VERSION 5.8 ;
BUSBITCHARS "[]" ;
DIVIDERCHAR "/" ;
UNITS
    DATABASE MICRONS 1000 ;
END UNITS

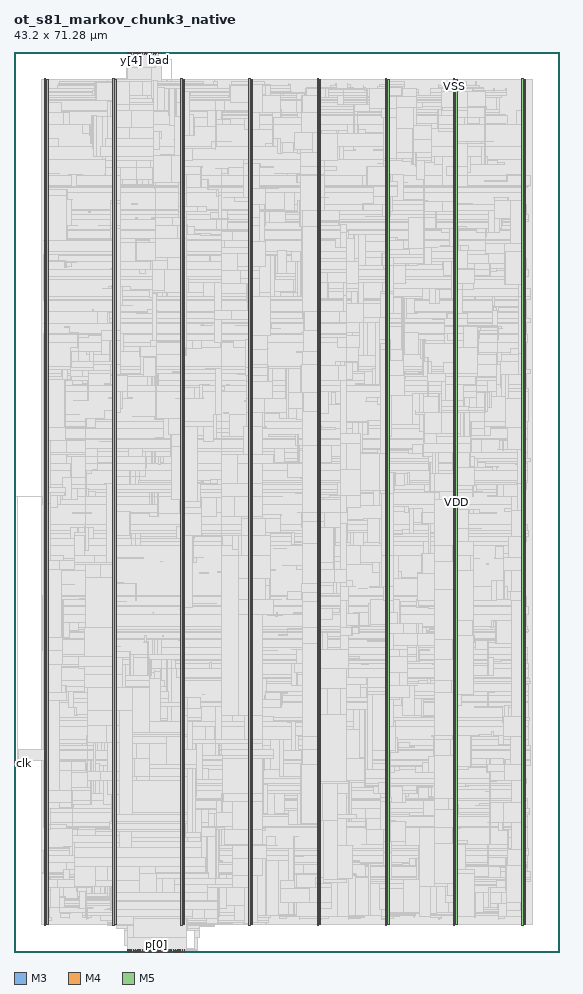
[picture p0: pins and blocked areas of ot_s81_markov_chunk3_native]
MACRO ot_s81_markov_chunk3_native
  FOREIGN ot_s81_markov_chunk3_native 0 0 ;
  CLASS BLOCK ;
  SIZE 43.2 BY 71.28 ;
  PIN bad
    DIRECTION OUTPUT ;
    USE SIGNAL ;
    PORT
      LAYER M3 ;
        RECT  11.448 71.136 11.466 71.28 ;
    END
  END bad
  PIN clk
    DIRECTION INPUT ;
    USE SIGNAL ;
    PORT
      LAYER M4 ;
        RECT  0 14.88 0.192 14.904 ;
    END
  END clk
  PIN p[0]
    DIRECTION INPUT ;
    USE SIGNAL ;
    PORT
      LAYER M3 ;
        RECT  11.304 0 11.322 0.144 ;
    END
  END p[0]
  PIN p[10]
    DIRECTION INPUT ;
    USE SIGNAL ;
    PORT
      LAYER M3 ;
        RECT  12.024 0 12.042 0.144 ;
    END
  END p[10]
  PIN p[11]
    DIRECTION INPUT ;
    USE SIGNAL ;
    PORT
      LAYER M5 ;
        RECT  12.048 0 12.072 0.192 ;
    END
  END p[11]
  PIN p[12]
    DIRECTION INPUT ;
    USE SIGNAL ;
    PORT
      LAYER M3 ;
        RECT  12.168 0 12.186 0.144 ;
    END
  END p[12]
  PIN p[13]
    DIRECTION INPUT ;
    USE SIGNAL ;
    PORT
      LAYER M5 ;
        RECT  12.192 0 12.216 0.192 ;
    END
  END p[13]
  PIN p[14]
    DIRECTION INPUT ;
    USE SIGNAL ;
    PORT
      LAYER M3 ;
        RECT  12.312 0 12.33 0.144 ;
    END
  END p[14]
  PIN p[15]
    DIRECTION INPUT ;
    USE SIGNAL ;
    PORT
      LAYER M5 ;
        RECT  12.336 0 12.36 0.192 ;
    END
  END p[15]
  PIN p[16]
    DIRECTION INPUT ;
    USE SIGNAL ;
    PORT
      LAYER M3 ;
        RECT  12.456 0 12.474 0.144 ;
    END
  END p[16]
  PIN p[17]
    DIRECTION INPUT ;
    USE SIGNAL ;
    PORT
      LAYER M5 ;
        RECT  12.48 0 12.504 0.192 ;
    END
  END p[17]
  PIN p[18]
    DIRECTION INPUT ;
    USE SIGNAL ;
    PORT
      LAYER M3 ;
        RECT  12.6 0 12.618 0.144 ;
    END
  END p[18]
  PIN p[19]
    DIRECTION INPUT ;
    USE SIGNAL ;
    PORT
      LAYER M5 ;
        RECT  12.624 0 12.648 0.192 ;
    END
  END p[19]
  PIN p[1]
    DIRECTION INPUT ;
    USE SIGNAL ;
    PORT
      LAYER M5 ;
        RECT  11.328 0 11.352 0.192 ;
    END
  END p[1]
  PIN p[20]
    DIRECTION INPUT ;
    USE SIGNAL ;
    PORT
      LAYER M3 ;
        RECT  12.744 0 12.762 0.144 ;
    END
  END p[20]
  PIN p[21]
    DIRECTION INPUT ;
    USE SIGNAL ;
    PORT
      LAYER M5 ;
        RECT  12.768 0 12.792 0.192 ;
    END
  END p[21]
  PIN p[22]
    DIRECTION INPUT ;
    USE SIGNAL ;
    PORT
      LAYER M3 ;
        RECT  12.888 0 12.906 0.144 ;
    END
  END p[22]
  PIN p[23]
    DIRECTION INPUT ;
    USE SIGNAL ;
    PORT
      LAYER M5 ;
        RECT  12.912 0 12.936 0.192 ;
    END
  END p[23]
  PIN p[24]
    DIRECTION INPUT ;
    USE SIGNAL ;
    PORT
      LAYER M3 ;
        RECT  13.032 0 13.05 0.144 ;
    END
  END p[24]
  PIN p[25]
    DIRECTION INPUT ;
    USE SIGNAL ;
    PORT
      LAYER M5 ;
        RECT  13.056 0 13.08 0.192 ;
    END
  END p[25]
  PIN p[26]
    DIRECTION INPUT ;
    USE SIGNAL ;
    PORT
      LAYER M3 ;
        RECT  13.176 0 13.194 0.144 ;
    END
  END p[26]
  PIN p[27]
    DIRECTION INPUT ;
    USE SIGNAL ;
    PORT
      LAYER M5 ;
        RECT  13.2 0 13.224 0.192 ;
    END
  END p[27]
  PIN p[28]
    DIRECTION INPUT ;
    USE SIGNAL ;
    PORT
      LAYER M3 ;
        RECT  13.32 0 13.338 0.144 ;
    END
  END p[28]
  PIN p[29]
    DIRECTION INPUT ;
    USE SIGNAL ;
    PORT
      LAYER M5 ;
        RECT  13.344 0 13.368 0.192 ;
    END
  END p[29]
  PIN p[2]
    DIRECTION INPUT ;
    USE SIGNAL ;
    PORT
      LAYER M3 ;
        RECT  11.448 0 11.466 0.144 ;
    END
  END p[2]
  PIN p[30]
    DIRECTION INPUT ;
    USE SIGNAL ;
    PORT
      LAYER M3 ;
        RECT  13.464 0 13.482 0.144 ;
    END
  END p[30]
  PIN p[31]
    DIRECTION INPUT ;
    USE SIGNAL ;
    PORT
      LAYER M5 ;
        RECT  13.488 0 13.512 0.192 ;
    END
  END p[31]
  PIN p[3]
    DIRECTION INPUT ;
    USE SIGNAL ;
    PORT
      LAYER M5 ;
        RECT  11.472 0 11.496 0.192 ;
    END
  END p[3]
  PIN p[4]
    DIRECTION INPUT ;
    USE SIGNAL ;
    PORT
      LAYER M3 ;
        RECT  11.592 0 11.61 0.144 ;
    END
  END p[4]
  PIN p[5]
    DIRECTION INPUT ;
    USE SIGNAL ;
    PORT
      LAYER M5 ;
        RECT  11.616 0 11.64 0.192 ;
    END
  END p[5]
  PIN p[6]
    DIRECTION INPUT ;
    USE SIGNAL ;
    PORT
      LAYER M3 ;
        RECT  11.736 0 11.754 0.144 ;
    END
  END p[6]
  PIN p[7]
    DIRECTION INPUT ;
    USE SIGNAL ;
    PORT
      LAYER M5 ;
        RECT  11.76 0 11.784 0.192 ;
    END
  END p[7]
  PIN p[8]
    DIRECTION INPUT ;
    USE SIGNAL ;
    PORT
      LAYER M3 ;
        RECT  11.88 0 11.898 0.144 ;
    END
  END p[8]
  PIN p[9]
    DIRECTION INPUT ;
    USE SIGNAL ;
    PORT
      LAYER M5 ;
        RECT  11.904 0 11.928 0.192 ;
    END
  END p[9]
  PIN rst_n
    DIRECTION INPUT ;
    USE SIGNAL ;
    PORT
      LAYER M4 ;
        RECT  0 15.024 0.192 15.048 ;
    END
  END rst_n
  PIN sum[0]
    DIRECTION INPUT ;
    USE SIGNAL ;
    PORT
      LAYER M3 ;
        RECT  9 0 9.018 0.144 ;
    END
  END sum[0]
  PIN sum[10]
    DIRECTION INPUT ;
    USE SIGNAL ;
    PORT
      LAYER M3 ;
        RECT  9.72 0 9.738 0.144 ;
    END
  END sum[10]
  PIN sum[11]
    DIRECTION INPUT ;
    USE SIGNAL ;
    PORT
      LAYER M5 ;
        RECT  9.744 0 9.768 0.192 ;
    END
  END sum[11]
  PIN sum[12]
    DIRECTION INPUT ;
    USE SIGNAL ;
    PORT
      LAYER M3 ;
        RECT  9.864 0 9.882 0.144 ;
    END
  END sum[12]
  PIN sum[13]
    DIRECTION INPUT ;
    USE SIGNAL ;
    PORT
      LAYER M5 ;
        RECT  9.888 0 9.912 0.192 ;
    END
  END sum[13]
  PIN sum[14]
    DIRECTION INPUT ;
    USE SIGNAL ;
    PORT
      LAYER M3 ;
        RECT  10.008 0 10.026 0.144 ;
    END
  END sum[14]
  PIN sum[15]
    DIRECTION INPUT ;
    USE SIGNAL ;
    PORT
      LAYER M5 ;
        RECT  10.032 0 10.056 0.192 ;
    END
  END sum[15]
  PIN sum[16]
    DIRECTION INPUT ;
    USE SIGNAL ;
    PORT
      LAYER M3 ;
        RECT  10.152 0 10.17 0.144 ;
    END
  END sum[16]
  PIN sum[17]
    DIRECTION INPUT ;
    USE SIGNAL ;
    PORT
      LAYER M5 ;
        RECT  10.176 0 10.2 0.192 ;
    END
  END sum[17]
  PIN sum[18]
    DIRECTION INPUT ;
    USE SIGNAL ;
    PORT
      LAYER M3 ;
        RECT  10.296 0 10.314 0.144 ;
    END
  END sum[18]
  PIN sum[19]
    DIRECTION INPUT ;
    USE SIGNAL ;
    PORT
      LAYER M5 ;
        RECT  10.32 0 10.344 0.192 ;
    END
  END sum[19]
  PIN sum[1]
    DIRECTION INPUT ;
    USE SIGNAL ;
    PORT
      LAYER M5 ;
        RECT  9.024 0 9.048 0.192 ;
    END
  END sum[1]
  PIN sum[20]
    DIRECTION INPUT ;
    USE SIGNAL ;
    PORT
      LAYER M3 ;
        RECT  10.44 0 10.458 0.144 ;
    END
  END sum[20]
  PIN sum[21]
    DIRECTION INPUT ;
    USE SIGNAL ;
    PORT
      LAYER M5 ;
        RECT  10.464 0 10.488 0.192 ;
    END
  END sum[21]
  PIN sum[22]
    DIRECTION INPUT ;
    USE SIGNAL ;
    PORT
      LAYER M3 ;
        RECT  10.584 0 10.602 0.144 ;
    END
  END sum[22]
  PIN sum[23]
    DIRECTION INPUT ;
    USE SIGNAL ;
    PORT
      LAYER M5 ;
        RECT  10.608 0 10.632 0.192 ;
    END
  END sum[23]
  PIN sum[24]
    DIRECTION INPUT ;
    USE SIGNAL ;
    PORT
      LAYER M3 ;
        RECT  10.728 0 10.746 0.144 ;
    END
  END sum[24]
  PIN sum[25]
    DIRECTION INPUT ;
    USE SIGNAL ;
    PORT
      LAYER M5 ;
        RECT  10.752 0 10.776 0.192 ;
    END
  END sum[25]
  PIN sum[26]
    DIRECTION INPUT ;
    USE SIGNAL ;
    PORT
      LAYER M3 ;
        RECT  10.872 0 10.89 0.144 ;
    END
  END sum[26]
  PIN sum[27]
    DIRECTION INPUT ;
    USE SIGNAL ;
    PORT
      LAYER M5 ;
        RECT  10.896 0 10.92 0.192 ;
    END
  END sum[27]
  PIN sum[28]
    DIRECTION INPUT ;
    USE SIGNAL ;
    PORT
      LAYER M3 ;
        RECT  11.016 0 11.034 0.144 ;
    END
  END sum[28]
  PIN sum[29]
    DIRECTION INPUT ;
    USE SIGNAL ;
    PORT
      LAYER M5 ;
        RECT  11.04 0 11.064 0.192 ;
    END
  END sum[29]
  PIN sum[2]
    DIRECTION INPUT ;
    USE SIGNAL ;
    PORT
      LAYER M3 ;
        RECT  9.144 0 9.162 0.144 ;
    END
  END sum[2]
  PIN sum[30]
    DIRECTION INPUT ;
    USE SIGNAL ;
    PORT
      LAYER M3 ;
        RECT  11.16 0 11.178 0.144 ;
    END
  END sum[30]
  PIN sum[31]
    DIRECTION INPUT ;
    USE SIGNAL ;
    PORT
      LAYER M5 ;
        RECT  11.184 0 11.208 0.192 ;
    END
  END sum[31]
  PIN sum[3]
    DIRECTION INPUT ;
    USE SIGNAL ;
    PORT
      LAYER M5 ;
        RECT  9.168 0 9.192 0.192 ;
    END
  END sum[3]
  PIN sum[4]
    DIRECTION INPUT ;
    USE SIGNAL ;
    PORT
      LAYER M3 ;
        RECT  9.288 0 9.306 0.144 ;
    END
  END sum[4]
  PIN sum[5]
    DIRECTION INPUT ;
    USE SIGNAL ;
    PORT
      LAYER M5 ;
        RECT  9.312 0 9.336 0.192 ;
    END
  END sum[5]
  PIN sum[6]
    DIRECTION INPUT ;
    USE SIGNAL ;
    PORT
      LAYER M3 ;
        RECT  9.432 0 9.45 0.144 ;
    END
  END sum[6]
  PIN sum[7]
    DIRECTION INPUT ;
    USE SIGNAL ;
    PORT
      LAYER M5 ;
        RECT  9.456 0 9.48 0.192 ;
    END
  END sum[7]
  PIN sum[8]
    DIRECTION INPUT ;
    USE SIGNAL ;
    PORT
      LAYER M3 ;
        RECT  9.576 0 9.594 0.144 ;
    END
  END sum[8]
  PIN sum[9]
    DIRECTION INPUT ;
    USE SIGNAL ;
    PORT
      LAYER M5 ;
        RECT  9.6 0 9.624 0.192 ;
    END
  END sum[9]
  PIN vin
    DIRECTION INPUT ;
    USE SIGNAL ;
    PORT
      LAYER M4 ;
        RECT  0 15.168 0.192 15.192 ;
    END
  END vin
  PIN vout
    DIRECTION OUTPUT ;
    USE SIGNAL ;
    PORT
      LAYER M3 ;
        RECT  11.304 71.136 11.322 71.28 ;
    END
  END vout
  PIN y[0]
    DIRECTION OUTPUT ;
    USE SIGNAL ;
    PORT
      LAYER M3 ;
        RECT  9 71.136 9.018 71.28 ;
    END
  END y[0]
  PIN y[10]
    DIRECTION OUTPUT ;
    USE SIGNAL ;
    PORT
      LAYER M3 ;
        RECT  9.72 71.136 9.738 71.28 ;
    END
  END y[10]
  PIN y[11]
    DIRECTION OUTPUT ;
    USE SIGNAL ;
    PORT
      LAYER M5 ;
        RECT  9.744 71.088 9.768 71.28 ;
    END
  END y[11]
  PIN y[12]
    DIRECTION OUTPUT ;
    USE SIGNAL ;
    PORT
      LAYER M3 ;
        RECT  9.864 71.136 9.882 71.28 ;
    END
  END y[12]
  PIN y[13]
    DIRECTION OUTPUT ;
    USE SIGNAL ;
    PORT
      LAYER M5 ;
        RECT  9.888 71.088 9.912 71.28 ;
    END
  END y[13]
  PIN y[14]
    DIRECTION OUTPUT ;
    USE SIGNAL ;
    PORT
      LAYER M3 ;
        RECT  10.008 71.136 10.026 71.28 ;
    END
  END y[14]
  PIN y[15]
    DIRECTION OUTPUT ;
    USE SIGNAL ;
    PORT
      LAYER M5 ;
        RECT  10.032 71.088 10.056 71.28 ;
    END
  END y[15]
  PIN y[16]
    DIRECTION OUTPUT ;
    USE SIGNAL ;
    PORT
      LAYER M3 ;
        RECT  10.152 71.136 10.17 71.28 ;
    END
  END y[16]
  PIN y[17]
    DIRECTION OUTPUT ;
    USE SIGNAL ;
    PORT
      LAYER M5 ;
        RECT  10.176 71.088 10.2 71.28 ;
    END
  END y[17]
  PIN y[18]
    DIRECTION OUTPUT ;
    USE SIGNAL ;
    PORT
      LAYER M3 ;
        RECT  10.296 71.136 10.314 71.28 ;
    END
  END y[18]
  PIN y[19]
    DIRECTION OUTPUT ;
    USE SIGNAL ;
    PORT
      LAYER M5 ;
        RECT  10.32 71.088 10.344 71.28 ;
    END
  END y[19]
  PIN y[1]
    DIRECTION OUTPUT ;
    USE SIGNAL ;
    PORT
      LAYER M5 ;
        RECT  9.024 71.088 9.048 71.28 ;
    END
  END y[1]
  PIN y[20]
    DIRECTION OUTPUT ;
    USE SIGNAL ;
    PORT
      LAYER M3 ;
        RECT  10.44 71.136 10.458 71.28 ;
    END
  END y[20]
  PIN y[21]
    DIRECTION OUTPUT ;
    USE SIGNAL ;
    PORT
      LAYER M5 ;
        RECT  10.464 71.088 10.488 71.28 ;
    END
  END y[21]
  PIN y[22]
    DIRECTION OUTPUT ;
    USE SIGNAL ;
    PORT
      LAYER M3 ;
        RECT  10.584 71.136 10.602 71.28 ;
    END
  END y[22]
  PIN y[23]
    DIRECTION OUTPUT ;
    USE SIGNAL ;
    PORT
      LAYER M5 ;
        RECT  10.608 71.088 10.632 71.28 ;
    END
  END y[23]
  PIN y[24]
    DIRECTION OUTPUT ;
    USE SIGNAL ;
    PORT
      LAYER M3 ;
        RECT  10.728 71.136 10.746 71.28 ;
    END
  END y[24]
  PIN y[25]
    DIRECTION OUTPUT ;
    USE SIGNAL ;
    PORT
      LAYER M5 ;
        RECT  10.752 71.088 10.776 71.28 ;
    END
  END y[25]
  PIN y[26]
    DIRECTION OUTPUT ;
    USE SIGNAL ;
    PORT
      LAYER M3 ;
        RECT  10.872 71.136 10.89 71.28 ;
    END
  END y[26]
  PIN y[27]
    DIRECTION OUTPUT ;
    USE SIGNAL ;
    PORT
      LAYER M5 ;
        RECT  10.896 71.088 10.92 71.28 ;
    END
  END y[27]
  PIN y[28]
    DIRECTION OUTPUT ;
    USE SIGNAL ;
    PORT
      LAYER M3 ;
        RECT  11.016 71.136 11.034 71.28 ;
    END
  END y[28]
  PIN y[29]
    DIRECTION OUTPUT ;
    USE SIGNAL ;
    PORT
      LAYER M5 ;
        RECT  11.04 71.088 11.064 71.28 ;
    END
  END y[29]
  PIN y[2]
    DIRECTION OUTPUT ;
    USE SIGNAL ;
    PORT
      LAYER M3 ;
        RECT  9.144 71.136 9.162 71.28 ;
    END
  END y[2]
  PIN y[30]
    DIRECTION OUTPUT ;
    USE SIGNAL ;
    PORT
      LAYER M3 ;
        RECT  11.16 71.136 11.178 71.28 ;
    END
  END y[30]
  PIN y[31]
    DIRECTION OUTPUT ;
    USE SIGNAL ;
    PORT
      LAYER M5 ;
        RECT  11.184 71.088 11.208 71.28 ;
    END
  END y[31]
  PIN y[3]
    DIRECTION OUTPUT ;
    USE SIGNAL ;
    PORT
      LAYER M5 ;
        RECT  9.168 71.088 9.192 71.28 ;
    END
  END y[3]
  PIN y[4]
    DIRECTION OUTPUT ;
    USE SIGNAL ;
    PORT
      LAYER M3 ;
        RECT  9.288 71.136 9.306 71.28 ;
    END
  END y[4]
  PIN y[5]
    DIRECTION OUTPUT ;
    USE SIGNAL ;
    PORT
      LAYER M5 ;
        RECT  9.312 71.088 9.336 71.28 ;
    END
  END y[5]
  PIN y[6]
    DIRECTION OUTPUT ;
    USE SIGNAL ;
    PORT
      LAYER M3 ;
        RECT  9.432 71.136 9.45 71.28 ;
    END
  END y[6]
  PIN y[7]
    DIRECTION OUTPUT ;
    USE SIGNAL ;
    PORT
      LAYER M5 ;
        RECT  9.456 71.088 9.48 71.28 ;
    END
  END y[7]
  PIN y[8]
    DIRECTION OUTPUT ;
    USE SIGNAL ;
    PORT
      LAYER M3 ;
        RECT  9.576 71.136 9.594 71.28 ;
    END
  END y[8]
  PIN y[9]
    DIRECTION OUTPUT ;
    USE SIGNAL ;
    PORT
      LAYER M5 ;
        RECT  9.6 71.088 9.624 71.28 ;
    END
  END y[9]
  PIN VDD
    DIRECTION INOUT ;
    USE POWER ;
    PORT
      LAYER M5 ;
        RECT  40.392 2.151 40.512 69.129 ;
        RECT  34.992 2.151 35.112 69.129 ;
        RECT  29.592 2.151 29.712 69.129 ;
        RECT  24.192 2.151 24.312 69.129 ;
        RECT  18.792 2.151 18.912 69.129 ;
        RECT  13.392 2.151 13.512 69.129 ;
        RECT  7.992 2.151 8.112 69.129 ;
        RECT  2.592 2.151 2.712 69.129 ;
    END
  END VDD
  PIN VSS
    DIRECTION INOUT ;
    USE GROUND ;
    PORT
      LAYER M5 ;
        RECT  40.2 2.137 40.32 69.143 ;
        RECT  34.8 2.137 34.92 69.143 ;
        RECT  29.4 2.137 29.52 69.143 ;
        RECT  24 2.137 24.12 69.143 ;
        RECT  18.6 2.137 18.72 69.143 ;
        RECT  13.2 2.137 13.32 69.143 ;
        RECT  7.8 2.137 7.92 69.143 ;
        RECT  2.4 2.137 2.52 69.143 ;
    END
  END VSS
  # OT_OBS_CLOSED layer=M5 d_um=1.536 added=289
  OBS
    LAYER RVTN ;
     RECT  2.16 2.16 41.04 2.295 ;
     RECT  2.16 2.565 41.04 2.835 ;
     RECT  2.16 3.105 41.04 3.375 ;
     RECT  2.16 3.645 41.04 3.915 ;
     RECT  2.16 4.185 41.04 4.455 ;
     RECT  2.16 4.725 41.04 4.995 ;
     RECT  2.16 5.265 41.04 5.535 ;
     RECT  2.16 5.805 41.04 6.075 ;
     RECT  2.16 6.345 41.04 6.615 ;
     RECT  2.16 6.885 41.04 7.155 ;
     RECT  2.16 7.425 41.04 7.695 ;
     RECT  2.16 7.965 41.04 8.235 ;
     RECT  2.16 8.505 41.04 8.775 ;
     RECT  2.16 9.045 41.04 9.315 ;
     RECT  2.16 9.585 41.04 9.855 ;
     RECT  2.16 10.125 41.04 10.395 ;
     RECT  2.16 10.665 41.04 10.935 ;
     RECT  2.16 11.205 41.04 11.475 ;
     RECT  2.16 11.745 41.04 12.015 ;
     RECT  2.16 12.285 41.04 12.555 ;
     RECT  2.16 12.825 41.04 13.095 ;
     RECT  2.16 13.365 41.04 13.635 ;
     RECT  2.16 13.905 41.04 14.175 ;
     RECT  2.16 14.445 41.04 14.715 ;
     RECT  2.16 14.985 41.04 15.255 ;
     RECT  2.16 15.525 41.04 15.795 ;
     RECT  2.16 16.065 41.04 16.335 ;
     RECT  2.16 16.605 41.04 16.875 ;
     RECT  2.16 17.145 41.04 17.415 ;
     RECT  2.16 17.685 41.04 17.955 ;
     RECT  2.16 18.225 41.04 18.495 ;
     RECT  2.16 18.765 41.04 19.035 ;
     RECT  2.16 19.305 41.04 19.575 ;
     RECT  2.16 19.845 41.04 20.115 ;
     RECT  2.16 20.385 41.04 20.655 ;
     RECT  2.16 20.925 41.04 21.195 ;
     RECT  2.16 21.465 41.04 21.735 ;
     RECT  2.16 22.005 41.04 22.275 ;
     RECT  2.16 22.545 41.04 22.815 ;
     RECT  2.16 23.085 41.04 23.355 ;
     RECT  2.16 23.625 41.04 23.895 ;
     RECT  2.16 24.165 41.04 24.435 ;
     RECT  2.16 24.705 41.04 24.975 ;
     RECT  2.16 25.245 41.04 25.515 ;
     RECT  2.16 25.785 41.04 26.055 ;
     RECT  2.16 26.325 41.04 26.595 ;
     RECT  2.16 26.865 41.04 27.135 ;
     RECT  2.16 27.405 41.04 27.675 ;
     RECT  2.16 27.945 41.04 28.215 ;
     RECT  2.16 28.485 41.04 28.755 ;
     RECT  2.16 29.025 41.04 29.295 ;
     RECT  2.16 29.565 41.04 29.835 ;
     RECT  2.16 30.105 41.04 30.375 ;
     RECT  2.16 30.645 41.04 30.915 ;
     RECT  2.16 31.185 41.04 31.455 ;
     RECT  2.16 31.725 41.04 31.995 ;
     RECT  2.16 32.265 41.04 32.535 ;
     RECT  2.16 32.805 41.04 33.075 ;
     RECT  2.16 33.345 41.04 33.615 ;
     RECT  2.16 33.885 41.04 34.155 ;
     RECT  2.16 34.425 41.04 34.695 ;
     RECT  2.16 34.965 41.04 35.235 ;
     RECT  2.16 35.505 41.04 35.775 ;
     RECT  2.16 36.045 41.04 36.315 ;
     RECT  2.16 36.585 41.04 36.855 ;
     RECT  2.16 37.125 41.04 37.395 ;
     RECT  2.16 37.665 41.04 37.935 ;
     RECT  2.16 38.205 41.04 38.475 ;
     RECT  2.16 38.745 41.04 39.015 ;
     RECT  2.16 39.285 41.04 39.555 ;
     RECT  2.16 39.825 41.04 40.095 ;
     RECT  2.16 40.365 41.04 40.635 ;
     RECT  2.16 40.905 41.04 41.175 ;
     RECT  2.16 41.445 41.04 41.715 ;
     RECT  2.16 41.985 41.04 42.255 ;
     RECT  2.16 42.525 41.04 42.795 ;
     RECT  2.16 43.065 41.04 43.335 ;
     RECT  2.16 43.605 41.04 43.875 ;
     RECT  2.16 44.145 41.04 44.415 ;
     RECT  2.16 44.685 41.04 44.955 ;
     RECT  2.16 45.225 41.04 45.495 ;
     RECT  2.16 45.765 41.04 46.035 ;
     RECT  2.16 46.305 41.04 46.575 ;
     RECT  2.16 46.845 41.04 47.115 ;
     RECT  2.16 47.385 41.04 47.655 ;
     RECT  2.16 47.925 41.04 48.195 ;
     RECT  2.16 48.465 41.04 48.735 ;
     RECT  2.16 49.005 41.04 49.275 ;
     RECT  2.16 49.545 41.04 49.815 ;
     RECT  2.16 50.085 41.04 50.355 ;
     RECT  2.16 50.625 41.04 50.895 ;
     RECT  2.16 51.165 41.04 51.435 ;
     RECT  2.16 51.705 41.04 51.975 ;
     RECT  2.16 52.245 41.04 52.515 ;
     RECT  2.16 52.785 41.04 53.055 ;
     RECT  2.16 53.325 41.04 53.595 ;
     RECT  2.16 53.865 41.04 54.135 ;
     RECT  2.16 54.405 41.04 54.675 ;
     RECT  2.16 54.945 41.04 55.215 ;
     RECT  2.16 55.485 41.04 55.755 ;
     RECT  2.16 56.025 41.04 56.295 ;
     RECT  2.16 56.565 41.04 56.835 ;
     RECT  2.16 57.105 41.04 57.375 ;
     RECT  2.16 57.645 41.04 57.915 ;
     RECT  2.16 58.185 41.04 58.455 ;
     RECT  2.16 58.725 41.04 58.995 ;
     RECT  2.16 59.265 41.04 59.535 ;
     RECT  2.16 59.805 41.04 60.075 ;
     RECT  2.16 60.345 41.04 60.615 ;
     RECT  2.16 60.885 41.04 61.155 ;
     RECT  2.16 61.425 41.04 61.695 ;
     RECT  2.16 61.965 41.04 62.235 ;
     RECT  2.16 62.505 41.04 62.775 ;
     RECT  2.16 63.045 41.04 63.315 ;
     RECT  2.16 63.585 41.04 63.855 ;
     RECT  2.16 64.125 41.04 64.395 ;
     RECT  2.16 64.665 41.04 64.935 ;
     RECT  2.16 65.205 41.04 65.475 ;
     RECT  2.16 65.745 41.04 66.015 ;
     RECT  2.16 66.285 41.04 66.555 ;
     RECT  2.16 66.825 41.04 67.095 ;
     RECT  2.16 67.365 41.04 67.635 ;
     RECT  2.16 67.905 41.04 68.175 ;
     RECT  2.16 68.445 41.04 68.715 ;
     RECT  2.16 68.985 41.04 69.12 ;
    LAYER RVTP ;
     RECT  2.16 2.295 41.04 2.565 ;
     RECT  2.16 2.835 41.04 3.105 ;
     RECT  2.16 3.375 41.04 3.645 ;
     RECT  2.16 3.915 41.04 4.185 ;
     RECT  2.16 4.455 41.04 4.725 ;
     RECT  2.16 4.995 41.04 5.265 ;
     RECT  2.16 5.535 41.04 5.805 ;
     RECT  2.16 6.075 41.04 6.345 ;
     RECT  2.16 6.615 41.04 6.885 ;
     RECT  2.16 7.155 41.04 7.425 ;
     RECT  2.16 7.695 41.04 7.965 ;
     RECT  2.16 8.235 41.04 8.505 ;
     RECT  2.16 8.775 41.04 9.045 ;
     RECT  2.16 9.315 41.04 9.585 ;
     RECT  2.16 9.855 41.04 10.125 ;
     RECT  2.16 10.395 41.04 10.665 ;
     RECT  2.16 10.935 41.04 11.205 ;
     RECT  2.16 11.475 41.04 11.745 ;
     RECT  2.16 12.015 41.04 12.285 ;
     RECT  2.16 12.555 41.04 12.825 ;
     RECT  2.16 13.095 41.04 13.365 ;
     RECT  2.16 13.635 41.04 13.905 ;
     RECT  2.16 14.175 41.04 14.445 ;
     RECT  2.16 14.715 41.04 14.985 ;
     RECT  2.16 15.255 41.04 15.525 ;
     RECT  2.16 15.795 41.04 16.065 ;
     RECT  2.16 16.335 41.04 16.605 ;
     RECT  2.16 16.875 41.04 17.145 ;
     RECT  2.16 17.415 41.04 17.685 ;
     RECT  2.16 17.955 41.04 18.225 ;
     RECT  2.16 18.495 41.04 18.765 ;
     RECT  2.16 19.035 41.04 19.305 ;
     RECT  2.16 19.575 41.04 19.845 ;
     RECT  2.16 20.115 41.04 20.385 ;
     RECT  2.16 20.655 41.04 20.925 ;
     RECT  2.16 21.195 41.04 21.465 ;
     RECT  2.16 21.735 41.04 22.005 ;
     RECT  2.16 22.275 41.04 22.545 ;
     RECT  2.16 22.815 41.04 23.085 ;
     RECT  2.16 23.355 41.04 23.625 ;
     RECT  2.16 23.895 41.04 24.165 ;
     RECT  2.16 24.435 41.04 24.705 ;
     RECT  2.16 24.975 41.04 25.245 ;
     RECT  2.16 25.515 41.04 25.785 ;
     RECT  2.16 26.055 41.04 26.325 ;
     RECT  2.16 26.595 41.04 26.865 ;
     RECT  2.16 27.135 41.04 27.405 ;
     RECT  2.16 27.675 41.04 27.945 ;
     RECT  2.16 28.215 41.04 28.485 ;
     RECT  2.16 28.755 41.04 29.025 ;
     RECT  2.16 29.295 41.04 29.565 ;
     RECT  2.16 29.835 41.04 30.105 ;
     RECT  2.16 30.375 41.04 30.645 ;
     RECT  2.16 30.915 41.04 31.185 ;
     RECT  2.16 31.455 41.04 31.725 ;
     RECT  2.16 31.995 41.04 32.265 ;
     RECT  2.16 32.535 41.04 32.805 ;
     RECT  2.16 33.075 41.04 33.345 ;
     RECT  2.16 33.615 41.04 33.885 ;
     RECT  2.16 34.155 41.04 34.425 ;
     RECT  2.16 34.695 41.04 34.965 ;
     RECT  2.16 35.235 41.04 35.505 ;
     RECT  2.16 35.775 41.04 36.045 ;
     RECT  2.16 36.315 41.04 36.585 ;
     RECT  2.16 36.855 41.04 37.125 ;
     RECT  2.16 37.395 41.04 37.665 ;
     RECT  2.16 37.935 41.04 38.205 ;
     RECT  2.16 38.475 41.04 38.745 ;
     RECT  2.16 39.015 41.04 39.285 ;
     RECT  2.16 39.555 41.04 39.825 ;
     RECT  2.16 40.095 41.04 40.365 ;
     RECT  2.16 40.635 41.04 40.905 ;
     RECT  2.16 41.175 41.04 41.445 ;
     RECT  2.16 41.715 41.04 41.985 ;
     RECT  2.16 42.255 41.04 42.525 ;
     RECT  2.16 42.795 41.04 43.065 ;
     RECT  2.16 43.335 41.04 43.605 ;
     RECT  2.16 43.875 41.04 44.145 ;
     RECT  2.16 44.415 41.04 44.685 ;
     RECT  2.16 44.955 41.04 45.225 ;
     RECT  2.16 45.495 41.04 45.765 ;
     RECT  2.16 46.035 41.04 46.305 ;
     RECT  2.16 46.575 41.04 46.845 ;
     RECT  2.16 47.115 41.04 47.385 ;
     RECT  2.16 47.655 41.04 47.925 ;
     RECT  2.16 48.195 41.04 48.465 ;
     RECT  2.16 48.735 41.04 49.005 ;
     RECT  2.16 49.275 41.04 49.545 ;
     RECT  2.16 49.815 41.04 50.085 ;
     RECT  2.16 50.355 41.04 50.625 ;
     RECT  2.16 50.895 41.04 51.165 ;
     RECT  2.16 51.435 41.04 51.705 ;
     RECT  2.16 51.975 41.04 52.245 ;
     RECT  2.16 52.515 41.04 52.785 ;
     RECT  2.16 53.055 41.04 53.325 ;
     RECT  2.16 53.595 41.04 53.865 ;
     RECT  2.16 54.135 41.04 54.405 ;
     RECT  2.16 54.675 41.04 54.945 ;
     RECT  2.16 55.215 41.04 55.485 ;
     RECT  2.16 55.755 41.04 56.025 ;
     RECT  2.16 56.295 41.04 56.565 ;
     RECT  2.16 56.835 41.04 57.105 ;
     RECT  2.16 57.375 41.04 57.645 ;
     RECT  2.16 57.915 41.04 58.185 ;
     RECT  2.16 58.455 41.04 58.725 ;
     RECT  2.16 58.995 41.04 59.265 ;
     RECT  2.16 59.535 41.04 59.805 ;
     RECT  2.16 60.075 41.04 60.345 ;
     RECT  2.16 60.615 41.04 60.885 ;
     RECT  2.16 61.155 41.04 61.425 ;
     RECT  2.16 61.695 41.04 61.965 ;
     RECT  2.16 62.235 41.04 62.505 ;
     RECT  2.16 62.775 41.04 63.045 ;
     RECT  2.16 63.315 41.04 63.585 ;
     RECT  2.16 63.855 41.04 64.125 ;
     RECT  2.16 64.395 41.04 64.665 ;
     RECT  2.16 64.935 41.04 65.205 ;
     RECT  2.16 65.475 41.04 65.745 ;
     RECT  2.16 66.015 41.04 66.285 ;
     RECT  2.16 66.555 41.04 66.825 ;
     RECT  2.16 67.095 41.04 67.365 ;
     RECT  2.16 67.635 41.04 67.905 ;
     RECT  2.16 68.175 41.04 68.445 ;
     RECT  2.16 68.715 41.04 68.985 ;
    LAYER M1 ;
     RECT  2.16 2.151 41.04 69.129 ;
    LAYER M2 ;
     RECT  2.16 2.151 7.411 69.129 ;
     RECT  7.411 2.106 8.095 69.129 ;
     RECT  8.923 70.65 9.023 70.668 ;
     RECT  9.139 0.144 9.175 0.162 ;
     RECT  8.095 1.881 9.211 69.129 ;
     RECT  9.211 1.728 9.599 69.129 ;
     RECT  9.175 0.144 10.031 0.234 ;
     RECT  9.715 70.614 10.255 70.632 ;
     RECT  9.599 2.034 10.363 69.129 ;
     RECT  10.255 70.461 10.579 70.632 ;
     RECT  10.031 0.216 10.607 0.234 ;
     RECT  10.579 70.461 10.607 70.668 ;
     RECT  10.607 70.578 10.679 70.668 ;
     RECT  10.363 1.728 10.867 69.129 ;
     RECT  10.867 1.728 11.003 69.174 ;
     RECT  11.003 1.728 11.111 69.129 ;
     RECT  10.679 70.65 11.155 70.668 ;
     RECT  11.111 2.034 11.327 69.129 ;
     RECT  11.227 0.144 11.587 0.162 ;
     RECT  11.155 70.65 11.615 70.749 ;
     RECT  11.615 70.65 11.687 70.704 ;
     RECT  11.587 0.144 12.047 0.324 ;
     RECT  11.327 2.151 12.055 69.129 ;
     RECT  12.055 2.106 12.163 69.129 ;
     RECT  12.163 1.728 12.443 69.129 ;
     RECT  11.687 70.686 12.479 70.704 ;
     RECT  12.047 0.144 12.515 0.198 ;
     RECT  12.443 2.034 13.315 69.129 ;
     RECT  13.315 1.728 13.451 69.129 ;
     RECT  12.515 0.144 14.531 0.162 ;
     RECT  14.287 1.152 14.675 1.17 ;
     RECT  13.451 2.034 15.863 69.129 ;
     RECT  15.863 2.151 41.04 69.129 ;
    LAYER M3 ;
     RECT  9 0.108 13.482 0.167 ;
     RECT  14.508 0.139 14.526 0.235 ;
     RECT  9 0.167 13.338 0.523 ;
     RECT  14.292 0.235 14.526 1.147 ;
     RECT  8.748 0.523 13.338 1.723 ;
     RECT  14.292 1.147 14.67 1.723 ;
     RECT  8.748 1.723 14.67 1.876 ;
     RECT  8.1 1.876 14.67 2.101 ;
     RECT  15.84 2.029 15.858 2.101 ;
     RECT  7.416 2.101 15.858 2.191 ;
     RECT  18.615 2.143 18.705 2.191 ;
     RECT  7.416 2.191 16.326 2.227 ;
     RECT  18.252 2.191 18.705 2.299 ;
     RECT  19.944 2.263 19.962 2.299 ;
     RECT  18.072 2.299 19.962 2.335 ;
     RECT  7.416 2.227 17.334 2.371 ;
     RECT  18.072 2.335 20.142 2.371 ;
     RECT  2.415 2.143 2.505 2.413 ;
     RECT  24.015 2.143 24.105 2.413 ;
     RECT  29.415 2.143 29.505 2.413 ;
     RECT  34.815 2.143 34.905 2.413 ;
     RECT  40.215 2.143 40.305 2.413 ;
     RECT  7.416 2.371 20.142 2.525 ;
     RECT  2.415 2.413 2.697 2.533 ;
     RECT  7.416 2.525 17.442 2.533 ;
     RECT  24.015 2.413 24.297 2.605 ;
     RECT  29.415 2.413 29.697 2.605 ;
     RECT  5.76 2.605 5.778 2.641 ;
     RECT  22.608 2.605 22.626 2.641 ;
     RECT  24.015 2.605 24.39 2.641 ;
     RECT  26.496 2.605 26.514 2.641 ;
     RECT  29.088 2.605 29.697 2.641 ;
     RECT  33.66 2.605 33.678 2.641 ;
     RECT  38.376 2.605 38.394 2.641 ;
     RECT  4.392 2.641 4.41 2.731 ;
     RECT  5.76 2.641 5.886 2.731 ;
     RECT  18.216 2.525 20.142 2.731 ;
     RECT  2.415 2.533 2.97 2.759 ;
     RECT  18.216 2.731 20.322 2.759 ;
     RECT  26.496 2.641 27.45 2.767 ;
     RECT  33.66 2.641 33.822 2.767 ;
     RECT  34.815 2.413 35.097 2.767 ;
     RECT  26.496 2.767 27.774 2.803 ;
     RECT  29.088 2.641 30.042 2.803 ;
     RECT  22.608 2.641 24.93 2.827 ;
     RECT  21.06 2.641 21.618 2.839 ;
     RECT  22.608 2.827 25.11 2.839 ;
     RECT  26.28 2.803 27.774 2.839 ;
     RECT  31.716 2.767 31.734 2.839 ;
     RECT  34.776 2.767 35.097 2.839 ;
     RECT  38.376 2.641 38.862 2.86 ;
     RECT  18.288 2.759 20.322 2.869 ;
     RECT  21.06 2.839 25.146 2.869 ;
     RECT  29.088 2.803 30.546 2.875 ;
     RECT  31.608 2.839 31.734 2.875 ;
     RECT  32.976 2.767 33.822 2.875 ;
     RECT  34.776 2.839 35.154 2.875 ;
     RECT  5.436 2.731 6.138 2.911 ;
     RECT  6.876 2.533 17.442 2.911 ;
     RECT  18.288 2.869 25.146 2.911 ;
     RECT  26.1 2.839 27.774 2.911 ;
     RECT  28.512 2.875 31.77 2.911 ;
     RECT  36.504 2.731 36.522 2.911 ;
     RECT  38.34 2.86 38.862 2.911 ;
     RECT  18.288 2.911 25.218 3.001 ;
     RECT  26.028 2.911 31.77 3.001 ;
     RECT  32.976 2.875 35.154 3.001 ;
     RECT  18.288 3.001 31.77 3.019 ;
     RECT  36.36 2.911 39.006 3.019 ;
     RECT  40.215 2.413 40.497 3.019 ;
     RECT  3.708 2.731 4.41 3.073 ;
     RECT  3.708 3.073 4.482 3.109 ;
     RECT  18.288 3.019 32.022 3.115 ;
     RECT  32.976 3.001 35.622 3.115 ;
     RECT  3.708 3.109 4.59 3.145 ;
     RECT  5.436 2.911 17.442 3.145 ;
     RECT  18.288 3.115 35.622 3.145 ;
     RECT  36.36 3.019 40.497 3.145 ;
     RECT  18.288 3.145 40.497 3.181 ;
     RECT  18.288 3.181 40.518 3.341 ;
     RECT  3.6 3.145 17.442 3.691 ;
     RECT  18.288 3.341 40.497 3.691 ;
     RECT  2.415 2.759 2.79 3.721 ;
     RECT  3.6 3.691 40.497 3.721 ;
     RECT  2.415 3.721 40.497 3.839 ;
     RECT  2.415 3.839 22.014 3.875 ;
     RECT  22.752 3.839 40.497 3.875 ;
     RECT  22.752 3.875 37.674 3.911 ;
     RECT  22.752 3.911 35.73 3.947 ;
     RECT  2.415 3.875 21.726 4.109 ;
     RECT  22.788 3.947 35.73 4.109 ;
     RECT  2.415 4.109 21.582 4.145 ;
     RECT  2.415 4.145 21.51 4.253 ;
     RECT  5.04 4.253 21.51 4.289 ;
     RECT  2.415 4.253 4.086 4.379 ;
     RECT  5.04 4.289 21.294 4.415 ;
     RECT  22.86 4.109 35.73 4.415 ;
     RECT  36.504 3.911 37.674 4.679 ;
     RECT  28.872 4.415 35.73 4.693 ;
     RECT  36.504 4.679 37.71 4.693 ;
     RECT  38.628 3.875 40.497 4.693 ;
     RECT  22.104 5.029 22.122 5.071 ;
     RECT  22.86 4.415 27.846 5.071 ;
     RECT  2.415 4.379 3.906 5.269 ;
     RECT  22.104 5.071 27.846 5.305 ;
     RECT  28.872 4.693 40.497 5.305 ;
     RECT  2.415 5.269 4.014 5.323 ;
     RECT  17.244 4.415 21.294 5.323 ;
     RECT  22.104 5.305 40.497 5.323 ;
     RECT  5.04 4.415 16.47 5.341 ;
     RECT  17.244 5.323 40.497 5.341 ;
     RECT  5.04 5.341 40.497 5.611 ;
     RECT  2.415 5.323 4.086 5.701 ;
     RECT  2.376 5.701 4.086 5.707 ;
     RECT  5.004 5.611 40.914 5.707 ;
     RECT  2.376 5.707 40.914 5.873 ;
     RECT  2.376 5.873 37.602 5.999 ;
     RECT  2.376 5.999 27.09 6.143 ;
     RECT  2.376 6.143 27.018 6.179 ;
     RECT  2.376 6.179 22.158 6.269 ;
     RECT  2.415 6.269 22.158 6.305 ;
     RECT  38.556 5.873 40.914 6.341 ;
     RECT  38.556 6.341 40.698 6.655 ;
     RECT  27.828 5.999 37.602 6.781 ;
     RECT  38.484 6.655 40.698 6.781 ;
     RECT  27.828 6.781 40.698 6.889 ;
     RECT  4.932 6.305 22.158 6.925 ;
     RECT  22.896 6.179 26.802 6.925 ;
     RECT  27.792 6.889 40.698 6.925 ;
     RECT  2.415 6.305 4.122 7.051 ;
     RECT  4.932 6.925 40.698 7.051 ;
     RECT  2.415 7.051 40.698 7.627 ;
     RECT  2.415 7.627 40.734 8.011 ;
     RECT  2.376 8.011 40.734 8.159 ;
     RECT  2.415 8.159 40.698 9.859 ;
     RECT  2.304 9.859 40.698 9.965 ;
     RECT  2.304 9.965 15.426 10.253 ;
     RECT  16.236 9.965 40.698 10.705 ;
     RECT  16.164 10.705 40.698 10.867 ;
     RECT  2.304 10.253 15.39 11.011 ;
     RECT  16.164 10.867 40.842 11.011 ;
     RECT  2.304 11.011 40.842 11.399 ;
     RECT  2.304 11.399 40.698 11.981 ;
     RECT  2.304 11.981 33.246 12.011 ;
     RECT  9.144 12.011 33.246 12.047 ;
     RECT  9.18 12.047 33.246 12.119 ;
     RECT  34.236 11.981 40.698 12.119 ;
     RECT  32.796 12.119 33.246 12.245 ;
     RECT  32.796 12.245 33.174 12.281 ;
     RECT  2.304 12.011 8.406 12.829 ;
     RECT  9.18 12.119 32.058 12.829 ;
     RECT  34.236 12.119 40.497 12.901 ;
     RECT  32.796 12.281 33.066 13.051 ;
     RECT  2.304 12.829 32.058 13.171 ;
     RECT  32.796 13.051 33.138 13.171 ;
     RECT  33.912 12.901 40.497 13.171 ;
     RECT  2.304 13.171 40.497 13.333 ;
     RECT  2.304 13.333 40.554 13.739 ;
     RECT  2.304 13.739 40.497 14.791 ;
     RECT  2.304 14.791 40.878 15.163 ;
     RECT  2.268 15.163 40.878 15.215 ;
     RECT  2.304 15.215 40.878 15.979 ;
     RECT  2.268 15.979 40.878 16.025 ;
     RECT  2.304 16.025 40.878 16.331 ;
     RECT  2.304 16.331 40.77 16.799 ;
     RECT  2.304 16.799 15.174 16.835 ;
     RECT  2.304 16.835 15.138 17.851 ;
     RECT  15.984 16.799 40.77 17.851 ;
     RECT  2.304 17.851 40.77 18.301 ;
     RECT  2.304 18.301 40.806 18.563 ;
     RECT  2.304 18.563 40.77 19.769 ;
     RECT  13.215 19.769 40.77 19.805 ;
     RECT  2.304 19.769 12.258 20.075 ;
     RECT  19.872 19.805 40.77 20.345 ;
     RECT  2.34 20.075 12.258 20.615 ;
     RECT  19.908 20.345 40.77 20.615 ;
     RECT  2.34 20.615 12.078 20.993 ;
     RECT  19.98 20.615 40.77 21.271 ;
     RECT  19.98 21.271 40.914 21.389 ;
     RECT  2.34 20.993 11.934 21.533 ;
     RECT  13.215 19.805 19.134 21.541 ;
     RECT  19.98 21.389 40.842 21.659 ;
     RECT  13.215 21.541 19.17 21.667 ;
     RECT  19.98 21.659 40.77 21.667 ;
     RECT  13.215 21.667 40.77 21.739 ;
     RECT  12.852 21.739 40.77 22.477 ;
     RECT  12.816 22.477 40.77 22.811 ;
     RECT  12.816 22.811 40.662 23.089 ;
     RECT  2.34 21.533 11.718 23.161 ;
     RECT  12.708 23.089 40.662 23.161 ;
     RECT  2.34 23.161 40.662 23.549 ;
     RECT  11.7 23.549 40.662 24.089 ;
     RECT  2.34 23.549 10.962 24.745 ;
     RECT  11.7 24.089 40.497 24.745 ;
     RECT  2.34 24.745 40.497 24.781 ;
     RECT  2.304 24.781 40.497 24.811 ;
     RECT  2.268 24.811 40.497 25.321 ;
     RECT  2.268 25.321 40.662 25.411 ;
     RECT  2.268 25.411 40.77 25.511 ;
     RECT  2.268 25.511 40.662 25.781 ;
     RECT  2.268 25.781 40.554 26.761 ;
     RECT  2.268 26.761 40.77 27.329 ;
     RECT  2.268 27.329 40.662 27.365 ;
     RECT  2.268 27.365 40.59 27.473 ;
     RECT  2.268 27.473 40.554 28.175 ;
     RECT  2.268 28.175 40.497 28.205 ;
     RECT  2.304 28.205 40.497 32.189 ;
     RECT  10.044 32.189 40.497 32.539 ;
     RECT  10.044 32.539 40.554 32.881 ;
     RECT  2.304 32.189 9.27 33.151 ;
     RECT  10.044 32.881 40.734 33.151 ;
     RECT  2.304 33.151 40.734 33.413 ;
     RECT  2.304 33.413 40.698 33.845 ;
     RECT  2.304 33.845 40.497 35.465 ;
     RECT  2.304 35.465 10.71 36.355 ;
     RECT  11.448 35.465 40.497 36.355 ;
     RECT  2.304 36.355 40.497 36.625 ;
     RECT  2.304 36.625 40.554 37.049 ;
     RECT  9.864 37.049 40.554 37.165 ;
     RECT  9.864 37.165 40.698 37.355 ;
     RECT  2.304 37.049 9.126 38.137 ;
     RECT  9.9 37.355 40.698 38.137 ;
     RECT  2.304 38.137 40.698 38.669 ;
     RECT  11.232 38.669 40.698 38.705 ;
     RECT  21.384 38.705 40.698 38.821 ;
     RECT  21.384 38.821 40.914 39.083 ;
     RECT  21.384 39.083 40.698 39.551 ;
     RECT  2.304 38.669 10.422 39.631 ;
     RECT  11.232 38.705 20.61 39.631 ;
     RECT  2.304 39.631 20.61 39.865 ;
     RECT  2.304 39.865 20.646 39.901 ;
     RECT  21.384 39.551 36.27 39.901 ;
     RECT  2.304 39.901 36.27 40.567 ;
     RECT  37.008 39.551 40.698 40.567 ;
     RECT  2.304 40.567 40.698 40.703 ;
     RECT  2.304 40.703 35.19 41.485 ;
     RECT  35.964 40.703 40.698 41.485 ;
     RECT  2.304 41.485 40.698 42.025 ;
     RECT  2.304 42.025 40.734 44.429 ;
     RECT  38.304 44.429 40.734 44.609 ;
     RECT  2.304 44.429 37.494 44.879 ;
     RECT  11.448 44.879 37.494 45.229 ;
     RECT  38.304 44.609 40.626 45.229 ;
     RECT  2.304 44.879 10.566 45.841 ;
     RECT  11.448 45.229 40.626 45.841 ;
     RECT  2.304 45.841 40.914 46.103 ;
     RECT  2.304 46.103 40.626 46.373 ;
     RECT  2.34 46.373 40.626 48.271 ;
     RECT  2.34 48.271 40.662 48.929 ;
     RECT  2.34 48.929 40.626 48.965 ;
     RECT  2.376 48.965 40.626 49.739 ;
     RECT  2.376 49.739 6.858 49.775 ;
     RECT  7.596 49.739 40.626 49.891 ;
     RECT  7.596 49.891 40.914 50.153 ;
     RECT  7.596 50.153 40.626 50.665 ;
     RECT  2.376 49.775 6.642 50.693 ;
     RECT  2.415 50.693 6.642 50.701 ;
     RECT  7.416 50.665 40.626 50.701 ;
     RECT  2.415 50.701 40.626 51.601 ;
     RECT  2.34 51.601 40.626 51.709 ;
     RECT  2.34 51.709 40.914 51.917 ;
     RECT  23.004 51.917 40.914 52.511 ;
     RECT  2.34 51.917 22.158 53.227 ;
     RECT  23.004 52.511 40.497 53.227 ;
     RECT  2.34 53.227 40.497 53.491 ;
     RECT  2.34 53.491 40.734 54.059 ;
     RECT  2.34 54.059 40.59 54.701 ;
     RECT  22.68 54.701 40.59 54.941 ;
     RECT  2.34 54.701 21.942 55.175 ;
     RECT  2.376 55.175 21.942 55.277 ;
     RECT  2.415 55.277 21.942 55.489 ;
     RECT  22.68 54.941 40.497 55.489 ;
     RECT  2.415 55.489 40.497 56.347 ;
     RECT  2.376 56.347 40.497 56.399 ;
     RECT  2.415 56.399 40.497 57.181 ;
     RECT  2.376 57.181 40.497 57.209 ;
     RECT  16.884 57.209 40.497 57.811 ;
     RECT  16.884 57.811 40.518 57.847 ;
     RECT  2.376 57.209 16.002 57.991 ;
     RECT  16.884 57.847 40.77 57.991 ;
     RECT  2.376 57.991 40.77 58.379 ;
     RECT  2.376 58.379 40.662 58.415 ;
     RECT  2.376 58.415 40.554 58.721 ;
     RECT  2.376 58.721 21.402 58.829 ;
     RECT  22.176 58.721 40.554 59.189 ;
     RECT  2.415 58.829 21.402 60.151 ;
     RECT  22.176 59.189 40.497 60.151 ;
     RECT  2.376 60.151 40.497 60.539 ;
     RECT  2.415 60.539 40.497 60.547 ;
     RECT  2.415 60.547 40.662 60.655 ;
     RECT  2.415 60.655 40.77 60.691 ;
     RECT  2.415 60.691 40.914 61.493 ;
     RECT  2.415 61.493 40.497 62.743 ;
     RECT  2.376 62.743 40.497 63.815 ;
     RECT  2.415 63.815 40.497 65.507 ;
     RECT  2.415 65.507 39.078 65.549 ;
     RECT  16.524 65.549 39.078 66.245 ;
     RECT  16.524 66.245 38.898 66.317 ;
     RECT  16.524 66.317 38.466 66.479 ;
     RECT  20.448 66.479 22.518 66.515 ;
     RECT  2.415 65.549 15.714 66.595 ;
     RECT  16.524 66.479 19.674 66.595 ;
     RECT  2.415 66.595 19.674 66.653 ;
     RECT  39.816 65.507 40.497 66.659 ;
     RECT  23.292 66.479 38.466 66.749 ;
     RECT  23.292 66.749 37.386 66.989 ;
     RECT  23.292 66.989 37.35 67.261 ;
     RECT  2.415 66.653 15.966 67.441 ;
     RECT  16.704 66.653 19.674 67.441 ;
     RECT  20.448 66.515 22.41 67.441 ;
     RECT  23.22 67.261 37.35 67.441 ;
     RECT  2.415 67.441 19.674 67.531 ;
     RECT  20.448 67.441 37.35 67.531 ;
     RECT  38.196 66.749 38.466 67.639 ;
     RECT  2.415 67.531 37.35 67.711 ;
     RECT  38.196 67.639 38.574 67.711 ;
     RECT  2.415 67.711 38.574 67.801 ;
     RECT  2.415 67.801 39.042 67.829 ;
     RECT  2.415 67.829 32.058 68.099 ;
     RECT  32.976 67.829 39.042 68.099 ;
     RECT  2.415 68.099 22.014 68.135 ;
     RECT  37.944 68.099 39.042 68.243 ;
     RECT  23.076 68.099 32.058 68.279 ;
     RECT  23.076 68.279 31.914 68.369 ;
     RECT  37.944 68.243 38.07 68.369 ;
     RECT  38.916 68.243 39.042 68.369 ;
     RECT  23.184 68.369 31.806 68.381 ;
     RECT  2.415 68.135 21.906 68.405 ;
     RECT  26.424 68.381 27.954 68.405 ;
     RECT  28.764 68.381 31.806 68.405 ;
     RECT  32.976 68.099 37.206 68.405 ;
     RECT  37.944 68.369 37.962 68.405 ;
     RECT  38.916 68.369 38.934 68.405 ;
     RECT  23.184 68.381 25.506 68.429 ;
     RECT  33.624 68.405 37.206 68.429 ;
     RECT  26.424 68.405 26.874 68.441 ;
     RECT  23.508 68.429 24.297 68.477 ;
     RECT  27.684 68.405 27.846 68.477 ;
     RECT  28.764 68.405 30.906 68.549 ;
     RECT  3.456 68.405 16.146 68.639 ;
     RECT  17.208 68.405 21.906 68.639 ;
     RECT  25.092 68.429 25.506 68.639 ;
     RECT  27.684 68.477 27.702 68.639 ;
     RECT  33.624 68.429 36.882 68.639 ;
     RECT  3.528 68.639 16.146 68.675 ;
     RECT  17.208 68.639 20.286 68.675 ;
     RECT  21.708 68.639 21.906 68.675 ;
     RECT  26.424 68.441 26.658 68.675 ;
     RECT  33.624 68.639 33.642 68.675 ;
     RECT  28.908 68.549 30.906 68.711 ;
     RECT  21.708 68.675 21.726 68.747 ;
     RECT  26.424 68.675 26.442 68.747 ;
     RECT  3.528 68.675 14.994 68.783 ;
     RECT  25.488 68.639 25.506 68.783 ;
     RECT  2.415 68.405 2.697 68.867 ;
     RECT  24.015 68.477 24.297 68.867 ;
     RECT  40.215 66.659 40.497 68.867 ;
     RECT  3.6 68.783 14.994 68.909 ;
     RECT  15.804 68.675 16.146 68.909 ;
     RECT  17.208 68.675 19.818 68.909 ;
     RECT  29.415 68.711 30.906 68.909 ;
     RECT  34.632 68.639 35.802 68.909 ;
     RECT  36.576 68.639 36.594 68.909 ;
     RECT  3.6 68.909 3.618 68.945 ;
     RECT  4.896 68.909 4.914 68.945 ;
     RECT  5.904 68.909 7.905 68.945 ;
     RECT  15.948 68.909 15.966 68.945 ;
     RECT  17.208 68.909 17.226 68.945 ;
     RECT  17.964 68.909 18.705 68.945 ;
     RECT  19.692 68.909 19.71 68.945 ;
     RECT  29.415 68.909 30.762 68.945 ;
     RECT  34.815 68.909 34.974 68.945 ;
     RECT  6.192 68.945 6.21 68.981 ;
     RECT  12.456 68.909 13.662 68.981 ;
     RECT  29.415 68.945 30.114 68.981 ;
     RECT  2.415 68.867 2.505 69.137 ;
     RECT  7.815 68.945 7.905 69.137 ;
     RECT  13.215 68.981 13.305 69.137 ;
     RECT  18.615 68.945 18.705 69.137 ;
     RECT  24.015 68.867 24.105 69.137 ;
     RECT  29.415 68.981 29.505 69.137 ;
     RECT  34.815 68.945 34.905 69.137 ;
     RECT  40.215 68.867 40.305 69.137 ;
     RECT  8.928 68.909 11.718 70.673 ;
     RECT  12.456 68.981 12.474 70.709 ;
     RECT  9 70.673 11.718 70.733 ;
     RECT  9 70.733 11.61 70.754 ;
     RECT  9 70.754 11.502 70.781 ;
     RECT  9 70.781 11.466 71.148 ;
    LAYER M4 ;
     RECT  0.156 14.88 0.275 15.192 ;
     RECT  0.275 15.024 0.325 15.192 ;
     RECT  0.325 15.024 0.371 16.008 ;
     RECT  2.257 24.816 2.293 24.84 ;
     RECT  0.229 36.048 2.293 36.072 ;
     RECT  2.329 17.472 2.365 17.496 ;
     RECT  2.293 23.856 2.365 24.936 ;
     RECT  2.257 28.176 2.365 28.2 ;
     RECT  2.293 35.472 2.365 36.072 ;
     RECT  2.293 6.24 2.408 6.264 ;
     RECT  2.293 8.016 2.408 8.04 ;
     RECT  2.365 12.864 2.408 12.888 ;
     RECT  0.371 15.168 2.408 16.008 ;
     RECT  2.365 17.472 2.408 17.688 ;
     RECT  2.365 21.696 2.408 21.72 ;
     RECT  2.365 23.856 2.408 25.56 ;
     RECT  2.365 27.648 2.408 28.2 ;
     RECT  2.365 32.208 2.408 32.232 ;
     RECT  2.365 35.184 2.408 36.072 ;
     RECT  2.365 38.736 2.408 38.76 ;
     RECT  2.365 44.448 2.408 44.472 ;
     RECT  2.365 49.776 2.408 49.8 ;
     RECT  2.365 55.248 2.408 55.272 ;
     RECT  2.365 56.352 2.408 56.376 ;
     RECT  2.408 2.148 2.512 69.132 ;
     RECT  2.512 2.418 2.704 68.862 ;
     RECT  2.704 11.376 2.819 12.888 ;
     RECT  2.704 14.304 2.819 17.688 ;
     RECT  2.704 3.504 2.867 5.784 ;
     RECT  2.819 16.512 2.905 17.688 ;
     RECT  2.704 20.208 2.905 29.112 ;
     RECT  2.905 17.664 3.017 17.688 ;
     RECT  2.704 38.688 3.053 38.76 ;
     RECT  2.704 19.104 3.107 19.128 ;
     RECT  2.905 28.944 3.341 29.112 ;
     RECT  2.819 12.864 3.377 12.888 ;
     RECT  2.704 43.92 3.377 44.472 ;
     RECT  2.905 20.208 3.443 27.912 ;
     RECT  3.443 22.56 3.449 27.912 ;
     RECT  2.704 35.184 3.449 36.744 ;
     RECT  2.704 56.352 3.449 56.424 ;
     RECT  3.449 22.56 3.521 23.544 ;
     RECT  2.704 54.768 3.557 55.272 ;
     RECT  2.704 63.792 3.557 64.44 ;
     RECT  2.819 11.376 3.587 11.4 ;
     RECT  2.867 3.504 3.593 5.736 ;
     RECT  2.704 61.632 3.593 61.656 ;
     RECT  3.377 44.448 3.629 44.472 ;
     RECT  2.704 49.776 3.629 49.8 ;
     RECT  3.557 63.792 3.665 63.816 ;
     RECT  3.521 22.56 3.683 23.304 ;
     RECT  3.449 35.424 3.701 36.744 ;
     RECT  3.683 22.56 3.734 22.824 ;
     RECT  2.704 66.48 3.737 67.272 ;
     RECT  2.704 45.552 3.769 45.576 ;
     RECT  3.769 45.552 3.805 46.152 ;
     RECT  3.449 24.864 3.827 27.912 ;
     RECT  3.701 35.808 3.841 36.744 ;
     RECT  3.827 24.912 3.917 27.912 ;
     RECT  2.704 30.24 3.917 31.368 ;
     RECT  3.593 5.328 3.949 5.736 ;
     RECT  2.704 8.256 3.949 8.28 ;
     RECT  3.737 66.48 3.949 66.504 ;
     RECT  2.704 42.576 3.98 42.6 ;
     RECT  3.557 54.768 3.985 54.792 ;
     RECT  3.734 22.56 3.989 22.776 ;
     RECT  3.98 41.808 4.021 42.6 ;
     RECT  3.593 3.504 4.025 4.296 ;
     RECT  4.021 41.568 4.067 42.6 ;
     RECT  3.985 54.192 4.097 54.792 ;
     RECT  3.443 20.208 4.117 21.096 ;
     RECT  3.053 38.736 4.117 38.76 ;
     RECT  2.704 40.464 4.117 40.488 ;
     RECT  3.805 12.72 4.129 12.744 ;
     RECT  2.704 59.712 4.129 60.408 ;
     RECT  4.117 19.92 4.133 21.096 ;
     RECT  4.117 38.736 4.163 40.488 ;
     RECT  3.449 56.4 4.165 56.424 ;
     RECT  2.704 9.744 4.169 10.104 ;
     RECT  4.097 54.192 4.169 54.6 ;
     RECT  4.163 38.736 4.204 39.624 ;
     RECT  3.805 45.312 4.205 46.152 ;
     RECT  4.165 56.4 4.211 56.52 ;
     RECT  4.204 38.736 4.213 39.384 ;
     RECT  4.129 59.568 4.249 60.408 ;
     RECT  4.133 19.92 4.309 20.616 ;
     RECT  3.985 49.488 4.381 49.512 ;
     RECT  3.949 5.328 4.385 6.552 ;
     RECT  3.917 24.912 4.385 26.136 ;
     RECT  3.949 8.256 4.417 8.328 ;
     RECT  4.213 38.736 4.421 39.24 ;
     RECT  4.381 49.008 4.421 49.512 ;
     RECT  3.949 65.52 4.421 66.504 ;
     RECT  2.704 32.736 4.489 32.76 ;
     RECT  4.169 54.288 4.529 54.6 ;
     RECT  3.841 35.808 4.547 37.608 ;
     RECT  2.819 14.304 4.549 15.096 ;
     RECT  4.309 61.584 4.561 61.608 ;
     RECT  4.249 59.568 4.595 59.592 ;
     RECT  4.417 7.68 4.597 8.328 ;
     RECT  4.129 11.856 4.597 12.744 ;
     RECT  4.597 11.424 4.601 12.744 ;
     RECT  4.601 11.424 4.637 11.976 ;
     RECT  4.169 9.744 4.669 9.768 ;
     RECT  4.205 45.312 4.669 45.624 ;
     RECT  4.637 11.424 4.681 11.688 ;
     RECT  4.309 19.344 4.709 20.616 ;
     RECT  3.341 29.088 4.781 29.112 ;
     RECT  4.709 19.344 4.813 19.368 ;
     RECT  4.385 6.144 4.835 6.552 ;
     RECT  3.917 30.24 4.835 31.128 ;
     RECT  4.813 18.768 4.925 19.368 ;
     RECT  4.529 54.576 4.961 54.6 ;
     RECT  4.561 60.624 4.961 61.608 ;
     RECT  4.789 5.088 4.988 5.112 ;
     RECT  4.925 18.768 4.997 18.84 ;
     RECT  4.549 57.552 4.997 57.576 ;
     RECT  4.501 47.856 5.029 47.88 ;
     RECT  4.421 49.008 5.029 49.032 ;
     RECT  4.547 35.808 5.033 36.744 ;
     RECT  3.989 22.56 5.057 22.632 ;
     RECT  4.835 30.816 5.065 31.128 ;
     RECT  4.489 32.736 5.065 33.624 ;
     RECT  4.669 9.696 5.069 9.768 ;
     RECT  5.029 47.856 5.069 49.032 ;
     RECT  5.069 9.696 5.075 9.72 ;
     RECT  5.069 47.856 5.077 48.936 ;
     RECT  4.025 3.504 5.101 3.576 ;
     RECT  4.597 7.68 5.101 8.712 ;
     RECT  4.385 25.44 5.105 26.136 ;
     RECT  5.065 30.816 5.105 33.624 ;
     RECT  4.835 6.144 5.123 6.168 ;
     RECT  5.077 47.568 5.133 48.936 ;
     RECT  5.057 22.56 5.137 23.4 ;
     RECT  5.137 22.464 5.141 23.4 ;
     RECT  4.067 42.576 5.177 42.6 ;
     RECT  4.921 58.752 5.177 58.776 ;
     RECT  5.101 3.408 5.209 3.576 ;
     RECT  4.988 4.8 5.209 5.112 ;
     RECT  3.917 27.888 5.209 27.912 ;
     RECT  4.421 65.52 5.389 65.544 ;
     RECT  4.669 44.976 5.413 45.624 ;
     RECT  4.961 61.584 5.429 61.608 ;
     RECT  5.413 44.976 5.459 46.248 ;
     RECT  2.905 16.512 5.461 16.536 ;
     RECT  5.101 7.296 5.533 8.712 ;
     RECT  5.105 31.824 5.557 33.624 ;
     RECT  4.709 20.592 5.605 20.616 ;
     RECT  5.141 22.464 5.605 22.824 ;
     RECT  4.421 39.216 5.605 39.24 ;
     RECT  4.549 14.208 5.641 15.096 ;
     RECT  5.033 36.048 5.641 36.744 ;
     RECT  4.777 37.872 5.641 37.896 ;
     RECT  4.067 41.568 5.641 41.592 ;
     RECT  5.605 22.224 5.645 22.824 ;
     RECT  4.813 13.104 5.677 13.128 ;
     RECT  5.641 14.208 5.677 15.192 ;
     RECT  5.557 31.824 5.699 33.72 ;
     RECT  5.209 3.408 5.701 5.112 ;
     RECT  5.641 36.048 5.701 37.896 ;
     RECT  5.461 16.32 5.713 16.536 ;
     RECT  5.209 27.888 5.713 28.008 ;
     RECT  5.641 41.568 5.725 42.264 ;
     RECT  5.701 2.832 5.747 5.112 ;
     RECT  5.533 7.296 5.747 9.24 ;
     RECT  5.701 36.048 5.747 38.136 ;
     RECT  5.133 47.568 5.749 47.592 ;
     RECT  5.677 13.104 5.797 15.192 ;
     RECT  5.713 27.888 5.813 28.344 ;
     RECT  5.747 2.832 5.825 3.528 ;
     RECT  5.747 7.632 5.825 9.24 ;
     RECT  5.605 20.592 5.845 21 ;
     RECT  4.741 43.68 5.845 43.704 ;
     RECT  5.845 20.112 5.857 21 ;
     RECT  5.699 31.824 5.861 33.624 ;
     RECT  5.459 44.976 5.861 45.048 ;
     RECT  5.861 45.024 5.891 45.048 ;
     RECT  5.845 43.68 5.897 43.944 ;
     RECT  5.133 48.672 5.897 48.936 ;
     RECT  5.897 43.92 5.932 43.944 ;
     RECT  5.653 23.904 5.933 23.928 ;
     RECT  5.747 36.048 5.933 36.744 ;
     RECT  5.897 48.672 5.933 48.84 ;
     RECT  5.813 27.888 5.939 28.536 ;
     RECT  5.939 27.888 5.965 28.008 ;
     RECT  4.211 56.496 5.965 56.52 ;
     RECT  5.389 64.848 5.965 65.544 ;
     RECT  5.825 8.208 5.969 9.24 ;
     RECT  5.105 25.68 6.001 26.136 ;
     RECT  5.965 27.408 6.001 28.008 ;
     RECT  5.459 46.08 6.001 46.248 ;
     RECT  5.749 47.328 6.001 47.592 ;
     RECT  5.857 20.112 6.037 21.192 ;
     RECT  5.645 22.224 6.037 22.488 ;
     RECT  5.965 64.704 6.037 65.544 ;
     RECT  5.929 58.608 6.041 58.632 ;
     RECT  4.681 11.664 6.073 11.688 ;
     RECT  5.797 13.056 6.073 15.192 ;
     RECT  5.747 4.656 6.109 5.112 ;
     RECT  6.037 64.032 6.109 65.544 ;
     RECT  6.073 11.664 6.113 15.192 ;
     RECT  6.001 25.68 6.113 28.008 ;
     RECT  4.633 34.752 6.113 34.776 ;
     RECT  6.001 29.232 6.149 29.688 ;
     RECT  5.747 37.872 6.149 38.136 ;
     RECT  6.109 4.656 6.181 5.304 ;
     RECT  6.149 38.112 6.181 38.136 ;
     RECT  6.109 64.032 6.217 66.216 ;
     RECT  5.245 67.824 6.217 67.848 ;
     RECT  5.825 3.408 6.221 3.528 ;
     RECT  6.181 38.112 6.221 38.232 ;
     RECT  6.221 3.504 6.257 3.528 ;
     RECT  5.105 30.816 6.284 30.84 ;
     RECT  5.861 32.736 6.293 33.624 ;
     RECT  6.001 46.08 6.323 47.592 ;
     RECT  6.113 12.528 6.325 15.192 ;
     RECT  5.713 16.32 6.325 17.16 ;
     RECT  4.997 18.816 6.325 18.84 ;
     RECT  6.284 30.72 6.325 30.84 ;
     RECT  6.217 63.6 6.325 66.216 ;
     RECT  6.181 50.832 6.329 50.856 ;
     RECT  6.181 4.656 6.361 6.264 ;
     RECT  6.217 67.824 6.361 68.232 ;
     RECT  6.113 25.68 6.373 27.432 ;
     RECT  6.361 67.824 6.428 68.856 ;
     RECT  6.325 12.528 6.437 18.84 ;
     RECT  5.933 36.048 6.437 36.456 ;
     RECT  6.323 46.08 6.437 46.104 ;
     RECT  5.725 41.568 6.473 42.216 ;
     RECT  6.325 63.024 6.509 66.216 ;
     RECT  6.428 67.488 6.515 68.856 ;
     RECT  6.325 30.72 6.545 31.368 ;
     RECT  6.221 38.208 6.577 38.232 ;
     RECT  5.605 39.216 6.577 39.912 ;
     RECT  6.577 38.208 6.581 39.912 ;
     RECT  6.437 15.984 6.613 18.84 ;
     RECT  6.037 20.112 6.613 22.488 ;
     RECT  6.581 38.784 6.617 39.912 ;
     RECT  6.373 26.112 6.689 27.432 ;
     RECT  6.437 12.528 6.761 14.904 ;
     RECT  5.969 8.208 6.793 8.712 ;
     RECT  6.361 4.656 6.829 6.456 ;
     RECT  6.793 8.016 6.829 8.712 ;
     RECT  6.545 30.72 6.829 31.224 ;
     RECT  5.965 56.448 6.833 56.52 ;
     RECT  6.793 24.192 6.865 24.216 ;
     RECT  5.933 48.816 6.908 48.84 ;
     RECT  6.323 47.328 6.949 47.592 ;
     RECT  6.908 48.816 6.949 49.224 ;
     RECT  6.613 15.984 6.956 22.488 ;
     RECT  6.509 63.024 6.973 66.168 ;
     RECT  6.761 12.528 7.117 14.76 ;
     RECT  6.829 4.656 7.141 8.712 ;
     RECT  6.421 9.744 7.141 9.768 ;
     RECT  6.956 15.984 7.153 22.632 ;
     RECT  6.473 42.192 7.153 42.216 ;
     RECT  7.141 4.656 7.264 9.768 ;
     RECT  6.865 24.192 7.285 25.128 ;
     RECT  7.196 61.536 7.369 61.56 ;
     RECT  6.973 62.736 7.369 66.168 ;
     RECT  7.189 3.36 7.405 3.384 ;
     RECT  7.264 4.656 7.441 9.816 ;
     RECT  7.153 15.984 7.477 22.776 ;
     RECT  7.045 52.56 7.477 52.584 ;
     RECT  6.293 32.736 7.513 32.76 ;
     RECT  7.369 33.744 7.513 33.768 ;
     RECT  7.369 61.536 7.513 66.168 ;
     RECT  6.515 67.824 7.513 68.856 ;
     RECT  7.285 24.048 7.525 25.128 ;
     RECT  7.513 32.736 7.549 33.768 ;
     RECT  7.441 4.416 7.573 9.816 ;
     RECT  6.949 47.328 7.58 49.224 ;
     RECT  7.405 3.36 7.621 3.432 ;
     RECT  7.573 4.416 7.621 10.296 ;
     RECT  7.189 44.976 7.621 45 ;
     RECT  7.58 46.464 7.621 49.224 ;
     RECT  6.833 56.496 7.669 56.52 ;
     RECT  6.721 57.552 7.669 57.576 ;
     RECT  7.621 59.28 7.669 59.304 ;
     RECT  7.477 52.56 7.693 52.728 ;
     RECT  7.621 3.312 7.729 10.296 ;
     RECT  7.117 11.664 7.729 14.76 ;
     RECT  7.189 37.056 7.765 37.08 ;
     RECT  7.729 3.312 7.808 14.76 ;
     RECT  7.477 15.984 7.808 22.824 ;
     RECT  7.525 24 7.808 25.128 ;
     RECT  6.689 26.112 7.808 26.808 ;
     RECT  6.149 29.232 7.808 29.256 ;
     RECT  6.829 30.24 7.808 31.224 ;
     RECT  7.549 32.736 7.808 33.912 ;
     RECT  6.437 36.048 7.808 36.072 ;
     RECT  7.765 37.056 7.808 37.656 ;
     RECT  6.617 38.784 7.808 39.24 ;
     RECT  6.757 40.416 7.808 40.44 ;
     RECT  7.153 42.192 7.808 42.888 ;
     RECT  7.513 43.872 7.808 43.896 ;
     RECT  7.621 44.976 7.808 49.224 ;
     RECT  7.693 52.56 7.808 52.776 ;
     RECT  7.657 54.096 7.808 54.12 ;
     RECT  7.669 56.496 7.808 57.72 ;
     RECT  7.669 59.28 7.808 59.496 ;
     RECT  7.513 61.536 7.808 68.856 ;
     RECT  7.808 2.148 7.912 69.132 ;
     RECT  7.912 2.208 8.104 68.862 ;
     RECT  8.104 13.008 8.165 22.776 ;
     RECT  8.104 60.768 8.243 65.544 ;
     RECT  8.104 2.208 8.435 11.976 ;
     RECT  8.104 42.768 8.435 45.72 ;
     RECT  8.104 24.192 8.453 24.216 ;
     RECT  8.435 43.008 8.561 45.72 ;
     RECT  8.243 60.768 8.561 63.144 ;
     RECT  8.104 51.216 8.597 52.728 ;
     RECT  8.435 4.656 8.633 11.976 ;
     RECT  8.104 29.184 8.705 29.256 ;
     RECT  8.104 47.568 8.705 48.984 ;
     RECT  8.705 48.96 8.741 48.984 ;
     RECT  8.165 17.952 8.849 22.776 ;
     RECT  8.104 27.744 8.921 27.768 ;
     RECT  8.737 0.528 8.953 0.552 ;
     RECT  8.561 43.872 8.963 45.72 ;
     RECT  8.104 66.624 9.013 68.862 ;
     RECT  8.953 0.528 9.059 1.176 ;
     RECT  8.104 39.216 9.097 39.24 ;
     RECT  8.849 21.936 9.157 22.776 ;
     RECT  9.125 23.76 9.157 23.784 ;
     RECT  9.125 34.848 9.157 34.872 ;
     RECT  8.633 4.8 9.169 11.976 ;
     RECT  8.165 13.008 9.169 16.68 ;
     RECT  8.104 32.736 9.203 33.048 ;
     RECT  9.157 21.936 9.209 23.784 ;
     RECT  9.157 34.752 9.209 34.872 ;
     RECT  8.597 52.368 9.209 52.728 ;
     RECT  8.243 64.32 9.209 65.544 ;
     RECT  9.209 64.32 9.251 64.344 ;
     RECT  8.849 17.952 9.308 20.904 ;
     RECT  9.059 0.528 9.347 0.648 ;
     RECT  8.963 43.872 9.353 43.896 ;
     RECT  8.597 51.216 9.353 51.24 ;
     RECT  9.308 17.856 9.395 20.904 ;
     RECT  9.395 17.856 9.461 20.616 ;
     RECT  8.104 55.008 9.493 55.032 ;
     RECT  9.209 21.936 9.497 23.592 ;
     RECT  9.347 0.528 9.589 0.552 ;
     RECT  9.209 65.376 9.589 65.544 ;
     RECT  9.013 66.624 9.589 69 ;
     RECT  8.561 61.92 9.601 63.144 ;
     RECT  8.435 2.208 9.637 3.672 ;
     RECT  9.493 54.672 9.637 55.032 ;
     RECT  8.104 56.064 9.637 56.52 ;
     RECT  9.601 61.776 9.637 63.144 ;
     RECT  9.589 65.376 9.637 69 ;
     RECT  9.169 4.8 9.673 16.68 ;
     RECT  9.673 4.8 9.683 17.4 ;
     RECT  9.637 54.672 9.683 56.52 ;
     RECT  9.601 27.888 9.685 27.912 ;
     RECT  8.561 60.768 9.685 60.792 ;
     RECT  9.637 61.776 9.685 63.912 ;
     RECT  8.705 29.184 9.724 29.208 ;
     RECT  9.637 2.208 9.733 3.72 ;
     RECT  9.683 4.8 9.733 15.528 ;
     RECT  9.589 0.192 9.779 0.552 ;
     RECT  9.637 65.376 9.779 69.576 ;
     RECT  9.733 2.208 9.781 15.528 ;
     RECT  9.683 55.392 9.785 55.416 ;
     RECT  9.637 58.128 9.785 58.152 ;
     RECT  9.313 59.232 9.785 59.256 ;
     RECT  9.685 60.768 9.785 63.912 ;
     RECT  9.089 70.704 9.817 70.728 ;
     RECT  9.817 70.08 9.889 70.728 ;
     RECT  8.705 47.568 9.912 47.928 ;
     RECT  9.889 70.08 9.923 70.776 ;
     RECT  9.781 1.728 9.971 15.528 ;
     RECT  9.683 16.512 9.971 17.4 ;
     RECT  9.971 16.56 10.037 17.4 ;
     RECT  10.037 16.56 10.109 17.064 ;
     RECT  8.963 45.696 10.172 45.72 ;
     RECT  9.097 39.216 10.181 39.912 ;
     RECT  9.785 60.816 10.213 63.912 ;
     RECT  10.172 45.552 10.259 45.72 ;
     RECT  8.104 31.2 10.289 31.224 ;
     RECT  9.779 0.192 10.355 0.216 ;
     RECT  10.249 24.528 10.357 24.552 ;
     RECT  10.259 45.696 10.361 45.72 ;
     RECT  9.961 53.712 10.397 54.072 ;
     RECT  8.104 37.632 10.405 37.656 ;
     RECT  10.181 39.216 10.405 39.24 ;
     RECT  10.397 54 10.433 54.072 ;
     RECT  10.405 37.632 10.451 39.24 ;
     RECT  10.357 24.528 10.469 25.032 ;
     RECT  10.451 38.4 10.492 39.24 ;
     RECT  9.673 50.592 10.573 50.616 ;
     RECT  9.497 21.936 10.597 23.304 ;
     RECT  10.469 24.528 10.597 24.552 ;
     RECT  10.213 60.816 10.613 64.392 ;
     RECT  10.597 21.936 10.643 24.552 ;
     RECT  9.971 2.832 10.649 15.528 ;
     RECT  10.643 21.936 10.685 23.928 ;
     RECT  10.685 21.936 10.709 23.304 ;
     RECT  9.209 34.752 10.717 34.776 ;
     RECT  9.683 56.496 10.717 56.52 ;
     RECT  9.209 52.368 10.753 52.44 ;
     RECT  10.709 21.648 10.757 23.304 ;
     RECT  9.779 65.376 10.757 68.952 ;
     RECT  10.613 63.552 10.789 64.392 ;
     RECT  10.757 65.376 10.789 65.544 ;
     RECT  9.461 18.48 10.793 20.616 ;
     RECT  10.757 21.648 10.793 23.112 ;
     RECT  10.433 54.048 10.825 54.072 ;
     RECT  9.912 47.184 10.837 47.928 ;
     RECT  10.793 21.936 10.865 23.112 ;
     RECT  10.681 58.704 10.865 58.728 ;
     RECT  10.837 47.184 10.883 48.408 ;
     RECT  10.757 66.528 10.885 68.952 ;
     RECT  10.883 47.184 10.94 47.352 ;
     RECT  10.613 60.816 10.94 62.184 ;
     RECT  9.971 1.728 10.969 1.752 ;
     RECT  10.649 2.832 10.969 11.352 ;
     RECT  10.825 54.048 10.97 54.792 ;
     RECT  10.94 60.72 10.973 62.184 ;
     RECT  10.789 63.552 10.973 65.544 ;
     RECT  10.573 50.592 11.005 50.856 ;
     RECT  10.753 51.84 11.005 52.44 ;
     RECT  10.885 66.528 11.017 69 ;
     RECT  10.94 47.088 11.027 47.352 ;
     RECT  10.973 60.72 11.027 60.744 ;
     RECT  10.933 26.88 11.041 26.904 ;
     RECT  11.041 26.736 11.081 26.904 ;
     RECT  11.005 50.592 11.123 52.44 ;
     RECT  9.923 70.704 11.141 70.776 ;
     RECT  10.109 16.56 11.149 16.68 ;
     RECT  9.421 42.384 11.149 42.408 ;
     RECT  11.081 26.736 11.153 26.76 ;
     RECT  10.793 20.592 11.171 20.616 ;
     RECT  11.149 42.192 11.18 42.408 ;
     RECT  11.123 51.84 11.219 52.44 ;
     RECT  11.219 51.888 11.221 52.44 ;
     RECT  11.141 60.432 11.225 60.456 ;
     RECT  11.141 70.08 11.225 70.776 ;
     RECT  11.123 50.592 11.261 50.808 ;
     RECT  11.18 42.192 11.267 42.648 ;
     RECT  11.221 51.888 11.324 52.488 ;
     RECT  10.649 12.528 11.329 15.528 ;
     RECT  11.149 16.512 11.329 16.68 ;
     RECT  10.717 34.464 11.329 34.776 ;
     RECT  8.104 36.048 11.329 36.072 ;
     RECT  11.261 50.784 11.333 50.808 ;
     RECT  11.324 51.888 11.365 52.68 ;
     RECT  11.017 66.624 11.369 69 ;
     RECT  10.969 1.728 11.411 11.352 ;
     RECT  11.329 34.464 11.441 36.072 ;
     RECT  10.492 39.216 11.473 39.24 ;
     RECT  11.225 70.704 11.513 70.776 ;
     RECT  10.973 63.552 11.549 64.968 ;
     RECT  10.973 61.728 11.581 62.184 ;
     RECT  11.473 38.64 11.585 39.24 ;
     RECT  10.865 22.176 11.603 22.488 ;
     RECT  11.411 3.936 11.621 11.352 ;
     RECT  11.549 64.416 11.693 64.968 ;
     RECT  11.617 30.912 11.729 30.936 ;
     RECT  11.513 70.704 11.729 70.728 ;
     RECT  11.621 4.128 11.797 11.352 ;
     RECT  11.329 12.528 11.797 16.68 ;
     RECT  11.365 51.888 11.797 52.968 ;
     RECT  10.97 54.048 11.797 54.744 ;
     RECT  11.585 38.736 11.801 39.24 ;
     RECT  11.221 40.704 11.869 40.728 ;
     RECT  11.267 42.192 11.869 42.216 ;
     RECT  11.761 25.008 11.873 25.032 ;
     RECT  11.797 4.128 11.891 16.68 ;
     RECT  11.411 1.728 11.939 2.904 ;
     RECT  11.369 66.624 11.945 68.472 ;
     RECT  11.891 12.528 11.989 16.68 ;
     RECT  11.401 0.576 12.037 0.6 ;
     RECT  11.797 51.888 12.049 54.744 ;
     RECT  10.717 56.208 12.049 56.52 ;
     RECT  12.037 0.192 12.121 0.6 ;
     RECT  11.939 1.728 12.121 1.752 ;
     RECT  10.793 18.48 12.121 19.416 ;
     RECT  12.049 51.888 12.169 56.52 ;
     RECT  12.121 0.192 12.227 1.752 ;
     RECT  11.945 66.624 12.229 68.376 ;
     RECT  11.989 12.528 12.236 16.776 ;
     RECT  12.169 54.384 12.265 56.52 ;
     RECT  12.229 66.288 12.301 68.376 ;
     RECT  11.801 39.216 12.428 39.24 ;
     RECT  11.869 40.704 12.428 42.216 ;
     RECT  12.121 18.24 12.445 19.416 ;
     RECT  11.581 61.728 12.445 63.144 ;
     RECT  10.897 58.128 12.517 58.152 ;
     RECT  10.883 48.384 12.661 48.408 ;
     RECT  12.625 64.32 12.697 64.344 ;
     RECT  12.301 65.424 12.697 68.376 ;
     RECT  11.891 4.128 12.725 11.448 ;
     RECT  12.697 64.32 12.805 68.376 ;
     RECT  9.203 32.736 12.841 32.76 ;
     RECT  11.939 2.832 12.901 2.904 ;
     RECT  12.725 3.984 12.901 11.448 ;
     RECT  12.445 60.96 12.901 63.144 ;
     RECT  12.805 64.128 12.901 68.376 ;
     RECT  12.265 54.384 12.913 56.568 ;
     RECT  12.517 57.552 12.913 58.152 ;
     RECT  12.227 0.192 12.917 0.552 ;
     RECT  12.227 1.728 12.985 1.752 ;
     RECT  12.901 2.832 12.985 11.448 ;
     RECT  12.985 1.728 13.057 11.448 ;
     RECT  12.236 12.528 13.057 17.112 ;
     RECT  11.441 34.752 13.093 36.072 ;
     RECT  13.021 37.056 13.093 37.08 ;
     RECT  11.027 47.328 13.165 47.352 ;
     RECT  12.661 48.384 13.165 48.456 ;
     RECT  13.057 1.728 13.208 17.112 ;
     RECT  12.445 18.144 13.208 19.416 ;
     RECT  11.603 22.464 13.208 22.488 ;
     RECT  13.057 24.672 13.208 24.696 ;
     RECT  13.129 27.12 13.208 27.144 ;
     RECT  12.841 32.736 13.208 33.672 ;
     RECT  13.093 34.752 13.208 37.176 ;
     RECT  12.428 39.216 13.208 42.216 ;
     RECT  12.805 43.824 13.208 43.848 ;
     RECT  12.517 45.936 13.208 45.96 ;
     RECT  13.165 47.328 13.208 48.456 ;
     RECT  12.169 51.888 13.208 53.352 ;
     RECT  12.913 54.384 13.208 58.152 ;
     RECT  13.021 59.808 13.208 59.832 ;
     RECT  12.901 60.96 13.208 68.376 ;
     RECT  13.208 1.728 13.312 69.132 ;
     RECT  13.312 1.728 13.504 68.862 ;
     RECT  13.504 30.816 13.565 36.072 ;
     RECT  13.504 47.28 13.645 48.456 ;
     RECT  12.917 0.192 13.667 0.264 ;
     RECT  13.504 59.04 13.667 61.608 ;
     RECT  13.565 34.32 13.673 36.072 ;
     RECT  13.504 1.728 13.709 20.184 ;
     RECT  13.709 2.16 13.745 20.184 ;
     RECT  13.504 56.832 13.745 57.624 ;
     RECT  13.745 2.688 13.753 20.184 ;
     RECT  13.504 52.272 13.781 53.352 ;
     RECT  13.504 64.656 13.889 68.136 ;
     RECT  13.889 67.824 13.997 68.136 ;
     RECT  13.997 67.824 14.033 67.848 ;
     RECT  13.504 62.688 14.105 63.624 ;
     RECT  13.753 2.688 14.141 18.264 ;
     RECT  13.645 47.76 14.141 48.456 ;
     RECT  13.504 27.312 14.149 27.624 ;
     RECT  13.889 64.656 14.177 66.312 ;
     RECT  13.565 30.816 14.213 33.048 ;
     RECT  13.504 43.824 14.285 44.712 ;
     RECT  13.745 56.832 14.285 57.432 ;
     RECT  13.667 0.24 14.321 0.264 ;
     RECT  14.213 32.736 14.321 33.048 ;
     RECT  14.177 64.656 14.321 66.12 ;
     RECT  14.141 2.688 14.393 16.536 ;
     RECT  14.393 12.336 14.429 16.536 ;
     RECT  14.429 12.336 14.465 12.36 ;
     RECT  14.213 30.816 14.465 31.272 ;
     RECT  13.667 59.04 14.485 59.064 ;
     RECT  13.504 39.216 14.531 39.24 ;
     RECT  13.504 40.944 14.537 41.64 ;
     RECT  14.285 43.872 14.713 44.712 ;
     RECT  13.753 19.248 14.753 20.184 ;
     RECT  13.667 60.528 14.773 61.608 ;
     RECT  14.285 56.832 14.785 56.904 ;
     RECT  14.393 2.688 14.819 11.304 ;
     RECT  14.773 60.528 14.819 62.184 ;
     RECT  13.504 37.056 14.821 37.08 ;
     RECT  14.785 49.584 14.821 49.608 ;
     RECT  14.141 47.76 14.825 48.408 ;
     RECT  14.141 18.24 14.857 18.264 ;
     RECT  14.753 19.248 14.857 19.416 ;
     RECT  13.673 34.32 14.867 35.976 ;
     RECT  14.821 37.056 14.893 37.32 ;
     RECT  14.819 62.16 14.897 62.184 ;
     RECT  14.321 32.976 14.908 33.048 ;
     RECT  14.429 13.632 14.933 16.536 ;
     RECT  14.713 43.872 14.933 44.952 ;
     RECT  14.465 31.248 14.969 31.272 ;
     RECT  13.781 52.272 15.001 53.016 ;
     RECT  14.893 37.056 15.005 37.368 ;
     RECT  14.933 43.872 15.005 43.896 ;
     RECT  14.821 49.584 15.005 49.704 ;
     RECT  14.537 40.944 15.037 41.592 ;
     RECT  14.893 20.4 15.077 20.424 ;
     RECT  14.485 58.656 15.221 59.064 ;
     RECT  14.819 2.688 15.253 9.144 ;
     RECT  14.321 65.376 15.325 66.12 ;
     RECT  15.253 2.256 15.349 9.144 ;
     RECT  14.819 60.528 15.361 61.176 ;
     RECT  15.361 60.384 15.401 61.176 ;
     RECT  14.819 10.224 15.437 11.304 ;
     RECT  14.933 13.632 15.437 14.52 ;
     RECT  14.713 30 15.437 30.024 ;
     RECT  13.504 22.464 15.469 22.488 ;
     RECT  15.217 55.248 15.505 55.272 ;
     RECT  14.933 44.928 15.509 44.952 ;
     RECT  15.005 37.104 15.541 37.368 ;
     RECT  15.505 54.672 15.545 55.272 ;
     RECT  14.785 56.736 15.545 56.904 ;
     RECT  14.105 63.6 15.649 63.624 ;
     RECT  15.469 22.464 15.653 22.92 ;
     RECT  15.005 49.584 15.689 49.608 ;
     RECT  15.037 40.464 15.829 41.592 ;
     RECT  15.829 40.464 15.833 42.6 ;
     RECT  15.545 54.672 15.869 54.696 ;
     RECT  15.001 51.936 15.901 53.016 ;
     RECT  14.933 15.6 15.925 16.536 ;
     RECT  14.857 18.24 15.925 19.416 ;
     RECT  15.649 63.6 15.925 64.2 ;
     RECT  15.325 65.376 15.925 66.648 ;
     RECT  15.925 63.6 15.971 66.648 ;
     RECT  15.349 2.208 15.98 9.144 ;
     RECT  15.437 10.992 16.009 11.304 ;
     RECT  15.401 60.384 16.009 60.408 ;
     RECT  15.971 63.84 16.012 66.648 ;
     RECT  14.149 27.6 16.013 27.624 ;
     RECT  15.833 40.704 16.013 42.6 ;
     RECT  16.012 63.84 16.013 64.2 ;
     RECT  16.012 65.52 16.013 66.648 ;
     RECT  16.013 42.576 16.019 42.6 ;
     RECT  15.145 46.176 16.019 46.2 ;
     RECT  15.98 2.208 16.049 9.96 ;
     RECT  14.867 34.464 16.049 35.976 ;
     RECT  16.049 2.256 16.067 9.96 ;
     RECT  15.541 37.104 16.117 37.416 ;
     RECT  16.067 2.256 16.157 9.72 ;
     RECT  15.925 15.6 16.157 19.416 ;
     RECT  16.009 59.856 16.157 60.408 ;
     RECT  16.157 2.256 16.163 6.12 ;
     RECT  15.901 51.648 16.193 53.016 ;
     RECT  16.157 59.856 16.259 59.88 ;
     RECT  16.163 2.784 16.301 6.12 ;
     RECT  16.157 7.2 16.301 9.72 ;
     RECT  16.157 15.6 16.301 16.536 ;
     RECT  15.577 58.128 16.333 58.584 ;
     RECT  14.825 47.856 16.337 48.408 ;
     RECT  15.932 44.784 16.357 44.808 ;
     RECT  16.316 45.936 16.403 45.96 ;
     RECT  15.973 62.064 16.405 62.088 ;
     RECT  16.013 65.952 16.409 66.648 ;
     RECT  16.301 8.448 16.445 9.72 ;
     RECT  16.013 40.704 16.445 41.112 ;
     RECT  16.301 15.6 16.451 15.624 ;
     RECT  16.009 10.992 16.46 11.976 ;
     RECT  16.081 30.096 16.481 30.12 ;
     RECT  15.437 13.632 16.501 14.472 ;
     RECT  16.46 10.992 16.508 12.552 ;
     RECT  16.501 13.632 16.508 15.048 ;
     RECT  16.301 7.2 16.517 7.224 ;
     RECT  16.508 10.992 16.547 15.048 ;
     RECT  14.908 32.976 16.549 33 ;
     RECT  16.547 13.056 16.595 15.048 ;
     RECT  15.545 56.736 16.604 56.808 ;
     RECT  16.604 55.824 16.645 56.808 ;
     RECT  16.645 55.824 16.691 56.856 ;
     RECT  16.357 44.448 16.697 44.808 ;
     RECT  16.621 42.672 16.729 42.696 ;
     RECT  16.445 8.448 16.732 8.472 ;
     RECT  16.301 3.408 16.841 6.12 ;
     RECT  16.729 42.672 16.877 42.744 ;
     RECT  16.691 56.352 16.909 56.856 ;
     RECT  16.333 58.128 16.913 58.728 ;
     RECT  16.405 61.584 16.945 62.088 ;
     RECT  16.877 42.672 16.949 42.696 ;
     RECT  16.913 58.128 16.949 58.152 ;
     RECT  16.049 34.8 16.981 35.976 ;
     RECT  16.117 37.056 16.981 37.416 ;
     RECT  16.945 61.536 17.029 62.088 ;
     RECT  17.009 67.728 17.029 67.752 ;
     RECT  16.445 40.8 17.053 41.112 ;
     RECT  16.801 44.928 17.057 44.952 ;
     RECT  16.445 9.696 17.093 9.72 ;
     RECT  16.409 65.952 17.161 65.976 ;
     RECT  17.029 67.728 17.161 68.664 ;
     RECT  17.197 50.736 17.221 50.76 ;
     RECT  16.013 64.176 17.237 64.2 ;
     RECT  17.221 50.112 17.281 50.76 ;
     RECT  16.157 18.24 17.305 19.416 ;
     RECT  16.549 32.208 17.305 33 ;
     RECT  17.281 50.112 17.309 50.136 ;
     RECT  16.909 56.352 17.356 57.048 ;
     RECT  16.981 34.8 17.372 37.416 ;
     RECT  16.337 48.384 17.413 48.408 ;
     RECT  17.029 62.064 17.453 62.088 ;
     RECT  16.621 59.76 17.485 59.784 ;
     RECT  16.547 10.992 17.489 11.976 ;
     RECT  17.269 16.8 17.629 16.824 ;
     RECT  15.653 22.464 17.629 22.488 ;
     RECT  17.269 39.168 17.66 39.192 ;
     RECT  17.372 34.512 17.701 37.416 ;
     RECT  17.66 38.544 17.701 39.192 ;
     RECT  17.305 31.872 17.773 33 ;
     RECT  17.485 24.96 17.989 24.984 ;
     RECT  17.881 26.832 18.053 26.856 ;
     RECT  17.989 24.48 18.092 24.984 ;
     RECT  18.053 26.736 18.092 26.856 ;
     RECT  16.595 13.632 18.169 15.048 ;
     RECT  17.305 2.304 18.197 2.328 ;
     RECT  17.917 8.496 18.205 8.52 ;
     RECT  17.305 18.24 18.229 19.56 ;
     RECT  17.489 10.992 18.236 11.304 ;
     RECT  17.161 65.568 18.241 65.976 ;
     RECT  17.629 22.464 18.277 22.824 ;
     RECT  18.092 24.48 18.277 26.856 ;
     RECT  16.841 3.648 18.325 6.12 ;
     RECT  17.701 34.464 18.325 39.384 ;
     RECT  17.701 45.744 18.325 45.768 ;
     RECT  17.413 47.856 18.325 48.408 ;
     RECT  18.277 22.464 18.341 26.856 ;
     RECT  17.737 27.888 18.341 27.912 ;
     RECT  18.277 7.2 18.385 7.224 ;
     RECT  16.193 52.176 18.428 53.016 ;
     RECT  18.169 13.632 18.469 15.48 ;
     RECT  17.629 16.512 18.469 16.824 ;
     RECT  18.325 45.648 18.469 45.768 ;
     RECT  18.413 46.752 18.469 46.776 ;
     RECT  18.14 61.2 18.493 61.224 ;
     RECT  18.325 3.504 18.565 6.12 ;
     RECT  18.385 7.2 18.565 7.368 ;
     RECT  18.469 13.632 18.565 16.824 ;
     RECT  17.269 55.296 18.565 55.32 ;
     RECT  18.241 43.632 18.601 43.656 ;
     RECT  18.197 2.256 18.608 2.328 ;
     RECT  18.565 3.504 18.608 7.368 ;
     RECT  18.205 8.448 18.608 8.52 ;
     RECT  18.236 10.32 18.608 11.304 ;
     RECT  18.565 12.864 18.608 16.824 ;
     RECT  18.229 18.24 18.608 20.376 ;
     RECT  18.341 22.464 18.608 27.912 ;
     RECT  17.773 30.816 18.608 33 ;
     RECT  18.325 34.128 18.608 39.384 ;
     RECT  17.053 40.8 18.608 42.6 ;
     RECT  18.601 43.632 18.608 44.376 ;
     RECT  18.469 45.648 18.608 46.776 ;
     RECT  18.325 47.856 18.608 48.504 ;
     RECT  17.521 49.584 18.608 49.608 ;
     RECT  18.428 51.552 18.608 53.016 ;
     RECT  17.653 54 18.608 54.024 ;
     RECT  18.565 55.152 18.608 55.32 ;
     RECT  17.356 56.832 18.608 57.048 ;
     RECT  18.565 58.128 18.608 58.152 ;
     RECT  17.485 59.472 18.608 59.784 ;
     RECT  18.493 61.2 18.608 61.416 ;
     RECT  18.181 62.736 18.608 62.76 ;
     RECT  18.241 65.136 18.608 65.976 ;
     RECT  17.161 67.296 18.608 68.664 ;
     RECT  18.608 2.148 18.712 69.132 ;
     RECT  18.712 2.304 18.904 68.862 ;
     RECT  18.904 24.96 18.929 26.184 ;
     RECT  18.904 47.616 18.929 50.136 ;
     RECT  18.904 36.048 18.965 37.176 ;
     RECT  18.965 36.048 19.001 36.264 ;
     RECT  18.904 18.24 19.037 19.656 ;
     RECT  18.904 21.024 19.043 23.88 ;
     RECT  18.904 30.24 19.073 33.24 ;
     RECT  18.904 61.392 19.109 62.424 ;
     RECT  18.929 48.816 19.181 50.136 ;
     RECT  18.904 52.176 19.181 55.176 ;
     RECT  18.904 34.32 19.217 34.488 ;
     RECT  18.904 2.304 19.289 7.368 ;
     RECT  18.904 10.944 19.289 16.824 ;
     RECT  18.929 25.632 19.372 26.184 ;
     RECT  18.929 47.616 19.433 47.64 ;
     RECT  18.904 65.136 19.433 66.744 ;
     RECT  19.109 61.536 19.475 62.424 ;
     RECT  19.475 62.16 19.516 62.424 ;
     RECT  19.372 25.632 19.541 25.656 ;
     RECT  19.043 21.984 19.613 23.88 ;
     RECT  19.073 30.24 19.613 31.368 ;
     RECT  19.433 66.528 19.715 66.744 ;
     RECT  19.289 10.944 19.757 15.384 ;
     RECT  19.757 14.4 19.829 15.384 ;
     RECT  18.904 56.208 19.829 58.68 ;
     RECT  18.904 43.824 19.859 44.376 ;
     RECT  18.904 41.568 19.865 42.744 ;
     RECT  19.829 57.552 19.868 58.68 ;
     RECT  18.904 59.76 19.868 59.784 ;
     RECT  19.037 19.632 19.897 19.656 ;
     RECT  18.904 63.792 19.897 63.816 ;
     RECT  18.904 67.92 19.897 68.664 ;
     RECT  18.904 9.6 19.901 9.816 ;
     RECT  19.868 57.552 19.901 59.784 ;
     RECT  18.904 27.888 19.909 27.912 ;
     RECT  18.904 29.04 19.909 29.064 ;
     RECT  19.073 32.448 19.909 33.24 ;
     RECT  19.217 34.32 19.909 34.344 ;
     RECT  19.901 57.792 19.909 59.784 ;
     RECT  19.289 2.88 19.916 7.368 ;
     RECT  18.904 45.6 19.933 46.248 ;
     RECT  19.909 32.448 19.955 34.344 ;
     RECT  19.829 56.208 19.955 56.232 ;
     RECT  19.909 57.792 19.955 60.456 ;
     RECT  19.865 41.568 19.973 41.592 ;
     RECT  19.916 2.88 20.003 7.416 ;
     RECT  18.904 8.448 20.005 8.52 ;
     RECT  19.955 32.976 20.045 34.344 ;
     RECT  19.933 45.12 20.053 46.248 ;
     RECT  19.757 10.944 20.077 13.272 ;
     RECT  20.077 10.896 20.081 13.272 ;
     RECT  20.053 45.12 20.14 46.488 ;
     RECT  20.053 47.76 20.14 47.784 ;
     RECT  20.113 26.688 20.185 26.712 ;
     RECT  19.909 27.888 20.252 29.064 ;
     RECT  19.613 30.24 20.252 30.264 ;
     RECT  19.181 48.816 20.252 49.848 ;
     RECT  19.613 31.344 20.261 31.368 ;
     RECT  19.955 57.792 20.261 58.68 ;
     RECT  20.252 51.264 20.293 51.288 ;
     RECT  19.181 52.272 20.293 55.176 ;
     RECT  20.252 27.888 20.297 30.264 ;
     RECT  19.897 67.776 20.297 68.664 ;
     RECT  19.829 14.448 20.329 15.384 ;
     RECT  19.289 16.8 20.329 16.824 ;
     RECT  18.904 38.736 20.329 38.76 ;
     RECT  20.297 29.616 20.339 30.264 ;
     RECT  20.045 32.976 20.339 33.24 ;
     RECT  20.252 48.816 20.339 50.136 ;
     RECT  20.293 51.264 20.339 55.176 ;
     RECT  20.339 49.344 20.369 49.848 ;
     RECT  20.14 45.12 20.483 46.248 ;
     RECT  19.897 63.792 20.485 64.056 ;
     RECT  19.433 65.136 20.485 65.544 ;
     RECT  20.329 38.736 20.531 39.384 ;
     RECT  20.485 63.792 20.531 65.544 ;
     RECT  19.037 18.24 20.549 18.648 ;
     RECT  19.516 62.16 20.585 62.184 ;
     RECT  20.081 10.896 20.621 12.552 ;
     RECT  20.339 51.888 20.621 55.176 ;
     RECT  20.185 26.688 20.689 26.76 ;
     RECT  20.339 30.24 20.693 30.264 ;
     RECT  20.621 53.376 20.693 55.176 ;
     RECT  20.005 8.448 20.729 9.144 ;
     RECT  20.689 26.592 20.761 26.76 ;
     RECT  20.531 63.792 20.833 64.392 ;
     RECT  19.613 23.856 20.837 23.88 ;
     RECT  20.729 8.448 20.873 8.472 ;
     RECT  20.761 26.592 20.873 26.856 ;
     RECT  20.693 53.76 20.905 55.176 ;
     RECT  20.003 2.88 20.909 7.272 ;
     RECT  20.873 26.688 20.909 26.76 ;
     RECT  20.045 34.32 20.909 34.344 ;
     RECT  19.955 60.432 20.945 60.456 ;
     RECT  19.865 42.672 21.013 42.696 ;
     RECT  20.329 14.448 21.049 16.824 ;
     RECT  19.715 66.72 21.085 66.744 ;
     RECT  19.897 19.632 21.109 20.568 ;
     RECT  20.369 49.344 21.125 49.368 ;
     RECT  20.621 51.888 21.125 52.296 ;
     RECT  20.833 63.216 21.125 64.392 ;
     RECT  20.297 67.776 21.125 67.992 ;
     RECT  21.068 34.608 21.155 34.632 ;
     RECT  21.085 66.096 21.155 66.744 ;
     RECT  20.297 27.888 21.161 27.912 ;
     RECT  21.109 19.344 21.196 20.568 ;
     RECT  19.001 36.048 21.233 36.072 ;
     RECT  21.196 19.632 21.269 20.568 ;
     RECT  20.909 26.688 21.269 26.712 ;
     RECT  21.125 63.216 21.269 64.152 ;
     RECT  21.049 13.92 21.377 16.824 ;
     RECT  21.125 67.824 21.377 67.992 ;
     RECT  20.621 10.944 21.413 12.552 ;
     RECT  21.413 12.24 21.449 12.552 ;
     RECT  19.859 43.824 21.481 43.848 ;
     RECT  20.483 45.264 21.481 46.248 ;
     RECT  20.261 57.792 21.521 58.632 ;
     RECT  20.545 31.92 21.557 31.944 ;
     RECT  21.013 42.24 21.589 42.696 ;
     RECT  21.481 43.824 21.589 46.248 ;
     RECT  20.905 53.76 21.593 55.56 ;
     RECT  20.941 25.104 21.625 25.128 ;
     RECT  21.589 27.936 21.625 27.96 ;
     RECT  20.617 61.632 21.625 61.656 ;
     RECT  21.269 20.448 21.629 20.568 ;
     RECT  21.625 25.104 21.665 25.656 ;
     RECT  20.549 18.24 21.697 18.264 ;
     RECT  20.909 2.976 21.733 7.272 ;
     RECT  21.413 10.944 21.733 11.208 ;
     RECT  21.589 42.24 21.773 46.248 ;
     RECT  21.637 37.584 21.809 37.608 ;
     RECT  19.613 21.984 21.949 22.824 ;
     RECT  21.377 15.936 21.985 16.824 ;
     RECT  21.697 18.144 21.985 18.264 ;
     RECT  20.339 33.216 21.985 33.24 ;
     RECT  21.521 58.608 22.057 58.632 ;
     RECT  21.269 63.36 22.133 64.152 ;
     RECT  21.733 2.976 22.165 8.184 ;
     RECT  21.985 32.304 22.205 33.24 ;
     RECT  22.165 2.976 22.211 9.144 ;
     RECT  20.185 40.848 22.309 41.016 ;
     RECT  21.125 52.272 22.309 52.296 ;
     RECT  21.593 53.76 22.309 54.696 ;
     RECT  21.985 15.936 22.313 18.264 ;
     RECT  21.265 30.576 22.345 30.6 ;
     RECT  21.377 67.968 22.345 67.992 ;
     RECT  22.211 2.976 22.357 6.12 ;
     RECT  21.949 21.12 22.357 22.824 ;
     RECT  21.949 23.952 22.357 23.976 ;
     RECT  21.773 42.24 22.381 43.032 ;
     RECT  21.625 61.536 22.412 61.656 ;
     RECT  22.057 58.608 22.417 58.68 ;
     RECT  22.133 63.36 22.417 63.816 ;
     RECT  22.357 21.12 22.421 23.976 ;
     RECT  22.421 23.328 22.444 23.976 ;
     RECT  20.531 38.736 22.453 38.76 ;
     RECT  22.309 40.128 22.453 41.016 ;
     RECT  22.309 52.272 22.453 54.696 ;
     RECT  21.733 10.128 22.489 11.208 ;
     RECT  21.449 12.384 22.489 12.552 ;
     RECT  21.155 66.096 22.489 66.12 ;
     RECT  22.211 9.12 22.493 9.144 ;
     RECT  22.453 38.736 22.493 41.016 ;
     RECT  22.412 60.96 22.499 61.656 ;
     RECT  22.313 15.936 22.565 17.112 ;
     RECT  22.417 58.608 22.604 59.496 ;
     RECT  22.165 26.832 22.633 26.856 ;
     RECT  22.493 38.736 22.643 40.152 ;
     RECT  22.604 57.984 22.645 59.496 ;
     RECT  21.773 44.304 22.669 46.248 ;
     RECT  22.453 51.888 22.669 54.696 ;
     RECT  22.489 10.128 22.693 12.552 ;
     RECT  22.489 34.8 22.777 34.824 ;
     RECT  22.705 48.912 22.777 48.936 ;
     RECT  22.693 10.128 22.781 12.936 ;
     RECT  22.645 57.456 22.781 59.496 ;
     RECT  21.377 13.92 22.789 14.904 ;
     RECT  22.565 15.936 22.789 16.008 ;
     RECT  21.625 27.936 22.789 28.536 ;
     RECT  22.669 51.888 22.789 55.368 ;
     RECT  22.213 64.896 22.789 64.92 ;
     RECT  22.489 66.096 22.789 66.504 ;
     RECT  22.789 13.92 22.813 16.008 ;
     RECT  22.789 51.888 22.813 56.232 ;
     RECT  22.499 61.536 22.817 61.656 ;
     RECT  21.805 50.16 22.837 50.184 ;
     RECT  22.781 10.128 22.845 12.552 ;
     RECT  22.345 30.288 22.849 30.6 ;
     RECT  22.669 44.304 22.861 46.488 ;
     RECT  22.813 51.744 22.861 56.232 ;
     RECT  22.789 64.896 22.876 66.504 ;
     RECT  22.565 17.088 22.889 17.112 ;
     RECT  22.421 21.12 22.925 22.008 ;
     RECT  22.789 27.936 22.925 29.208 ;
     RECT  22.381 42.144 22.933 43.032 ;
     RECT  22.933 41.664 22.957 43.032 ;
     RECT  22.861 44.304 22.957 46.248 ;
     RECT  22.211 7.584 22.961 7.608 ;
     RECT  22.957 41.664 22.979 46.248 ;
     RECT  22.837 50.16 22.979 50.712 ;
     RECT  22.205 32.304 22.993 32.472 ;
     RECT  22.925 29.184 23.029 29.208 ;
     RECT  22.849 30.288 23.029 30.84 ;
     RECT  22.345 67.536 23.029 67.992 ;
     RECT  22.781 57.456 23.033 57.576 ;
     RECT  23.029 67.536 23.101 68.088 ;
     RECT  23.101 67.536 23.173 68.328 ;
     RECT  22.633 26.784 23.209 26.856 ;
     RECT  22.417 63.264 23.245 63.816 ;
     RECT  22.876 64.896 23.245 65.352 ;
     RECT  22.309 36.288 23.281 36.312 ;
     RECT  22.705 37.536 23.281 37.56 ;
     RECT  22.345 47.52 23.324 47.544 ;
     RECT  22.777 48.912 23.324 49.032 ;
     RECT  23.209 26.64 23.353 26.856 ;
     RECT  22.925 27.936 23.353 28.2 ;
     RECT  22.861 51.744 23.353 54.696 ;
     RECT  22.444 23.376 23.42 23.976 ;
     RECT  23.245 63.264 23.423 65.352 ;
     RECT  23.42 23.376 23.425 24.504 ;
     RECT  22.781 58.608 23.425 59.496 ;
     RECT  23.425 22.512 23.461 24.504 ;
     RECT  23.324 47.52 23.533 49.032 ;
     RECT  22.979 50.16 23.533 50.184 ;
     RECT  23.281 36.288 23.569 37.56 ;
     RECT  22.817 61.536 23.641 61.56 ;
     RECT  22.861 56.064 23.677 56.232 ;
     RECT  23.033 57.456 23.677 57.48 ;
     RECT  22.813 13.824 23.749 16.008 ;
     RECT  22.643 40.128 23.749 40.152 ;
     RECT  22.979 41.664 23.749 41.688 ;
     RECT  23.423 62.832 23.857 65.352 ;
     RECT  22.876 66.48 23.857 66.504 ;
     RECT  23.461 22.512 23.965 24.648 ;
     RECT  21.665 25.632 23.965 25.656 ;
     RECT  22.357 2.832 24.008 6.12 ;
     RECT  22.845 10.128 24.008 12.504 ;
     RECT  23.749 13.824 24.008 16.44 ;
     RECT  22.313 18.144 24.008 18.264 ;
     RECT  22.921 19.536 24.008 19.56 ;
     RECT  22.925 21.12 24.008 21.144 ;
     RECT  23.965 22.512 24.008 25.656 ;
     RECT  23.353 26.64 24.008 28.2 ;
     RECT  23.029 29.184 24.008 30.84 ;
     RECT  22.993 31.92 24.008 32.472 ;
     RECT  22.777 33.6 24.008 34.824 ;
     RECT  23.569 36 24.008 37.56 ;
     RECT  22.643 38.736 24.008 38.808 ;
     RECT  23.749 40.128 24.008 41.688 ;
     RECT  22.979 43.392 24.008 46.248 ;
     RECT  23.533 47.52 24.008 50.184 ;
     RECT  23.353 51.648 24.008 54.696 ;
     RECT  23.677 56.064 24.008 57.48 ;
     RECT  23.425 58.608 24.008 59.784 ;
     RECT  23.641 61.392 24.008 61.56 ;
     RECT  23.857 62.832 24.008 66.504 ;
     RECT  23.173 67.536 24.008 68.424 ;
     RECT  24.008 2.148 24.112 69.132 ;
     RECT  24.112 2.418 24.304 68.862 ;
     RECT  24.304 63.504 24.329 65.064 ;
     RECT  24.304 41.376 24.365 41.688 ;
     RECT  24.304 18.144 24.401 25.272 ;
     RECT  24.304 9.024 24.419 17.112 ;
     RECT  24.401 18.144 24.46 22.296 ;
     RECT  24.304 60.96 24.611 62.184 ;
     RECT  24.329 63.504 24.617 63.864 ;
     RECT  24.304 67.68 24.653 68.424 ;
     RECT  24.401 23.376 24.797 25.272 ;
     RECT  24.304 51.744 24.803 53.784 ;
     RECT  24.419 9.504 24.905 17.112 ;
     RECT  24.803 51.744 24.905 53.064 ;
     RECT  24.304 59.76 24.905 59.784 ;
     RECT  24.304 42.672 24.941 44.376 ;
     RECT  24.653 67.68 24.941 68.376 ;
     RECT  24.304 35.856 25.013 36.216 ;
     RECT  24.905 9.504 25.049 14.952 ;
     RECT  24.304 38.784 25.121 40.152 ;
     RECT  24.797 23.376 25.157 23.928 ;
     RECT  24.941 43.392 25.157 44.376 ;
     RECT  24.304 26.352 25.193 27.192 ;
     RECT  25.049 9.504 25.229 12.264 ;
     RECT  25.049 13.392 25.235 14.952 ;
     RECT  24.304 30.816 25.292 34.776 ;
     RECT  24.304 28.416 25.333 29.064 ;
     RECT  25.292 30.288 25.379 34.776 ;
     RECT  24.304 56.496 25.405 56.52 ;
     RECT  25.379 30.96 25.409 34.776 ;
     RECT  24.46 18.144 25.441 22.248 ;
     RECT  25.157 23.376 25.441 23.4 ;
     RECT  24.304 46.416 25.441 46.44 ;
     RECT  25.409 32.304 25.445 34.776 ;
     RECT  24.365 41.376 25.445 41.544 ;
     RECT  25.157 43.392 25.445 44.28 ;
     RECT  25.405 56.352 25.477 56.52 ;
     RECT  25.441 18.144 25.481 23.4 ;
     RECT  25.333 28.416 25.513 29.304 ;
     RECT  25.481 18.144 25.517 21.432 ;
     RECT  24.611 61.92 25.517 62.184 ;
     RECT  24.329 64.848 25.58 65.064 ;
     RECT  24.304 48.672 25.585 48.696 ;
     RECT  24.304 2.832 25.619 6.12 ;
     RECT  25.013 36.192 25.621 36.216 ;
     RECT  24.617 63.504 25.621 63.816 ;
     RECT  24.941 67.68 25.657 67.848 ;
     RECT  25.58 64.8 25.667 65.064 ;
     RECT  24.304 45.36 25.717 45.384 ;
     RECT  24.304 57.552 25.724 57.576 ;
     RECT  24.304 49.872 25.765 50.712 ;
     RECT  25.724 57.552 25.765 58.008 ;
     RECT  25.517 18.24 25.769 21.432 ;
     RECT  25.193 26.88 25.769 27.192 ;
     RECT  25.717 45.312 25.804 45.384 ;
     RECT  25.769 27.168 25.805 27.192 ;
     RECT  25.621 62.736 25.805 63.816 ;
     RECT  25.765 57.552 25.811 58.728 ;
     RECT  25.804 45.36 25.82 45.384 ;
     RECT  25.441 46.416 25.82 46.776 ;
     RECT  25.477 55.824 25.861 56.52 ;
     RECT  25.811 57.552 25.861 57.576 ;
     RECT  25.121 39.216 25.873 40.152 ;
     RECT  25.868 38.16 25.955 38.184 ;
     RECT  25.805 62.736 26.057 63.768 ;
     RECT  25.657 67.104 26.089 67.848 ;
     RECT  26.089 67.104 26.129 68.376 ;
     RECT  25.621 36.192 26.197 37.176 ;
     RECT  25.513 28.416 26.273 29.4 ;
     RECT  25.445 43.392 26.309 43.416 ;
     RECT  25.861 55.824 26.339 57.576 ;
     RECT  24.797 25.008 26.377 25.272 ;
     RECT  25.667 64.848 26.377 65.064 ;
     RECT  25.445 32.448 26.387 34.776 ;
     RECT  26.387 32.448 26.428 34.248 ;
     RECT  25.481 22.464 26.437 23.4 ;
     RECT  26.437 22.464 26.483 23.544 ;
     RECT  26.377 24.624 26.483 25.272 ;
     RECT  25.229 10.32 26.485 12.264 ;
     RECT  25.235 13.392 26.485 14.712 ;
     RECT  25.585 47.856 26.485 48.696 ;
     RECT  25.765 49.872 26.485 50.76 ;
     RECT  26.339 55.824 26.485 57.048 ;
     RECT  26.413 27.888 26.497 27.912 ;
     RECT  25.873 39.216 26.521 40.584 ;
     RECT  25.619 2.832 26.525 6.024 ;
     RECT  26.483 23.28 26.525 23.544 ;
     RECT  26.485 55.68 26.525 57.048 ;
     RECT  26.485 10.32 26.561 14.712 ;
     RECT  25.409 30.96 26.665 31.32 ;
     RECT  26.428 32.448 26.665 33.192 ;
     RECT  26.561 10.32 26.705 13.464 ;
     RECT  26.483 25.104 26.725 25.272 ;
     RECT  25.769 20.88 26.737 21.432 ;
     RECT  26.197 36.192 26.737 37.56 ;
     RECT  26.485 47.856 26.737 50.76 ;
     RECT  24.905 51.744 26.737 52.296 ;
     RECT  26.725 25.104 26.771 25.704 ;
     RECT  24.905 15.984 26.773 16.92 ;
     RECT  26.737 20.832 26.773 21.432 ;
     RECT  26.521 38.736 26.773 40.584 ;
     RECT  25.909 41.952 26.773 41.976 ;
     RECT  26.273 28.944 26.813 29.4 ;
     RECT  26.737 35.232 26.813 37.56 ;
     RECT  25.82 45.36 26.813 46.776 ;
     RECT  26.377 64.848 26.876 65.544 ;
     RECT  26.129 67.104 26.876 67.128 ;
     RECT  25.693 8.4 26.877 8.424 ;
     RECT  26.813 37.536 26.885 37.56 ;
     RECT  26.773 15.984 26.917 17.064 ;
     RECT  25.769 18.24 26.917 19.176 ;
     RECT  26.773 26.784 26.917 26.808 ;
     RECT  26.525 55.68 26.917 56.808 ;
     RECT  26.665 30.96 26.921 33.192 ;
     RECT  26.057 63.504 26.921 63.768 ;
     RECT  26.917 55.056 26.953 56.808 ;
     RECT  26.876 64.848 26.963 67.128 ;
     RECT  26.921 30.96 26.989 30.984 ;
     RECT  26.525 2.88 27.029 6.024 ;
     RECT  26.813 28.944 27.065 28.968 ;
     RECT  26.921 63.504 27.065 63.528 ;
     RECT  26.813 45.984 27.169 46.776 ;
     RECT  26.737 47.856 27.169 52.296 ;
     RECT  26.989 30.864 27.173 30.984 ;
     RECT  26.665 53.568 27.212 53.592 ;
     RECT  26.963 64.848 27.251 65.544 ;
     RECT  26.773 38.736 27.253 41.976 ;
     RECT  27.169 45.984 27.253 52.296 ;
     RECT  27.212 53.568 27.253 53.784 ;
     RECT  26.953 54.96 27.253 56.808 ;
     RECT  26.813 35.232 27.299 36.408 ;
     RECT  27.253 45.984 27.299 56.808 ;
     RECT  26.771 25.248 27.301 25.704 ;
     RECT  26.917 26.784 27.301 26.904 ;
     RECT  27.253 37.824 27.317 41.976 ;
     RECT  26.561 14.448 27.349 14.712 ;
     RECT  26.917 15.984 27.349 19.176 ;
     RECT  26.525 23.28 27.353 23.4 ;
     RECT  24.304 7.2 27.389 7.224 ;
     RECT  27.301 25.248 27.389 26.904 ;
     RECT  27.173 30.864 27.413 30.888 ;
     RECT  27.299 35.232 27.443 36.312 ;
     RECT  26.773 20.16 27.457 21.432 ;
     RECT  27.317 37.824 27.497 38.472 ;
     RECT  25.811 58.704 27.565 58.728 ;
     RECT  26.881 60.672 27.565 60.696 ;
     RECT  27.317 39.552 27.569 41.976 ;
     RECT  27.565 58.704 27.641 59.256 ;
     RECT  26.428 34.176 27.673 34.248 ;
     RECT  26.921 32.16 27.713 33.192 ;
     RECT  27.299 47.28 27.713 53.016 ;
     RECT  26.705 13.056 27.74 13.464 ;
     RECT  27.349 14.448 27.74 19.176 ;
     RECT  26.129 68.352 27.745 68.376 ;
     RECT  27.061 44.976 27.781 45 ;
     RECT  27.299 45.984 27.781 46.008 ;
     RECT  27.299 54.384 27.821 56.808 ;
     RECT  27.74 13.056 27.827 19.176 ;
     RECT  27.251 64.848 27.857 65.16 ;
     RECT  26.705 10.32 27.877 11.352 ;
     RECT  27.853 43.584 27.889 43.608 ;
     RECT  27.457 20.16 27.925 21.672 ;
     RECT  27.565 60.672 27.925 61.512 ;
     RECT  26.963 66.72 27.925 67.128 ;
     RECT  27.745 68.256 27.925 68.376 ;
     RECT  27.497 37.824 27.961 38.328 ;
     RECT  27.569 40.992 27.961 41.976 ;
     RECT  27.713 47.28 27.965 50.76 ;
     RECT  27.925 66.72 27.965 68.376 ;
     RECT  27.925 20.16 27.971 21.72 ;
     RECT  27.925 60.672 27.971 62.184 ;
     RECT  27.827 14.448 27.997 19.176 ;
     RECT  27.971 20.16 27.997 20.376 ;
     RECT  27.713 32.448 27.997 33.192 ;
     RECT  27.673 34.176 27.997 34.296 ;
     RECT  27.277 28.752 28.001 28.776 ;
     RECT  27.961 40.992 28.037 42.12 ;
     RECT  27.029 2.88 28.069 5.88 ;
     RECT  27.421 7.008 28.069 7.032 ;
     RECT  27.529 22.8 28.073 22.824 ;
     RECT  27.965 66.72 28.076 66.744 ;
     RECT  27.389 25.872 28.105 26.904 ;
     RECT  28.076 66.576 28.163 66.744 ;
     RECT  28.105 25.872 28.213 27.624 ;
     RECT  28.069 2.88 28.253 7.032 ;
     RECT  28.213 25.872 28.253 27.912 ;
     RECT  27.971 21.408 28.289 21.72 ;
     RECT  27.971 62.16 28.361 62.184 ;
     RECT  27.781 44.976 28.393 46.008 ;
     RECT  27.997 14.448 28.397 20.376 ;
     RECT  27.413 30.72 28.429 30.888 ;
     RECT  27.641 59.232 28.453 59.256 ;
     RECT  27.971 60.672 28.453 60.696 ;
     RECT  27.443 35.328 28.465 36.312 ;
     RECT  27.961 37.488 28.465 38.328 ;
     RECT  27.827 13.056 28.501 13.08 ;
     RECT  28.393 44.976 28.645 46.2 ;
     RECT  27.965 47.28 28.645 50.28 ;
     RECT  27.569 39.552 28.825 39.768 ;
     RECT  27.889 43.584 28.825 43.944 ;
     RECT  28.501 12.528 28.897 13.08 ;
     RECT  28.177 28.896 28.933 28.92 ;
     RECT  28.429 30.048 28.933 30.888 ;
     RECT  28.465 35.328 28.933 38.328 ;
     RECT  27.997 32.448 28.969 34.296 ;
     RECT  28.163 66.72 28.969 66.744 ;
     RECT  28.645 44.976 28.981 50.28 ;
     RECT  28.037 41.712 29.005 42.12 ;
     RECT  29.005 41.712 29.041 42.216 ;
     RECT  28.253 2.88 29.077 5.448 ;
     RECT  28.933 28.896 29.077 30.888 ;
     RECT  28.969 32.352 29.077 34.296 ;
     RECT  28.969 66.72 29.125 66.792 ;
     RECT  27.821 54.384 29.141 54.984 ;
     RECT  27.529 8.496 29.185 8.52 ;
     RECT  27.877 9.744 29.185 11.352 ;
     RECT  29.041 41.616 29.185 42.216 ;
     RECT  28.825 43.344 29.185 43.944 ;
     RECT  28.981 44.976 29.185 50.712 ;
     RECT  27.713 51.744 29.185 53.016 ;
     RECT  27.853 58.224 29.221 58.248 ;
     RECT  28.453 59.232 29.221 60.696 ;
     RECT  28.253 6.816 29.269 7.032 ;
     RECT  29.185 8.496 29.269 11.352 ;
     RECT  28.753 62.448 29.269 62.472 ;
     RECT  28.501 63.504 29.269 63.528 ;
     RECT  29.185 41.616 29.293 43.944 ;
     RECT  29.141 54.384 29.293 55.32 ;
     RECT  29.077 2.832 29.408 5.448 ;
     RECT  29.269 6.816 29.408 11.352 ;
     RECT  28.897 12.528 29.408 13.416 ;
     RECT  28.397 14.448 29.408 14.952 ;
     RECT  28.397 15.984 29.408 20.376 ;
     RECT  28.289 21.408 29.408 21.672 ;
     RECT  27.997 24.624 29.408 24.648 ;
     RECT  28.253 25.92 29.408 27.912 ;
     RECT  29.077 28.896 29.408 34.296 ;
     RECT  28.933 35.328 29.408 38.424 ;
     RECT  28.825 39.408 29.408 39.768 ;
     RECT  29.293 40.848 29.408 43.944 ;
     RECT  29.185 44.976 29.408 53.016 ;
     RECT  29.293 54.096 29.408 55.32 ;
     RECT  27.821 56.304 29.408 56.808 ;
     RECT  29.221 58.224 29.408 60.696 ;
     RECT  29.269 62.448 29.408 63.528 ;
     RECT  27.857 64.848 29.408 64.872 ;
     RECT  29.125 66.096 29.408 66.792 ;
     RECT  27.965 67.776 29.408 68.376 ;
     RECT  29.408 2.148 29.512 69.132 ;
     RECT  29.512 2.418 29.704 68.862 ;
     RECT  29.704 2.832 29.801 5.304 ;
     RECT  29.704 58.224 29.801 61.608 ;
     RECT  29.801 3.072 29.837 5.304 ;
     RECT  29.704 29.28 29.837 31.416 ;
     RECT  29.704 10.32 29.843 10.44 ;
     RECT  29.704 11.808 29.843 14.712 ;
     RECT  29.704 40.848 29.873 44.088 ;
     RECT  29.704 32.496 29.909 33.144 ;
     RECT  29.704 66.768 29.909 66.792 ;
     RECT  29.801 58.656 29.981 61.608 ;
     RECT  29.704 50.544 30.035 52.2 ;
     RECT  29.704 36.288 30.083 37.992 ;
     RECT  29.843 14.208 30.125 14.712 ;
     RECT  30.083 36.528 30.125 37.992 ;
     RECT  30.125 36.912 30.197 37.992 ;
     RECT  29.843 10.416 30.233 10.44 ;
     RECT  29.704 54.096 30.233 56.568 ;
     RECT  29.704 15.84 30.241 18.264 ;
     RECT  29.704 62.688 30.275 63.528 ;
     RECT  29.704 64.8 30.341 65.544 ;
     RECT  30.241 15.84 30.377 16.968 ;
     RECT  30.233 54.336 30.377 56.568 ;
     RECT  30.377 15.84 30.485 16.584 ;
     RECT  29.837 29.616 30.485 31.416 ;
     RECT  29.704 21.408 30.515 21.432 ;
     RECT  30.125 14.352 30.521 14.712 ;
     RECT  29.704 22.848 30.557 27.912 ;
     RECT  29.704 6.816 30.629 6.888 ;
     RECT  30.557 22.848 30.629 27.768 ;
     RECT  29.704 19.536 30.697 20.184 ;
     RECT  29.704 47.712 30.697 49.56 ;
     RECT  30.035 50.544 30.697 51.864 ;
     RECT  30.485 29.616 30.701 30.12 ;
     RECT  29.909 33.072 30.733 33.144 ;
     RECT  29.704 45.696 30.733 46.728 ;
     RECT  30.697 47.712 30.733 51.864 ;
     RECT  29.837 3.12 30.769 5.304 ;
     RECT  30.629 6.864 30.769 6.888 ;
     RECT  30.697 19.536 30.769 21.096 ;
     RECT  30.733 33.072 30.769 33.432 ;
     RECT  29.843 11.808 30.773 13.128 ;
     RECT  30.275 62.688 30.805 62.808 ;
     RECT  30.733 45.696 30.809 51.864 ;
     RECT  29.981 59.52 30.809 61.608 ;
     RECT  29.704 67.776 30.809 68.424 ;
     RECT  30.629 22.848 30.845 26.04 ;
     RECT  30.769 3.12 30.853 5.736 ;
     RECT  30.809 45.696 30.881 51.768 ;
     RECT  30.881 45.696 30.901 46.008 ;
     RECT  30.197 36.912 30.917 37.896 ;
     RECT  30.881 47.328 30.917 51.768 ;
     RECT  29.704 34.896 30.949 35.304 ;
     RECT  30.901 45.456 30.989 46.008 ;
     RECT  29.704 8.592 30.997 9.096 ;
     RECT  30.853 3.12 31.021 5.592 ;
     RECT  30.773 11.808 31.025 12.552 ;
     RECT  30.997 8.448 31.043 9.096 ;
     RECT  30.977 10.272 31.061 10.296 ;
     RECT  30.917 50.16 31.061 51.768 ;
     RECT  30.977 52.992 31.061 53.016 ;
     RECT  31.043 8.448 31.084 8.712 ;
     RECT  30.377 54.336 31.084 56.376 ;
     RECT  30.845 22.848 31.1 23.4 ;
     RECT  30.917 37.008 31.165 37.896 ;
     RECT  30.809 60.96 31.169 60.984 ;
     RECT  31.1 22.176 31.187 23.4 ;
     RECT  31.025 12.288 31.205 12.552 ;
     RECT  30.949 34.8 31.205 35.304 ;
     RECT  29.704 39.744 31.237 39.768 ;
     RECT  30.809 67.776 31.237 68.376 ;
     RECT  31.084 54.384 31.283 56.376 ;
     RECT  30.769 33.12 31.309 33.432 ;
     RECT  31.205 34.8 31.309 35.16 ;
     RECT  30.769 6.864 31.345 7.032 ;
     RECT  30.485 16.224 31.349 16.584 ;
     RECT  31.165 37.008 31.349 37.944 ;
     RECT  31.237 58.128 31.417 58.152 ;
     RECT  30.341 64.8 31.453 64.824 ;
     RECT  30.805 62.592 31.489 62.808 ;
     RECT  31.237 39.456 31.525 39.768 ;
     RECT  29.873 41.76 31.525 44.088 ;
     RECT  31.453 64.368 31.532 64.824 ;
     RECT  31.489 62.4 31.573 62.808 ;
     RECT  31.532 64.176 31.573 64.824 ;
     RECT  31.309 33.12 31.601 35.16 ;
     RECT  31.573 62.4 31.619 65.208 ;
     RECT  31.619 64.368 31.621 65.208 ;
     RECT  31.417 57.648 31.633 58.152 ;
     RECT  31.621 64.368 31.667 65.64 ;
     RECT  31.667 65.184 31.708 65.64 ;
     RECT  30.769 18.768 31.709 21.096 ;
     RECT  31.237 66.864 31.709 68.376 ;
     RECT  31.349 16.224 31.745 16.248 ;
     RECT  31.061 50.544 31.745 51.768 ;
     RECT  31.345 6.864 31.777 7.368 ;
     RECT  31.619 62.4 31.777 63.336 ;
     RECT  30.521 14.448 31.813 14.712 ;
     RECT  31.021 3.024 31.849 5.592 ;
     RECT  31.777 6.816 31.849 7.368 ;
     RECT  30.629 27.744 31.849 27.768 ;
     RECT  31.205 12.528 31.885 12.552 ;
     RECT  31.187 22.992 31.885 23.4 ;
     RECT  30.845 24.624 31.885 26.04 ;
     RECT  31.708 65.184 31.907 65.496 ;
     RECT  31.709 68.352 31.907 68.376 ;
     RECT  31.745 50.544 31.925 50.568 ;
     RECT  31.283 54.384 31.925 55.8 ;
     RECT  31.777 62.208 31.925 63.336 ;
     RECT  30.701 29.616 31.957 29.64 ;
     RECT  31.885 12.528 31.961 13.08 ;
     RECT  31.709 21.072 31.961 21.096 ;
     RECT  31.925 62.544 31.961 63.336 ;
     RECT  31.885 22.992 32.003 26.04 ;
     RECT  31.849 27.312 32.003 27.912 ;
     RECT  31.957 28.944 32.044 30.024 ;
     RECT  31.849 3.024 32.06 7.368 ;
     RECT  31.084 8.688 32.06 8.712 ;
     RECT  31.861 61.2 32.06 61.224 ;
     RECT  30.989 45.984 32.065 46.008 ;
     RECT  30.917 47.328 32.069 49.032 ;
     RECT  32.06 3.024 32.101 8.712 ;
     RECT  31.525 41.76 32.101 44.232 ;
     RECT  32.003 22.992 32.141 23.928 ;
     RECT  32.101 2.832 32.147 8.712 ;
     RECT  32.06 61.2 32.147 61.512 ;
     RECT  32.147 8.688 32.173 8.712 ;
     RECT  32.101 9.792 32.173 9.816 ;
     RECT  32.069 47.328 32.209 48.504 ;
     RECT  30.485 31.392 32.252 31.416 ;
     RECT  31.709 18.768 32.281 20.04 ;
     RECT  32.147 61.2 32.285 61.224 ;
     RECT  32.252 31.344 32.293 31.416 ;
     RECT  31.525 39.456 32.317 40.2 ;
     RECT  32.065 45.888 32.317 46.008 ;
     RECT  32.209 47.04 32.317 48.504 ;
     RECT  31.745 51.696 32.317 51.768 ;
     RECT  31.601 33.984 32.321 35.16 ;
     RECT  32.293 31.344 32.339 31.56 ;
     RECT  32.321 33.984 32.339 34.824 ;
     RECT  32.003 25.2 32.357 26.04 ;
     RECT  31.709 66.864 32.357 67.32 ;
     RECT  31.813 14.256 32.389 14.712 ;
     RECT  32.281 18.672 32.393 20.04 ;
     RECT  30.809 59.52 32.393 59.592 ;
     RECT  31.345 10.848 32.425 11.016 ;
     RECT  32.339 31.392 32.425 31.56 ;
     RECT  32.317 39.264 32.437 40.2 ;
     RECT  32.101 41.232 32.437 44.232 ;
     RECT  32.317 45.888 32.437 48.504 ;
     RECT  31.633 57.552 32.437 58.152 ;
     RECT  32.437 39.264 32.465 44.232 ;
     RECT  32.437 45.6 32.531 48.504 ;
     RECT  31.349 37.008 32.533 37.032 ;
     RECT  32.531 48.192 32.609 48.504 ;
     RECT  32.357 25.2 32.681 25.704 ;
     RECT  32.065 21.264 32.713 21.48 ;
     RECT  32.465 39.264 32.717 42.744 ;
     RECT  32.393 59.52 32.717 59.544 ;
     RECT  32.465 43.968 32.725 44.232 ;
     RECT  32.531 45.6 32.725 47.064 ;
     RECT  32.357 67.296 32.753 67.32 ;
     RECT  32.389 14.256 32.821 15.048 ;
     RECT  32.003 27.312 32.821 27.336 ;
     RECT  31.885 38.112 32.821 38.136 ;
     RECT  32.717 39.264 32.821 41.064 ;
     RECT  32.725 43.968 32.825 47.064 ;
     RECT  32.425 31.392 32.857 32.52 ;
     RECT  32.339 33.984 32.857 34.248 ;
     RECT  32.821 14.256 32.867 15.48 ;
     RECT  32.317 51.696 32.893 52.584 ;
     RECT  32.681 25.488 32.897 25.704 ;
     RECT  32.867 14.688 32.908 15.48 ;
     RECT  32.533 36.432 32.924 37.032 ;
     RECT  32.821 38.112 32.924 41.064 ;
     RECT  32.141 23.904 32.933 23.928 ;
     RECT  32.713 21.264 32.969 21.624 ;
     RECT  32.147 2.832 33.005 6.888 ;
     RECT  32.044 29.616 33.005 30.024 ;
     RECT  32.857 31.392 33.005 34.248 ;
     RECT  32.825 45.744 33.041 46.776 ;
     RECT  31.961 62.544 33.061 62.904 ;
     RECT  31.907 65.184 33.061 65.4 ;
     RECT  31.925 54.432 33.077 55.8 ;
     RECT  32.173 8.688 33.149 9.816 ;
     RECT  31.961 13.056 33.149 13.08 ;
     RECT  33.037 17.088 33.205 17.112 ;
     RECT  33.205 16.224 33.251 17.112 ;
     RECT  33.061 62.544 33.289 63 ;
     RECT  33.005 29.616 33.293 29.64 ;
     RECT  33.145 22.8 33.329 22.824 ;
     RECT  32.924 36.432 33.361 41.064 ;
     RECT  33.181 50.112 33.397 50.136 ;
     RECT  32.437 57.312 33.397 58.152 ;
     RECT  32.893 51.36 33.401 52.584 ;
     RECT  33.005 3.024 33.437 6.888 ;
     RECT  33.397 57.312 33.437 58.68 ;
     RECT  32.393 20.016 33.505 20.04 ;
     RECT  32.969 21.264 33.505 21.48 ;
     RECT  33.077 55.776 33.509 55.8 ;
     RECT  33.149 8.784 33.577 9.816 ;
     RECT  32.425 10.848 33.577 11.976 ;
     RECT  33.061 65.184 33.577 65.592 ;
     RECT  33.361 35.856 33.581 41.064 ;
     RECT  32.717 42.192 33.613 42.744 ;
     RECT  32.825 43.968 33.613 44.232 ;
     RECT  33.005 31.392 33.617 31.56 ;
     RECT  33.581 38.784 33.617 41.064 ;
     RECT  33.577 65.184 33.617 66.696 ;
     RECT  33.617 65.184 33.649 65.208 ;
     RECT  33.581 35.856 33.683 37.368 ;
     RECT  33.617 41.04 33.685 41.064 ;
     RECT  33.613 42.192 33.685 44.232 ;
     RECT  32.965 68.352 33.685 68.376 ;
     RECT  33.577 8.784 33.689 11.976 ;
     RECT  33.401 51.36 33.725 52.488 ;
     RECT  33.721 55.872 33.757 55.896 ;
     RECT  33.683 36.432 33.797 37.368 ;
     RECT  33.437 57.312 33.829 57.336 ;
     RECT  33.617 66.288 33.877 66.696 ;
     RECT  33.437 58.656 33.901 58.68 ;
     RECT  32.965 60.672 33.901 60.696 ;
     RECT  33.289 62.4 33.901 63 ;
     RECT  33.617 31.392 33.937 31.416 ;
     RECT  33.077 54.432 33.973 54.696 ;
     RECT  32.897 25.584 34.045 25.704 ;
     RECT  33.041 45.744 34.045 46.008 ;
     RECT  33.973 54.096 34.045 54.696 ;
     RECT  32.609 48.192 34.069 48.456 ;
     RECT  33.505 20.016 34.117 21.48 ;
     RECT  33.005 33.216 34.117 34.248 ;
     RECT  32.393 18.672 34.153 18.696 ;
     RECT  34.117 20.016 34.153 21.816 ;
     RECT  34.045 24.768 34.153 25.704 ;
     RECT  34.153 23.808 34.165 25.704 ;
     RECT  32.821 27.168 34.165 27.336 ;
     RECT  33.613 28.656 34.165 28.68 ;
     RECT  33.685 41.04 34.165 44.232 ;
     RECT  34.165 23.808 34.181 25.752 ;
     RECT  33.397 50.112 34.225 50.184 ;
     RECT  33.689 9.792 34.405 11.976 ;
     RECT  33.437 3.12 34.441 6.888 ;
     RECT  33.757 55.872 34.513 55.992 ;
     RECT  33.829 56.976 34.513 57.336 ;
     RECT  33.685 68.352 34.585 68.424 ;
     RECT  32.908 14.688 34.597 14.712 ;
     RECT  33.251 16.224 34.597 16.248 ;
     RECT  33.725 51.744 34.621 52.488 ;
     RECT  34.045 53.568 34.621 54.696 ;
     RECT  33.689 8.784 34.652 8.808 ;
     RECT  33.937 30.96 34.652 31.416 ;
     RECT  34.597 14.688 34.693 16.824 ;
     RECT  33.797 36.432 34.693 36.456 ;
     RECT  33.617 38.784 34.693 39.624 ;
     RECT  33.901 13.104 34.729 13.128 ;
     RECT  34.693 38.16 34.801 39.624 ;
     RECT  34.441 3.12 34.808 7.416 ;
     RECT  34.652 8.592 34.808 8.808 ;
     RECT  34.405 9.792 34.808 12.12 ;
     RECT  34.729 13.104 34.808 13.368 ;
     RECT  34.693 14.688 34.808 17.16 ;
     RECT  34.153 18.672 34.808 22.104 ;
     RECT  34.181 23.136 34.808 25.752 ;
     RECT  34.165 27.168 34.808 28.68 ;
     RECT  34.652 30.96 34.808 32.184 ;
     RECT  34.117 33.216 34.808 34.488 ;
     RECT  34.693 36.24 34.808 36.456 ;
     RECT  34.801 37.968 34.808 39.624 ;
     RECT  34.165 41.04 34.808 44.472 ;
     RECT  34.045 45.744 34.808 46.728 ;
     RECT  34.069 48.192 34.808 49.032 ;
     RECT  34.225 50.112 34.808 50.664 ;
     RECT  34.621 51.744 34.808 54.696 ;
     RECT  34.513 55.872 34.808 57.336 ;
     RECT  33.901 58.656 34.808 59.4 ;
     RECT  33.901 60.672 34.808 63 ;
     RECT  33.649 64.992 34.808 65.208 ;
     RECT  33.877 66.288 34.808 66.936 ;
     RECT  34.585 68.112 34.808 68.424 ;
     RECT  34.808 2.148 34.912 69.132 ;
     RECT  34.912 2.418 35.104 68.862 ;
     RECT  35.104 49.44 35.219 53.016 ;
     RECT  35.104 10.896 35.237 11.688 ;
     RECT  35.237 10.896 35.273 10.92 ;
     RECT  35.104 25.2 35.273 25.224 ;
     RECT  35.104 37.968 35.273 48.408 ;
     RECT  35.104 5.568 35.381 8.808 ;
     RECT  35.104 9.792 35.381 9.816 ;
     RECT  35.104 54.096 35.381 55.992 ;
     RECT  35.104 19.536 35.417 21.48 ;
     RECT  35.219 51.888 35.417 53.016 ;
     RECT  35.219 49.44 35.507 50.712 ;
     RECT  35.381 5.568 35.561 7.416 ;
     RECT  35.104 22.704 35.597 23.16 ;
     RECT  35.273 37.968 35.603 48.216 ;
     RECT  35.603 44.928 35.633 48.216 ;
     RECT  35.603 37.968 35.669 43.896 ;
     RECT  35.104 65.52 35.705 66.312 ;
     RECT  35.104 13.104 35.741 13.368 ;
     RECT  35.417 21.456 35.741 21.48 ;
     RECT  35.104 57.312 35.849 57.432 ;
     RECT  35.705 65.52 35.885 66.12 ;
     RECT  35.381 8.496 35.891 8.808 ;
     RECT  35.507 49.44 35.891 50.52 ;
     RECT  35.104 63.984 35.891 64.2 ;
     RECT  35.885 65.568 35.891 66.12 ;
     RECT  35.104 60.672 35.932 63 ;
     RECT  35.104 14.448 35.957 15.288 ;
     RECT  35.104 29.76 35.957 31.8 ;
     RECT  35.104 26.736 35.993 28.056 ;
     RECT  35.741 13.104 36.029 13.128 ;
     RECT  35.381 55.488 36.029 55.992 ;
     RECT  35.104 34.752 36.097 35.016 ;
     RECT  35.669 38.4 36.109 43.896 ;
     RECT  36.109 38.4 36.131 42.024 ;
     RECT  35.932 61.776 36.137 63 ;
     RECT  35.957 14.592 36.14 15.288 ;
     RECT  36.169 17.136 36.181 17.16 ;
     RECT  35.993 26.736 36.205 26.856 ;
     RECT  36.14 14.592 36.227 15.432 ;
     RECT  35.957 29.76 36.245 31.416 ;
     RECT  36.131 40.8 36.245 42.024 ;
     RECT  35.104 67.584 36.277 68.136 ;
     RECT  35.932 60.672 36.281 60.696 ;
     RECT  36.097 36.96 36.313 36.984 ;
     RECT  36.205 26.208 36.317 26.856 ;
     RECT  35.104 59.232 36.317 59.256 ;
     RECT  36.097 34.704 36.353 35.016 ;
     RECT  36.317 26.208 36.371 26.232 ;
     RECT  35.597 22.704 36.373 22.728 ;
     RECT  35.993 27.84 36.373 28.056 ;
     RECT  35.104 3.552 36.38 4.536 ;
     RECT  35.561 5.568 36.38 6.552 ;
     RECT  35.417 52.464 36.385 53.016 ;
     RECT  35.381 54.096 36.385 54.12 ;
     RECT  36.385 52.464 36.389 54.12 ;
     RECT  36.277 67.584 36.389 68.424 ;
     RECT  35.417 20.4 36.419 20.424 ;
     RECT  36.245 31.152 36.419 31.416 ;
     RECT  36.133 32.496 36.419 32.52 ;
     RECT  36.38 3.552 36.421 6.552 ;
     RECT  36.325 25.056 36.421 25.08 ;
     RECT  36.313 36.096 36.425 36.984 ;
     RECT  35.633 47.328 36.457 48.216 ;
     RECT  35.891 49.44 36.457 49.608 ;
     RECT  36.421 51.888 36.457 51.912 ;
     RECT  36.421 24.48 36.461 25.08 ;
     RECT  36.131 38.4 36.461 39.24 ;
     RECT  36.421 2.784 36.467 6.552 ;
     RECT  36.389 52.992 36.467 54.12 ;
     RECT  36.467 53.568 36.508 54.12 ;
     RECT  36.467 2.784 36.533 4.728 ;
     RECT  36.461 24.48 36.565 24.696 ;
     RECT  36.457 51.744 36.569 51.912 ;
     RECT  36.109 43.104 36.601 43.896 ;
     RECT  35.633 44.928 36.601 46.104 ;
     RECT  35.849 57.312 36.601 57.336 ;
     RECT  36.601 43.104 36.605 46.104 ;
     RECT  36.425 36.48 36.641 36.984 ;
     RECT  36.467 5.712 36.677 5.736 ;
     RECT  36.461 38.4 36.713 39.096 ;
     RECT  36.457 47.328 36.755 49.608 ;
     RECT  36.181 17.04 36.817 17.16 ;
     RECT  36.565 11.568 36.853 11.592 ;
     RECT  35.891 65.568 36.853 65.592 ;
     RECT  36.817 17.04 36.857 17.208 ;
     RECT  36.419 31.152 36.857 31.176 ;
     RECT  36.353 34.752 36.893 35.016 ;
     RECT  36.755 48.576 36.893 49.608 ;
     RECT  36.029 55.488 36.961 55.512 ;
     RECT  36.893 49.248 36.995 49.608 ;
     RECT  36.137 62.4 36.997 63 ;
     RECT  35.891 64.176 36.997 64.2 ;
     RECT  35.104 33.552 37.001 33.576 ;
     RECT  36.641 36.48 37.073 36.504 ;
     RECT  36.533 3.168 37.217 4.728 ;
     RECT  36.389 68.208 37.217 68.424 ;
     RECT  36.997 62.4 37.244 64.2 ;
     RECT  36.853 65.568 37.244 66.216 ;
     RECT  36.245 40.896 37.249 40.92 ;
     RECT  36.245 42 37.249 42.024 ;
     RECT  37.249 40.896 37.285 42.024 ;
     RECT  36.605 43.104 37.285 44.328 ;
     RECT  37.244 62.4 37.285 66.216 ;
     RECT  37.285 40.896 37.289 44.328 ;
     RECT  37.285 62.4 37.331 66.984 ;
     RECT  36.601 57.024 37.333 57.336 ;
     RECT  36.713 38.4 37.361 38.808 ;
     RECT  37.289 42.72 37.369 44.328 ;
     RECT  36.227 14.592 37.393 15.288 ;
     RECT  37.331 66.864 37.397 66.984 ;
     RECT  37.333 56.688 37.42 57.336 ;
     RECT  37.397 66.96 37.42 66.984 ;
     RECT  36.961 55.248 37.465 55.512 ;
     RECT  37.331 62.4 37.469 63 ;
     RECT  36.601 6.816 37.477 6.936 ;
     RECT  35.891 8.496 37.477 8.52 ;
     RECT  37.369 42.816 37.505 44.328 ;
     RECT  36.493 19.392 37.532 19.416 ;
     RECT  37.501 20.544 37.532 20.568 ;
     RECT  36.373 21.936 37.537 22.728 ;
     RECT  36.565 23.952 37.537 24.696 ;
     RECT  37.477 6.816 37.564 8.52 ;
     RECT  37.465 54.624 37.573 55.512 ;
     RECT  37.537 21.936 37.577 24.696 ;
     RECT  37.217 3.552 37.609 4.728 ;
     RECT  37.42 57.024 37.609 57.336 ;
     RECT  37.393 58.704 37.609 58.728 ;
     RECT  37.429 30.72 37.613 30.744 ;
     RECT  37.532 19.392 37.619 20.568 ;
     RECT  36.853 11.568 37.621 11.736 ;
     RECT  37.357 12.72 37.621 12.744 ;
     RECT  37.393 14.208 37.621 15.288 ;
     RECT  37.505 43.104 37.645 44.328 ;
     RECT  36.508 53.568 37.645 53.592 ;
     RECT  37.573 54.576 37.645 55.512 ;
     RECT  37.621 11.568 37.667 15.288 ;
     RECT  37.609 3.552 37.721 5.112 ;
     RECT  37.289 40.896 37.721 41.64 ;
     RECT  37.667 13.536 37.729 15.288 ;
     RECT  37.645 53.568 37.757 55.512 ;
     RECT  36.373 27.84 37.789 28.92 ;
     RECT  37.645 43.104 37.793 44.424 ;
     RECT  36.857 17.088 37.825 17.208 ;
     RECT  37.753 25.68 37.825 25.704 ;
     RECT  36.995 49.392 37.868 49.608 ;
     RECT  37.361 38.4 37.897 38.424 ;
     RECT  36.569 51.888 37.909 51.912 ;
     RECT  37.825 17.088 37.937 17.448 ;
     RECT  37.825 25.68 37.937 26.232 ;
     RECT  37.331 64.176 37.937 64.2 ;
     RECT  37.868 49.392 37.955 49.944 ;
     RECT  37.577 21.936 37.973 23.352 ;
     RECT  37.973 21.936 38.009 23.16 ;
     RECT  37.909 51.168 38.041 51.912 ;
     RECT  37.619 20.544 38.045 20.568 ;
     RECT  37.609 57.024 38.051 58.728 ;
     RECT  38.041 51.072 38.081 51.912 ;
     RECT  38.077 31.2 38.113 31.224 ;
     RECT  36.605 45.504 38.177 46.104 ;
     RECT  36.755 47.328 38.177 47.496 ;
     RECT  37.721 5.088 38.185 5.112 ;
     RECT  37.729 13.536 38.189 13.56 ;
     RECT  36.893 34.752 38.189 34.776 ;
     RECT  37.897 38.112 38.189 38.424 ;
     RECT  37.577 24.48 38.195 24.696 ;
     RECT  37.793 44.016 38.197 44.424 ;
     RECT  38.177 45.504 38.197 47.496 ;
     RECT  37.465 36.096 38.221 36.12 ;
     RECT  38.081 51.072 38.221 51.096 ;
     RECT  37.789 27.84 38.225 29.4 ;
     RECT  37.757 53.904 38.225 54.12 ;
     RECT  37.955 49.392 38.232 49.512 ;
     RECT  38.232 49.344 38.257 49.512 ;
     RECT  37.469 62.4 38.261 62.664 ;
     RECT  37.217 68.208 38.297 68.232 ;
     RECT  37.721 3.552 38.329 3.816 ;
     RECT  38.221 36.096 38.329 36.936 ;
     RECT  38.189 38.4 38.333 38.424 ;
     RECT  38.221 50.736 38.339 51.096 ;
     RECT  38.257 48.48 38.341 49.512 ;
     RECT  38.329 3.36 38.365 3.816 ;
     RECT  37.465 10.272 38.365 10.296 ;
     RECT  37.937 17.088 38.365 17.112 ;
     RECT  38.051 57.024 38.441 58.584 ;
     RECT  38.293 39.792 38.473 39.816 ;
     RECT  38.197 44.016 38.579 47.496 ;
     RECT  38.579 46.752 38.593 47.496 ;
     RECT  38.009 23.04 38.621 23.16 ;
     RECT  38.341 49.344 38.621 49.512 ;
     RECT  38.441 57.312 38.621 58.584 ;
     RECT  37.619 19.392 38.653 19.416 ;
     RECT  38.473 39.792 38.653 40.488 ;
     RECT  38.621 57.552 38.657 58.584 ;
     RECT  38.621 49.344 38.693 49.368 ;
     RECT  38.365 9.648 38.725 10.296 ;
     RECT  37.667 11.568 38.725 11.832 ;
     RECT  38.653 18.624 38.725 19.416 ;
     RECT  38.113 31.2 38.729 32.088 ;
     RECT  37.757 55.488 38.761 55.512 ;
     RECT  38.725 9.648 38.771 11.832 ;
     RECT  38.365 16.416 38.771 17.112 ;
     RECT  38.225 27.888 38.773 29.4 ;
     RECT  37.729 14.832 38.801 15.288 ;
     RECT  38.195 24.672 38.801 24.696 ;
     RECT  38.653 39.744 38.801 40.488 ;
     RECT  38.801 14.832 38.828 15.24 ;
     RECT  38.225 53.952 38.828 54.12 ;
     RECT  38.761 55.488 38.828 56.136 ;
     RECT  38.773 27.888 38.837 30.216 ;
     RECT  38.329 36.096 38.837 37.032 ;
     RECT  38.261 62.4 38.837 62.52 ;
     RECT  38.837 30.192 38.86 30.216 ;
     RECT  38.725 18.192 38.869 19.416 ;
     RECT  38.833 34.896 38.869 34.92 ;
     RECT  38.771 10.752 38.873 11.832 ;
     RECT  37.331 65.568 38.909 65.592 ;
     RECT  38.828 13.584 38.915 15.24 ;
     RECT  38.828 52.896 38.915 52.92 ;
     RECT  37.721 41.52 38.917 41.64 ;
     RECT  38.579 44.016 38.917 45.768 ;
     RECT  38.185 5.088 38.965 5.64 ;
     RECT  37.564 6.816 38.965 7.512 ;
     RECT  38.365 2.832 39.011 3.816 ;
     RECT  38.965 4.896 39.011 7.512 ;
     RECT  37.249 61.056 39.013 61.08 ;
     RECT  38.837 27.888 39.053 28.92 ;
     RECT  39.013 61.056 39.053 61.56 ;
     RECT  39.011 6 39.068 7.512 ;
     RECT  37.564 8.496 39.068 8.52 ;
     RECT  38.657 58.56 39.085 58.584 ;
     RECT  38.005 59.76 39.085 59.784 ;
     RECT  39.068 6 39.121 8.52 ;
     RECT  38.771 9.648 39.121 9.672 ;
     RECT  38.801 39.792 39.121 40.488 ;
     RECT  38.917 41.52 39.121 42.216 ;
     RECT  38.917 43.776 39.125 45.768 ;
     RECT  39.121 6 39.155 9.672 ;
     RECT  39.011 4.896 39.161 4.92 ;
     RECT  39.155 6 39.161 7.944 ;
     RECT  39.125 43.776 39.161 43.8 ;
     RECT  39.085 58.56 39.161 59.784 ;
     RECT  38.869 18.192 39.197 19.512 ;
     RECT  38.729 31.2 39.203 31.56 ;
     RECT  38.593 47.328 39.337 47.496 ;
     RECT  39.011 3.024 39.365 3.816 ;
     RECT  37.937 26.208 39.697 26.232 ;
     RECT  38.837 36.48 39.769 37.032 ;
     RECT  38.621 23.136 39.781 23.16 ;
     RECT  39.203 31.2 39.841 31.512 ;
     RECT  39.697 26.112 39.877 26.232 ;
     RECT  39.157 32.88 39.884 32.904 ;
     RECT  38.915 13.584 39.913 13.608 ;
     RECT  38.873 11.424 39.949 11.832 ;
     RECT  38.339 51.072 39.949 51.096 ;
     RECT  39.365 3.024 40.208 4.008 ;
     RECT  39.161 6 40.208 6.024 ;
     RECT  39.161 7.392 40.208 7.944 ;
     RECT  39.155 9.072 40.208 9.672 ;
     RECT  39.949 10.848 40.208 11.976 ;
     RECT  39.913 13.296 40.208 13.608 ;
     RECT  38.915 14.832 40.208 15.24 ;
     RECT  38.771 16.416 40.208 16.44 ;
     RECT  39.197 18.192 40.208 18.216 ;
     RECT  39.197 19.344 40.208 19.512 ;
     RECT  39.517 20.544 40.208 20.568 ;
     RECT  39.781 23.136 40.208 23.976 ;
     RECT  39.877 25.296 40.208 26.232 ;
     RECT  39.053 27.888 40.208 28.536 ;
     RECT  39.841 30.912 40.208 31.512 ;
     RECT  39.884 32.88 40.208 33.624 ;
     RECT  38.869 34.896 40.208 35.16 ;
     RECT  39.769 36.48 40.208 37.128 ;
     RECT  39.733 38.64 40.208 38.664 ;
     RECT  39.121 39.792 40.208 42.216 ;
     RECT  39.125 44.976 40.208 45.768 ;
     RECT  39.337 47.328 40.208 47.784 ;
     RECT  39.932 48.816 40.208 48.84 ;
     RECT  39.932 49.92 40.208 49.944 ;
     RECT  39.949 51.072 40.208 51.912 ;
     RECT  38.828 53.952 40.208 56.136 ;
     RECT  38.657 57.552 40.208 57.576 ;
     RECT  39.161 58.56 40.208 59.496 ;
     RECT  39.193 60.528 40.208 60.552 ;
     RECT  39.053 61.536 40.208 61.56 ;
     RECT  40.208 2.148 40.312 69.132 ;
     RECT  40.312 2.418 40.504 68.862 ;
     RECT  40.504 3.312 40.529 3.336 ;
     RECT  40.504 21.216 40.637 21.24 ;
    LAYER M5 ;
     RECT  9.024 0.144 13.512 0.181 ;
     RECT  9.024 0.181 13.656 1.187 ;
     RECT  2.4 2.137 2.52 2.151 ;
     RECT  7.8 2.137 7.92 2.151 ;
     RECT  18.6 2.137 18.72 2.151 ;
     RECT  24 2.137 24.12 2.151 ;
     RECT  29.4 2.137 29.52 2.151 ;
     RECT  34.8 2.137 34.92 2.151 ;
     RECT  40.2 2.137 40.32 2.151 ;
     RECT  15.36 2.197 15.384 2.245 ;
     RECT  18.6 2.151 18.912 2.245 ;
     RECT  9.456 1.187 13.656 2.677 ;
     RECT  15.264 2.245 16.152 2.677 ;
     RECT  7.8 2.151 8.112 2.773 ;
     RECT  9.456 2.677 14.136 2.773 ;
     RECT  29.4 2.151 29.712 2.821 ;
     RECT  40.2 2.151 40.512 3.301 ;
     RECT  7.8 2.773 14.136 3.397 ;
     RECT  15.12 2.677 16.152 3.397 ;
     RECT  29.088 2.821 29.712 3.397 ;
     RECT  24 2.151 24.312 3.445 ;
     RECT  22.368 2.821 22.392 3.539 ;
     RECT  24 3.445 25.128 3.925 ;
     RECT  34.8 2.151 35.112 3.925 ;
     RECT  38.976 2.821 39 3.925 ;
     RECT  40.08 3.301 40.512 3.925 ;
     RECT  7.8 3.397 16.152 4.019 ;
     RECT  7.8 4.019 15.672 4.115 ;
     RECT  34.176 3.925 35.112 4.451 ;
     RECT  7.8 4.115 15.336 4.691 ;
     RECT  5.712 2.821 5.736 4.789 ;
     RECT  2.4 2.151 2.712 4.837 ;
     RECT  28.944 3.397 29.712 5.029 ;
     RECT  30.816 3.157 30.84 5.029 ;
     RECT  23.376 3.925 25.128 5.075 ;
     RECT  5.04 4.789 5.736 5.077 ;
     RECT  18.24 2.245 18.912 5.077 ;
     RECT  2.4 4.837 2.856 5.125 ;
     RECT  4.8 5.077 5.736 5.173 ;
     RECT  12.72 4.691 15.336 5.317 ;
     RECT  23.904 5.075 25.128 5.459 ;
     RECT  28.944 5.029 30.84 5.459 ;
     RECT  34.32 4.451 35.112 5.459 ;
     RECT  7.8 4.691 9.96 5.653 ;
     RECT  21.072 3.925 21.096 5.699 ;
     RECT  2.4 5.125 3.432 5.747 ;
     RECT  29.4 5.459 30.84 5.747 ;
     RECT  26.304 5.509 26.328 5.749 ;
     RECT  2.4 5.747 2.856 5.795 ;
     RECT  12.72 5.317 15.96 5.795 ;
     RECT  11.28 4.691 11.736 5.797 ;
     RECT  12.72 5.795 15.384 5.797 ;
     RECT  25.584 5.749 26.328 5.845 ;
     RECT  23.904 5.459 24.504 5.891 ;
     RECT  17.28 5.077 18.912 6.037 ;
     RECT  2.4 5.795 2.712 6.229 ;
     RECT  11.28 5.797 15.384 6.229 ;
     RECT  34.8 5.459 35.112 6.229 ;
     RECT  36.432 2.773 36.456 6.229 ;
     RECT  11.232 6.229 15.384 6.323 ;
     RECT  34.8 6.229 36.456 6.563 ;
     RECT  7.44 5.653 9.96 6.757 ;
     RECT  11.232 6.323 15.192 6.757 ;
     RECT  4.8 5.173 6.456 6.805 ;
     RECT  7.44 6.757 15.192 6.805 ;
     RECT  38.976 3.925 40.512 6.851 ;
     RECT  17.28 6.037 19.656 7.381 ;
     RECT  4.8 6.805 15.192 7.475 ;
     RECT  37.488 6.805 37.512 7.907 ;
     RECT  29.4 5.747 29.928 7.909 ;
     RECT  2.304 6.229 2.712 8.051 ;
     RECT  39.12 6.851 40.512 8.147 ;
     RECT  4.8 7.475 14.856 8.291 ;
     RECT  25.584 5.845 26.808 8.435 ;
     RECT  17.28 7.381 19.992 8.437 ;
     RECT  34.8 6.563 35.736 8.485 ;
     RECT  16.656 8.437 19.992 8.531 ;
     RECT  34.8 8.485 35.88 8.581 ;
     RECT  4.8 8.291 8.328 8.677 ;
     RECT  9.312 8.291 14.856 8.723 ;
     RECT  29.28 7.909 29.928 8.723 ;
     RECT  34.704 8.581 35.88 8.819 ;
     RECT  9.312 8.723 13.704 9.107 ;
     RECT  14.784 8.723 14.856 9.155 ;
     RECT  22.176 5.029 22.2 9.155 ;
     RECT  4.608 8.677 8.328 9.251 ;
     RECT  14.784 9.155 14.808 9.491 ;
     RECT  6.432 9.251 8.328 9.541 ;
     RECT  9.312 9.107 13.608 9.541 ;
     RECT  4.608 9.251 5.064 9.731 ;
     RECT  6.432 9.541 13.608 9.731 ;
     RECT  16.656 8.531 19.656 9.731 ;
     RECT  2.4 8.051 2.712 9.733 ;
     RECT  29.28 8.723 29.832 9.733 ;
     RECT  6.432 9.731 6.456 9.779 ;
     RECT  32.112 2.821 32.136 9.827 ;
     RECT  34.704 8.819 35.112 9.827 ;
     RECT  2.4 9.733 2.904 10.115 ;
     RECT  7.584 9.731 13.608 10.213 ;
     RECT  39.408 8.147 40.512 10.261 ;
     RECT  7.584 10.213 13.704 10.307 ;
     RECT  31.008 8.437 31.032 10.307 ;
     RECT  24 5.891 24.504 10.451 ;
     RECT  25.584 8.435 26.328 10.549 ;
     RECT  27.888 8.485 27.912 10.549 ;
     RECT  25.584 10.549 27.912 10.595 ;
     RECT  7.8 10.307 13.704 10.883 ;
     RECT  25.584 10.595 27.144 10.883 ;
     RECT  9.36 10.883 13.704 11.027 ;
     RECT  16.032 9.925 16.056 11.027 ;
     RECT  34.8 9.827 35.112 11.269 ;
     RECT  2.4 10.115 2.712 11.365 ;
     RECT  4.608 9.731 4.632 11.459 ;
     RECT  37.68 8.485 37.704 11.797 ;
     RECT  38.736 10.261 40.512 11.843 ;
     RECT  2.4 11.365 3.576 11.845 ;
     RECT  17.28 9.731 19.656 11.941 ;
     RECT  29.04 9.733 29.832 11.941 ;
     RECT  34.416 11.269 35.112 12.131 ;
     RECT  29.04 11.941 29.88 12.275 ;
     RECT  7.8 10.883 8.328 12.469 ;
     RECT  16.56 11.941 19.656 12.517 ;
     RECT  25.584 10.883 26.328 12.517 ;
     RECT  29.04 12.275 29.832 12.563 ;
     RECT  2.4 11.845 4.584 12.755 ;
     RECT  22.752 10.165 22.776 12.901 ;
     RECT  24 10.451 24.456 13.381 ;
     RECT  25.584 12.517 26.52 13.381 ;
     RECT  24 13.381 26.52 13.475 ;
     RECT  9.36 11.027 13.512 13.571 ;
     RECT  39.408 11.843 40.512 13.573 ;
     RECT  7.392 12.469 8.328 13.621 ;
     RECT  9.36 13.571 9.72 13.907 ;
     RECT  10.752 13.571 13.512 13.909 ;
     RECT  37.632 11.797 37.704 14.197 ;
     RECT  5.808 13.045 5.832 14.245 ;
     RECT  33.312 5.173 33.336 14.245 ;
     RECT  6.816 13.621 8.328 14.291 ;
     RECT  37.44 14.197 37.704 14.291 ;
     RECT  4.56 12.755 4.584 14.339 ;
     RECT  10.752 13.909 13.752 14.533 ;
     RECT  10.752 14.533 14.424 14.819 ;
     RECT  37.44 14.291 37.464 14.867 ;
     RECT  38.88 13.573 40.512 14.867 ;
     RECT  22.704 12.901 22.776 14.869 ;
     RECT  22.704 14.869 22.824 14.915 ;
     RECT  5.712 14.245 5.832 14.963 ;
     RECT  0.24 14.869 0.264 15.013 ;
     RECT  9.36 13.907 9.576 15.301 ;
     RECT  16.512 12.517 19.656 15.349 ;
     RECT  27.792 13.573 27.816 15.349 ;
     RECT  27.36 15.349 27.816 15.395 ;
     RECT  32.832 14.245 33.336 15.491 ;
     RECT  34.8 12.131 35.112 15.541 ;
     RECT  16.512 15.349 20.568 15.589 ;
     RECT  29.4 12.563 29.832 15.973 ;
     RECT  0.24 15.013 0.36 16.019 ;
     RECT  13.2 14.819 14.424 16.019 ;
     RECT  16.416 15.589 20.568 16.019 ;
     RECT  22.8 14.915 22.824 16.019 ;
     RECT  9.36 15.301 9.672 16.501 ;
     RECT  10.752 14.819 12.072 16.501 ;
     RECT  16.416 16.019 19.656 16.501 ;
     RECT  7.392 14.291 8.328 16.597 ;
     RECT  15.936 16.501 19.656 16.835 ;
     RECT  34.608 15.541 35.112 16.835 ;
     RECT  9.36 16.501 12.072 17.077 ;
     RECT  13.2 16.019 13.704 17.077 ;
     RECT  39.312 14.867 40.512 17.077 ;
     RECT  33.216 15.491 33.336 17.123 ;
     RECT  34.704 16.835 35.112 17.171 ;
     RECT  36.192 14.677 36.216 17.171 ;
     RECT  9.36 17.077 13.704 17.219 ;
     RECT  9.36 17.219 13.512 17.411 ;
     RECT  27.36 15.395 27.384 17.651 ;
     RECT  29.4 15.973 30.216 17.891 ;
     RECT  5.808 14.963 5.832 17.941 ;
     RECT  7.296 16.597 8.328 17.941 ;
     RECT  10.752 17.411 13.512 18.275 ;
     RECT  38.736 17.077 40.512 18.659 ;
     RECT  13.2 18.275 13.512 18.757 ;
     RECT  18.24 16.835 19.656 18.757 ;
     RECT  24 13.475 26.328 18.803 ;
     RECT  5.808 17.941 8.328 19.141 ;
     RECT  9.36 17.411 9.384 19.141 ;
     RECT  13.2 18.757 13.704 19.283 ;
     RECT  15.936 16.835 16.44 19.427 ;
     RECT  2.4 12.755 3.576 19.909 ;
     RECT  21.12 19.333 21.144 20.003 ;
     RECT  37.584 19.381 37.608 20.003 ;
     RECT  29.4 17.891 30.072 20.005 ;
     RECT  29.4 20.005 30.504 20.149 ;
     RECT  34.8 17.171 35.112 20.533 ;
     RECT  2.4 19.909 4.152 20.579 ;
     RECT  24 18.803 24.792 20.869 ;
     RECT  25.872 18.803 26.328 20.869 ;
     RECT  5.808 19.141 9.384 20.915 ;
     RECT  5.808 20.915 8.616 20.965 ;
     RECT  27.456 20.149 27.48 20.965 ;
     RECT  29.4 20.149 31.32 21.107 ;
     RECT  27.456 20.965 27.96 21.155 ;
     RECT  33.312 17.123 33.336 21.541 ;
     RECT  34.656 20.533 35.112 21.541 ;
     RECT  10.752 18.275 11.592 21.683 ;
     RECT  27.936 21.155 27.96 21.731 ;
     RECT  5.616 20.965 8.616 21.971 ;
     RECT  22.848 17.077 22.872 22.117 ;
     RECT  29.4 21.107 30.504 22.165 ;
     RECT  11.136 21.683 11.592 22.211 ;
     RECT  11.136 22.211 11.16 22.259 ;
     RECT  24 20.869 26.328 22.453 ;
     RECT  5.616 21.971 8.112 22.597 ;
     RECT  2.4 20.579 3.768 22.741 ;
     RECT  22.224 22.117 22.872 22.835 ;
     RECT  33.312 21.541 35.112 23.171 ;
     RECT  5.088 22.597 8.112 23.411 ;
     RECT  29.4 22.165 31.176 23.411 ;
     RECT  9.168 23.317 9.192 23.795 ;
     RECT  2.4 22.741 3.816 23.845 ;
     RECT  24 22.453 26.472 23.939 ;
     RECT  22.368 22.835 22.872 23.987 ;
     RECT  29.4 23.411 30.504 23.987 ;
     RECT  22.848 23.987 22.872 24.469 ;
     RECT  24 23.939 24.312 24.469 ;
     RECT  10.608 23.893 10.632 24.563 ;
     RECT  33.312 23.171 33.336 24.757 ;
     RECT  34.704 23.171 35.112 24.757 ;
     RECT  2.304 23.845 3.816 24.899 ;
     RECT  36.384 20.389 36.408 25.045 ;
     RECT  25.872 23.939 26.472 25.093 ;
     RECT  29.4 23.987 30.072 25.189 ;
     RECT  31.968 24.277 31.992 25.235 ;
     RECT  22.848 24.469 24.312 25.667 ;
     RECT  5.616 23.411 8.112 25.715 ;
     RECT  25.872 25.093 26.76 25.715 ;
     RECT  29.4 25.189 30.84 26.051 ;
     RECT  36.336 25.045 36.408 26.243 ;
     RECT  38.16 24.469 38.184 26.243 ;
     RECT  17.808 18.757 19.656 26.725 ;
     RECT  27.312 25.861 27.336 26.819 ;
     RECT  29.4 26.051 30.36 26.915 ;
     RECT  13.2 19.283 13.512 27.301 ;
     RECT  22.848 25.667 22.872 27.781 ;
     RECT  24 25.667 24.312 27.781 ;
     RECT  25.872 25.715 26.328 27.877 ;
     RECT  29.4 26.915 30.072 27.877 ;
     RECT  39.408 18.659 40.512 27.877 ;
     RECT  17.808 26.725 20.568 27.923 ;
     RECT  22.848 27.781 24.312 28.501 ;
     RECT  39.312 27.877 40.512 28.547 ;
     RECT  33.312 24.757 35.112 28.691 ;
     RECT  29.28 27.877 30.072 28.931 ;
     RECT  25.872 27.877 26.472 28.979 ;
     RECT  9.648 27.877 9.672 29.219 ;
     RECT  22.8 28.501 24.312 29.219 ;
     RECT  25.872 28.979 26.328 29.269 ;
     RECT  17.808 27.923 19.944 29.605 ;
     RECT  5.664 25.715 8.112 29.699 ;
     RECT  31.968 27.877 31.992 29.989 ;
     RECT  31.968 29.989 32.328 30.035 ;
     RECT  36.384 26.243 36.408 30.181 ;
     RECT  39.408 28.547 40.512 30.181 ;
     RECT  5.664 29.699 5.688 30.229 ;
     RECT  2.304 24.899 3.768 30.275 ;
     RECT  25.344 29.269 26.328 30.323 ;
     RECT  4.8 30.229 5.688 30.709 ;
     RECT  6.864 29.699 8.112 30.709 ;
     RECT  4.8 30.709 8.112 30.851 ;
     RECT  34.8 28.691 35.112 30.949 ;
     RECT  2.304 30.275 3.624 30.995 ;
     RECT  38.784 30.181 40.512 31.235 ;
     RECT  4.8 30.851 6.36 31.379 ;
     RECT  17.808 29.605 20.328 31.379 ;
     RECT  36.192 30.181 36.408 31.379 ;
     RECT  29.4 28.931 30.072 31.381 ;
     RECT  32.304 30.035 32.328 31.571 ;
     RECT  27.456 30.709 27.48 32.195 ;
     RECT  34.704 30.949 35.112 32.195 ;
     RECT  22.848 29.219 24.312 32.339 ;
     RECT  36.384 31.379 36.408 32.531 ;
     RECT  39.168 31.235 40.512 32.915 ;
     RECT  18 31.379 20.328 33.011 ;
     RECT  4.8 31.379 5.592 33.013 ;
     RECT  13.2 27.301 14.136 33.013 ;
     RECT  4.8 33.013 5.688 33.251 ;
     RECT  34.8 32.195 35.112 33.541 ;
     RECT  24 32.339 24.312 33.589 ;
     RECT  5.568 33.251 5.688 33.731 ;
     RECT  25.872 30.323 26.328 33.925 ;
     RECT  22.848 32.339 22.872 34.117 ;
     RECT  24 33.589 24.552 34.117 ;
     RECT  18 33.011 19.944 34.355 ;
     RECT  18 34.355 19.656 34.501 ;
     RECT  21.12 33.205 21.144 34.643 ;
     RECT  13.2 33.013 14.856 34.741 ;
     RECT  22.848 34.117 24.552 34.787 ;
     RECT  25.872 33.925 26.376 34.787 ;
     RECT  22.848 34.787 24.312 34.835 ;
     RECT  32.304 33.973 32.328 34.835 ;
     RECT  9.168 33.013 9.192 34.883 ;
     RECT  39.408 32.915 40.512 34.931 ;
     RECT  34.8 33.541 35.976 35.027 ;
     RECT  13.104 34.741 14.856 35.219 ;
     RECT  2.304 30.995 2.856 35.507 ;
     RECT  13.104 35.219 14.76 35.699 ;
     RECT  13.104 35.699 13.512 35.845 ;
     RECT  24 34.835 24.312 35.845 ;
     RECT  33.312 28.691 33.336 35.845 ;
     RECT  24 35.845 24.504 36.035 ;
     RECT  0.24 16.019 0.264 36.083 ;
     RECT  16.416 19.427 16.44 36.085 ;
     RECT  17.424 34.501 19.656 36.085 ;
     RECT  25.872 34.787 26.328 36.181 ;
     RECT  27.408 35.221 27.432 36.181 ;
     RECT  29.088 31.381 30.072 36.277 ;
     RECT  29.04 36.277 30.072 36.323 ;
     RECT  2.4 35.507 2.856 36.421 ;
     RECT  4.032 36.133 4.056 36.421 ;
     RECT  5.664 33.731 5.688 36.421 ;
     RECT  33.312 35.845 33.672 36.421 ;
     RECT  32.976 36.421 33.672 36.467 ;
     RECT  29.04 36.323 29.712 36.517 ;
     RECT  2.4 36.421 4.056 36.755 ;
     RECT  38.736 36.085 38.76 37.043 ;
     RECT  7.344 30.851 8.112 37.091 ;
     RECT  14.496 35.699 14.76 37.091 ;
     RECT  16.416 36.085 19.656 37.091 ;
     RECT  39.888 34.931 40.512 37.093 ;
     RECT  32.976 36.467 33.336 37.907 ;
     RECT  5.664 36.421 5.736 38.147 ;
     RECT  25.872 36.181 27.432 38.243 ;
     RECT  36.432 36.949 36.456 38.389 ;
     RECT  10.416 37.621 10.44 38.435 ;
     RECT  36.096 38.389 36.456 38.435 ;
     RECT  4.512 37.573 4.536 38.725 ;
     RECT  17.712 37.091 19.656 38.725 ;
     RECT  21.648 37.573 21.672 38.725 ;
     RECT  22.848 34.835 22.872 38.725 ;
     RECT  21.648 38.725 22.872 38.771 ;
     RECT  32.976 37.907 33.144 38.773 ;
     RECT  4.176 38.725 4.536 39.251 ;
     RECT  32.832 38.773 33.144 39.253 ;
     RECT  4.176 39.251 4.2 39.395 ;
     RECT  17.712 38.725 20.52 39.395 ;
     RECT  28.944 36.517 29.712 39.443 ;
     RECT  32.448 39.253 33.144 39.589 ;
     RECT  34.8 35.027 35.112 39.589 ;
     RECT  36.096 38.435 36.12 39.589 ;
     RECT  22.608 38.771 22.872 39.731 ;
     RECT  39.84 37.093 40.512 39.827 ;
     RECT  12.48 35.845 13.512 40.019 ;
     RECT  22.848 39.731 22.872 40.117 ;
     RECT  24 36.035 24.312 40.117 ;
     RECT  32.448 39.589 36.12 40.307 ;
     RECT  25.872 38.243 26.328 40.309 ;
     RECT  27.408 38.243 27.432 40.309 ;
     RECT  2.4 36.755 2.856 40.499 ;
     RECT  4.128 39.589 4.152 40.499 ;
     RECT  33.456 40.307 36.12 40.835 ;
     RECT  13.2 40.019 13.512 40.981 ;
     RECT  25.872 40.309 27.432 41.027 ;
     RECT  27.408 41.027 27.432 41.075 ;
     RECT  33.456 40.835 35.352 41.075 ;
     RECT  14.496 37.091 14.52 41.651 ;
     RECT  18.144 39.395 19.656 41.651 ;
     RECT  12.24 40.981 13.512 42.227 ;
     RECT  5.664 38.147 5.688 42.275 ;
     RECT  16.416 37.091 16.44 42.565 ;
     RECT  32.448 40.307 32.472 42.565 ;
     RECT  18.432 41.651 19.656 42.709 ;
     RECT  33.84 41.075 35.352 42.709 ;
     RECT  31.776 42.565 32.472 42.755 ;
     RECT  7.8 37.091 8.112 42.757 ;
     RECT  22.848 40.117 24.312 42.803 ;
     RECT  31.776 42.755 31.8 42.851 ;
     RECT  33.84 42.709 36.072 42.899 ;
     RECT  37.296 42.709 37.32 43.139 ;
     RECT  33.84 42.899 35.976 43.235 ;
     RECT  33.84 43.235 35.592 43.667 ;
     RECT  38.928 41.509 38.952 43.811 ;
     RECT  18.432 42.709 19.848 43.813 ;
     RECT  22.944 42.803 24.312 44.293 ;
     RECT  7.8 42.757 8.424 44.389 ;
     RECT  34.176 43.667 35.592 44.965 ;
     RECT  38.544 44.725 38.568 44.965 ;
     RECT  5.856 43.909 5.88 45.059 ;
     RECT  18.432 43.813 20.472 45.155 ;
     RECT  4.032 41.557 4.056 45.301 ;
     RECT  25.872 41.027 26.328 45.301 ;
     RECT  4.032 45.301 4.536 45.347 ;
     RECT  34.176 44.965 36.552 45.541 ;
     RECT  4.512 45.347 4.536 45.589 ;
     RECT  32.736 45.157 32.76 45.589 ;
     RECT  18.432 45.155 20.088 45.637 ;
     RECT  7.8 44.389 8.952 45.685 ;
     RECT  30.912 44.053 30.936 45.685 ;
     RECT  7.632 45.685 8.952 45.731 ;
     RECT  30.816 45.685 30.936 45.731 ;
     RECT  40.2 39.827 40.512 45.733 ;
     RECT  34.176 45.541 36.744 45.779 ;
     RECT  4.512 45.589 5.448 46.069 ;
     RECT  15.984 42.565 16.44 46.211 ;
     RECT  4.512 46.069 6.312 46.259 ;
     RECT  18.336 45.637 20.088 46.259 ;
     RECT  25.728 45.301 26.328 46.451 ;
     RECT  7.632 45.731 8.424 46.499 ;
     RECT  20.064 46.259 20.088 46.499 ;
     RECT  22.8 44.293 24.312 46.499 ;
     RECT  38.208 44.965 38.568 46.499 ;
     RECT  26.16 46.451 26.328 46.693 ;
     RECT  6.288 46.259 6.312 46.787 ;
     RECT  26.16 46.693 27.288 46.787 ;
     RECT  32.448 45.589 32.76 46.787 ;
     RECT  38.304 46.499 38.568 46.787 ;
     RECT  30.816 45.731 30.84 46.835 ;
     RECT  32.448 46.787 32.52 47.075 ;
     RECT  10.224 45.541 10.248 47.077 ;
     RECT  11.232 42.613 11.256 47.077 ;
     RECT  10.224 47.077 11.256 47.173 ;
     RECT  13.2 42.227 13.512 47.269 ;
     RECT  39.936 45.733 40.512 47.363 ;
     RECT  22.848 46.499 24.312 47.555 ;
     RECT  4.512 46.259 4.536 47.557 ;
     RECT  29.04 39.443 29.712 47.701 ;
     RECT  13.2 47.269 13.608 47.845 ;
     RECT  26.304 46.787 27.288 47.845 ;
     RECT  4.512 47.557 5.112 47.891 ;
     RECT  34.8 45.779 36.744 47.891 ;
     RECT  9.984 47.173 11.256 47.939 ;
     RECT  29.04 47.701 29.832 48.181 ;
     RECT  16.416 46.211 16.44 48.277 ;
     RECT  10.848 47.939 11.256 48.419 ;
     RECT  7.8 46.499 8.424 48.421 ;
     RECT  34.8 47.891 35.592 48.421 ;
     RECT  32.496 47.075 32.52 48.467 ;
     RECT  18.336 46.259 18.912 48.515 ;
     RECT  28.944 48.181 29.832 48.515 ;
     RECT  26.304 47.845 27.384 48.803 ;
     RECT  20.064 47.749 20.088 48.805 ;
     RECT  20.064 48.805 20.328 48.851 ;
     RECT  34.368 48.421 35.592 48.997 ;
     RECT  26.304 48.803 26.808 49.091 ;
     RECT  22.944 47.555 24.312 49.187 ;
     RECT  6.96 48.421 8.424 49.235 ;
     RECT  36.72 47.891 36.744 49.237 ;
     RECT  36.72 49.237 36.984 49.477 ;
     RECT  38.304 46.787 38.328 49.477 ;
     RECT  34.08 48.997 35.592 49.573 ;
     RECT  36.72 49.477 38.328 49.573 ;
     RECT  34.08 49.573 38.328 49.619 ;
     RECT  15.888 48.277 16.44 50.101 ;
     RECT  34.08 49.619 35.88 50.147 ;
     RECT  28.944 48.515 29.712 50.291 ;
     RECT  34.368 50.147 35.88 50.531 ;
     RECT  34.368 50.531 35.496 50.579 ;
     RECT  22.944 49.187 22.968 50.677 ;
     RECT  22.848 50.677 22.968 50.723 ;
     RECT  26.304 49.091 26.328 50.725 ;
     RECT  15.888 50.101 17.256 50.771 ;
     RECT  37.92 49.619 38.328 50.771 ;
     RECT  37.92 50.771 37.944 51.203 ;
     RECT  27.648 49.861 27.672 51.347 ;
     RECT  18.6 48.515 18.912 51.541 ;
     RECT  20.304 48.851 20.328 51.923 ;
     RECT  39.984 47.363 40.512 51.923 ;
     RECT  26.064 50.725 26.328 51.971 ;
     RECT  10.992 48.419 11.256 52.165 ;
     RECT  28.992 50.291 29.712 52.165 ;
     RECT  10.944 52.165 11.256 52.261 ;
     RECT  28.992 52.165 30.024 52.307 ;
     RECT  10.944 52.261 11.88 52.403 ;
     RECT  34.8 50.579 35.496 52.499 ;
     RECT  18.48 51.541 18.912 52.981 ;
     RECT  26.304 51.971 26.328 52.981 ;
     RECT  15.888 50.771 16.44 53.027 ;
     RECT  24 49.187 24.312 53.029 ;
     RECT  17.904 52.981 18.912 53.365 ;
     RECT  24 53.029 24.792 53.795 ;
     RECT  17.904 53.365 19.464 53.989 ;
     RECT  10.992 52.403 11.88 54.085 ;
     RECT  34.8 52.499 35.112 54.085 ;
     RECT  36.432 52.981 36.456 54.085 ;
     RECT  34.8 54.085 36.456 54.131 ;
     RECT  17.664 53.989 19.464 54.277 ;
     RECT  17.664 54.277 19.944 54.323 ;
     RECT  31.008 52.981 31.032 54.371 ;
     RECT  29.4 52.307 30.024 54.373 ;
     RECT  22.848 50.723 22.872 54.661 ;
     RECT  26.304 52.981 27.288 54.707 ;
     RECT  10.992 54.085 12.12 54.755 ;
     RECT  29.184 54.373 30.024 54.995 ;
     RECT  11.184 54.755 12.12 54.997 ;
     RECT  13.2 47.845 13.656 54.997 ;
     RECT  37.584 54.565 37.608 55.237 ;
     RECT  37.344 55.237 37.608 55.283 ;
     RECT  17.664 54.323 18.912 55.331 ;
     RECT  29.184 54.995 29.712 55.331 ;
     RECT  38.88 52.885 38.904 55.477 ;
     RECT  40.2 51.923 40.512 55.477 ;
     RECT  34.8 54.131 35.928 55.523 ;
     RECT  31.296 55.237 31.32 55.669 ;
     RECT  30.816 55.669 31.32 55.715 ;
     RECT  16.416 53.027 16.44 55.813 ;
     RECT  38.88 55.477 40.512 56.147 ;
     RECT  9.648 54.661 9.672 56.195 ;
     RECT  19.92 54.323 19.944 56.243 ;
     RECT  22.8 54.661 22.872 56.243 ;
     RECT  30.816 55.715 31.272 56.339 ;
     RECT  16.416 55.813 16.68 56.341 ;
     RECT  11.184 54.997 13.656 56.531 ;
     RECT  26.304 54.707 26.952 56.531 ;
     RECT  37.344 55.283 37.368 56.723 ;
     RECT  26.304 56.531 26.328 57.013 ;
     RECT  16.416 56.341 17.304 57.059 ;
     RECT  7.8 49.235 8.424 57.301 ;
     RECT  34.8 55.523 35.208 57.443 ;
     RECT  22.848 56.243 22.872 57.445 ;
     RECT  22.656 57.445 22.872 57.491 ;
     RECT  4.176 56.389 4.2 57.541 ;
     RECT  7.68 57.301 8.424 57.541 ;
     RECT  12.96 56.531 13.656 57.541 ;
     RECT  18.6 55.331 18.912 57.541 ;
     RECT  25.872 57.013 26.328 57.587 ;
     RECT  16.416 57.059 16.44 58.117 ;
     RECT  12.528 57.541 13.656 58.163 ;
     RECT  18.6 57.541 19.416 58.163 ;
     RECT  31.248 56.339 31.272 58.163 ;
     RECT  13.008 58.163 13.656 58.645 ;
     RECT  34.8 57.443 35.112 58.645 ;
     RECT  22.656 57.491 22.824 58.691 ;
     RECT  25.776 57.973 25.8 58.739 ;
     RECT  13.008 58.645 14.52 59.075 ;
     RECT  29.4 55.331 29.712 59.221 ;
     RECT  7.632 57.541 8.424 59.315 ;
     RECT  33.936 58.645 35.112 59.411 ;
     RECT  7.68 59.315 8.424 59.507 ;
     RECT  39.312 56.147 40.512 59.507 ;
     RECT  4.176 57.541 4.584 59.603 ;
     RECT  18.6 58.163 18.912 59.749 ;
     RECT  24 53.795 24.312 59.749 ;
     RECT  38.016 58.117 38.04 59.795 ;
     RECT  28.464 59.221 29.712 59.797 ;
     RECT  4.176 59.603 4.2 59.891 ;
     RECT  16.224 58.117 16.44 59.891 ;
     RECT  13.008 59.075 13.656 60.035 ;
     RECT  11.184 56.531 11.208 60.467 ;
     RECT  19.92 59.221 19.944 60.467 ;
     RECT  28.464 59.797 30.36 60.661 ;
     RECT  34.8 59.411 35.112 60.661 ;
     RECT  27.936 60.661 30.36 60.707 ;
     RECT  13.008 60.035 13.512 60.949 ;
     RECT  22.656 58.691 22.68 60.949 ;
     RECT  29.4 60.707 30.36 60.995 ;
     RECT  32.448 54.517 32.472 61.189 ;
     RECT  7.8 59.507 8.424 61.525 ;
     RECT  16.416 59.891 16.44 61.525 ;
     RECT  18.192 59.749 18.912 61.525 ;
     RECT  22.464 60.949 22.68 61.525 ;
     RECT  24 59.749 24.6 61.525 ;
     RECT  34.8 60.661 35.88 61.525 ;
     RECT  22.464 61.525 24.6 61.571 ;
     RECT  16.416 61.525 17.016 61.619 ;
     RECT  16.992 61.619 17.016 62.099 ;
     RECT  10.992 60.709 11.016 62.101 ;
     RECT  7.248 61.525 8.424 62.149 ;
     RECT  9.696 61.189 9.72 62.149 ;
     RECT  14.784 61.573 14.808 62.195 ;
     RECT  22.656 61.571 24.6 62.195 ;
     RECT  27.936 60.707 27.96 62.195 ;
     RECT  34.224 61.525 35.88 62.195 ;
     RECT  18.192 61.525 19.464 62.435 ;
     RECT  7.248 62.149 9.72 62.677 ;
     RECT  10.8 62.101 11.016 62.677 ;
     RECT  29.4 60.995 29.712 62.725 ;
     RECT  31.872 61.189 32.472 62.725 ;
     RECT  18.192 62.435 18.912 62.771 ;
     RECT  29.28 62.725 29.712 62.821 ;
     RECT  31.872 62.725 33.096 62.915 ;
     RECT  7.248 62.677 11.016 63.013 ;
     RECT  12.48 60.949 13.512 63.107 ;
     RECT  22.656 62.195 24.312 63.299 ;
     RECT  6.864 63.013 11.016 63.827 ;
     RECT  34.8 62.195 35.88 64.019 ;
     RECT  31.584 63.301 31.608 64.357 ;
     RECT  7.248 63.827 11.016 64.451 ;
     RECT  25.632 62.725 25.656 64.835 ;
     RECT  22.224 63.589 22.248 64.885 ;
     RECT  23.616 63.299 24.312 64.885 ;
     RECT  22.224 64.885 24.312 64.931 ;
     RECT  20.496 63.781 20.52 65.171 ;
     RECT  31.584 64.357 31.656 65.219 ;
     RECT  9.168 64.451 11.016 65.267 ;
     RECT  31.632 65.219 31.656 65.461 ;
     RECT  27.216 64.933 27.24 65.555 ;
     RECT  33.072 62.915 33.096 65.603 ;
     RECT  15.936 63.589 15.96 65.987 ;
     RECT  29.28 62.821 30.264 66.085 ;
     RECT  34.8 64.019 35.112 66.085 ;
     RECT  7.44 64.451 8.112 66.179 ;
     RECT  12.672 63.107 13.512 66.179 ;
     RECT  22.8 64.931 24.312 66.515 ;
     RECT  18.6 62.771 18.912 66.517 ;
     RECT  9.312 65.267 11.016 66.661 ;
     RECT  34.8 66.085 35.88 66.661 ;
     RECT  29.136 66.085 30.264 66.803 ;
     RECT  31.632 65.461 31.896 66.899 ;
     RECT  37.296 63.781 37.32 66.899 ;
     RECT  33.936 66.661 35.88 66.901 ;
     RECT  9.168 66.661 11.016 67.093 ;
     RECT  26.928 66.325 26.952 67.139 ;
     RECT  9.12 67.093 11.016 67.283 ;
     RECT  12.864 66.179 13.512 67.283 ;
     RECT  7.632 66.179 8.112 67.379 ;
     RECT  9.12 67.283 10.968 67.571 ;
     RECT  29.4 66.803 30.264 67.765 ;
     RECT  29.4 67.765 30.744 67.811 ;
     RECT  9.12 67.571 10.584 67.859 ;
     RECT  21.12 66.085 21.144 67.859 ;
     RECT  22.8 66.515 22.824 67.859 ;
     RECT  33.888 66.901 35.88 68.147 ;
     RECT  37.344 66.949 37.368 68.243 ;
     RECT  28.128 66.565 28.152 68.387 ;
     RECT  31.872 66.899 31.896 68.387 ;
     RECT  33.888 68.147 35.112 68.387 ;
     RECT  30.72 67.811 30.744 68.435 ;
     RECT  17.04 67.717 17.064 68.675 ;
     RECT  18.6 66.517 19.704 68.675 ;
     RECT  6.48 67.477 6.504 68.867 ;
     RECT  7.8 67.379 8.112 68.965 ;
     RECT  9.12 67.859 10.2 68.965 ;
     RECT  2.4 40.499 2.712 69.129 ;
     RECT  7.8 68.965 10.92 69.129 ;
     RECT  13.2 67.283 13.512 69.129 ;
     RECT  18.6 68.675 18.912 69.129 ;
     RECT  24 66.515 24.312 69.129 ;
     RECT  29.4 67.811 29.712 69.129 ;
     RECT  34.8 68.387 35.112 69.129 ;
     RECT  40.2 59.507 40.512 69.129 ;
     RECT  2.4 69.129 2.52 69.143 ;
     RECT  7.8 69.129 7.92 69.143 ;
     RECT  13.2 69.129 13.32 69.143 ;
     RECT  18.6 69.129 18.72 69.143 ;
     RECT  24 69.129 24.12 69.143 ;
     RECT  29.4 69.129 29.52 69.143 ;
     RECT  34.8 69.129 34.92 69.143 ;
     RECT  40.2 69.129 40.32 69.143 ;
     RECT  9.024 69.129 10.92 70.069 ;
     RECT  9.024 70.069 11.208 71.12 ;
     RECT  9.024 1.187 9.456 2.137 ;
     RECT  7.92 2.137 9.456 2.151 ;
     RECT  8.112 2.151 9.456 2.773 ;
     RECT  14.136 2.677 15.12 3.397 ;
     RECT  35.112 2.773 36.432 6.229 ;
     RECT  39 2.821 40.2 3.301 ;
     RECT  29.712 3.157 30.816 5.029 ;
     RECT  30.84 3.157 32.112 5.747 ;
     RECT  39 3.301 40.08 3.925 ;
     RECT  22.368 3.539 22.392 3.925 ;
     RECT  21.096 3.925 23.376 5.029 ;
     RECT  15.672 4.019 16.152 4.115 ;
     RECT  15.336 4.115 16.152 5.077 ;
     RECT  34.176 4.451 34.32 5.173 ;
     RECT  9.96 4.691 11.28 6.229 ;
     RECT  11.736 4.691 12.72 5.797 ;
     RECT  21.096 5.029 22.176 5.699 ;
     RECT  22.2 5.029 23.376 5.075 ;
     RECT  15.336 5.077 17.28 5.317 ;
     RECT  3.432 5.125 4.8 5.747 ;
     RECT  6.456 5.173 7.8 5.653 ;
     RECT  32.136 5.173 33.312 9.827 ;
     RECT  33.336 5.173 34.32 5.459 ;
     RECT  15.96 5.317 17.28 5.795 ;
     RECT  24.504 5.459 25.128 5.509 ;
     RECT  33.336 5.459 34.8 8.581 ;
     RECT  24.504 5.509 26.304 5.749 ;
     RECT  6.456 5.653 7.44 6.805 ;
     RECT  24.504 5.749 25.584 10.451 ;
     RECT  9.96 6.229 11.232 6.757 ;
     RECT  37.512 6.805 38.976 6.851 ;
     RECT  8.328 8.291 9.312 9.541 ;
     RECT  29.928 8.437 31.008 8.723 ;
     RECT  31.032 8.437 32.112 9.827 ;
     RECT  27.912 8.485 29.28 9.733 ;
     RECT  33.336 8.581 34.704 9.827 ;
     RECT  13.704 8.723 14.784 9.107 ;
     RECT  29.832 8.723 31.008 10.307 ;
     RECT  13.608 9.107 14.784 9.491 ;
     RECT  5.064 9.251 6.432 9.731 ;
     RECT  13.608 9.491 13.704 10.213 ;
     RECT  6.456 9.731 7.584 9.779 ;
     RECT  16.656 9.731 17.28 9.925 ;
     RECT  27.912 9.733 29.04 10.595 ;
     RECT  33.336 9.827 34.8 11.269 ;
     RECT  16.056 9.925 17.28 11.027 ;
     RECT  2.712 10.115 2.904 11.365 ;
     RECT  22.776 10.165 24 14.869 ;
     RECT  37.704 10.261 38.736 11.843 ;
     RECT  24.456 10.451 25.584 13.381 ;
     RECT  8.328 10.883 9.36 19.141 ;
     RECT  16.512 11.027 17.28 11.941 ;
     RECT  33.336 11.269 34.416 12.131 ;
     RECT  3.576 11.365 4.608 11.459 ;
     RECT  3.576 11.459 4.584 11.845 ;
     RECT  16.512 11.941 16.56 12.517 ;
     RECT  33.336 12.131 34.8 15.541 ;
     RECT  3.576 12.755 4.56 14.339 ;
     RECT  4.584 13.045 5.808 14.245 ;
     RECT  26.328 13.475 26.52 13.573 ;
     RECT  9.72 13.571 10.752 13.907 ;
     RECT  26.328 13.573 27.792 15.349 ;
     RECT  37.704 13.573 38.88 14.291 ;
     RECT  5.832 13.621 6.816 14.291 ;
     RECT  9.576 13.907 10.752 15.301 ;
     RECT  4.584 14.245 5.712 14.339 ;
     RECT  37.464 14.291 38.88 14.867 ;
     RECT  35.112 14.677 36.192 17.171 ;
     RECT  36.216 14.677 37.44 14.867 ;
     RECT  12.072 14.819 13.2 17.077 ;
     RECT  22.824 14.869 24 16.019 ;
     RECT  9.672 15.301 10.752 16.501 ;
     RECT  26.328 15.349 27.36 17.651 ;
     RECT  33.336 15.541 34.608 16.835 ;
     RECT  22.848 16.019 24 17.077 ;
     RECT  5.832 16.597 7.296 17.941 ;
     RECT  33.336 16.835 34.704 17.171 ;
     RECT  22.872 17.077 24 24.469 ;
     RECT  33.336 17.171 34.8 20.533 ;
     RECT  9.384 17.411 10.752 20.915 ;
     RECT  16.44 18.757 17.808 31.379 ;
     RECT  24.792 18.803 25.872 20.869 ;
     RECT  19.656 19.333 21.12 20.003 ;
     RECT  26.328 20.149 27.456 21.155 ;
     RECT  35.112 20.389 36.384 25.045 ;
     RECT  33.336 20.533 34.656 21.541 ;
     RECT  27.96 20.965 29.4 21.731 ;
     RECT  30.504 21.107 31.176 22.165 ;
     RECT  26.328 21.155 27.936 21.731 ;
     RECT  26.328 21.731 26.472 22.453 ;
     RECT  8.112 21.971 8.616 23.317 ;
     RECT  3.768 22.597 5.088 22.741 ;
     RECT  3.816 22.741 5.088 23.411 ;
     RECT  33.336 23.171 34.704 24.757 ;
     RECT  8.112 23.317 9.168 23.795 ;
     RECT  30.504 23.411 31.176 23.987 ;
     RECT  30.072 23.987 31.176 24.277 ;
     RECT  30.072 24.277 31.968 25.189 ;
     RECT  31.992 24.277 33.312 25.235 ;
     RECT  38.184 24.469 39.408 26.243 ;
     RECT  35.112 25.045 36.336 26.243 ;
     RECT  30.84 25.189 31.968 25.235 ;
     RECT  22.872 25.667 24 27.781 ;
     RECT  26.328 25.715 26.76 25.861 ;
     RECT  26.328 25.861 27.312 26.819 ;
     RECT  35.112 26.243 36.384 30.181 ;
     RECT  26.328 26.819 26.472 27.877 ;
     RECT  31.992 27.877 33.312 29.989 ;
     RECT  33.336 28.691 34.8 30.949 ;
     RECT  24.312 29.269 25.344 30.323 ;
     RECT  5.688 29.699 6.864 30.709 ;
     RECT  32.328 29.989 33.312 31.571 ;
     RECT  35.112 30.181 36.192 31.379 ;
     RECT  3.768 30.229 4.8 30.275 ;
     RECT  3.624 30.275 4.8 30.995 ;
     RECT  26.328 30.709 27.456 32.195 ;
     RECT  6.36 30.851 7.344 31.379 ;
     RECT  33.336 30.949 34.704 32.195 ;
     RECT  35.112 31.379 36.384 32.531 ;
     RECT  33.336 32.195 34.8 35.845 ;
     RECT  22.872 32.339 24 34.117 ;
     RECT  35.112 32.531 35.976 33.541 ;
     RECT  19.944 33.011 20.328 33.205 ;
     RECT  8.112 33.013 9.168 34.883 ;
     RECT  19.944 33.205 21.12 34.355 ;
     RECT  24.552 33.589 25.872 34.787 ;
     RECT  32.328 33.973 33.312 34.835 ;
     RECT  19.656 34.355 21.12 34.643 ;
     RECT  16.44 34.501 17.424 36.085 ;
     RECT  24.312 34.787 25.872 35.845 ;
     RECT  26.328 34.787 26.376 35.221 ;
     RECT  22.872 34.835 24 40.117 ;
     RECT  39.408 34.931 39.888 36.085 ;
     RECT  26.328 35.221 27.408 36.181 ;
     RECT  13.512 35.699 14.496 41.651 ;
     RECT  24.504 35.845 25.872 36.035 ;
     RECT  33.672 35.845 34.8 36.467 ;
     RECT  38.76 36.085 39.888 37.043 ;
     RECT  2.856 36.133 4.032 36.421 ;
     RECT  33.336 36.467 34.8 37.907 ;
     RECT  27.432 36.517 28.944 39.443 ;
     RECT  35.112 36.949 36.432 38.389 ;
     RECT  39.84 37.043 39.888 37.093 ;
     RECT  16.44 37.091 17.712 39.395 ;
     RECT  4.536 37.573 5.664 39.251 ;
     RECT  21.672 37.573 22.848 38.725 ;
     RECT  26.328 38.243 27.408 40.309 ;
     RECT  35.112 38.389 36.096 39.589 ;
     RECT  2.856 38.725 4.176 39.395 ;
     RECT  20.52 38.725 21.648 38.771 ;
     RECT  4.2 39.251 5.664 39.395 ;
     RECT  2.856 39.395 5.664 39.589 ;
     RECT  2.856 39.589 4.128 40.499 ;
     RECT  4.152 39.589 5.664 40.499 ;
     RECT  12.48 40.019 13.2 40.981 ;
     RECT  32.472 40.307 33.456 41.075 ;
     RECT  2.712 40.499 4.056 41.557 ;
     RECT  26.328 41.027 27.408 41.075 ;
     RECT  32.472 41.075 33.84 42.755 ;
     RECT  38.952 41.509 40.2 43.811 ;
     RECT  2.712 41.557 4.032 45.347 ;
     RECT  36.072 42.709 37.296 42.899 ;
     RECT  22.848 42.803 22.944 44.293 ;
     RECT  35.976 42.899 37.296 43.139 ;
     RECT  33.84 43.667 34.176 45.157 ;
     RECT  29.712 44.053 30.912 45.685 ;
     RECT  5.856 45.059 5.88 45.301 ;
     RECT  32.76 45.157 34.176 45.779 ;
     RECT  4.536 45.301 5.88 45.589 ;
     RECT  24.312 45.301 25.728 46.451 ;
     RECT  8.952 45.541 10.224 45.731 ;
     RECT  10.248 45.541 11.232 47.077 ;
     RECT  36.744 45.541 38.208 46.499 ;
     RECT  5.448 45.589 5.88 46.069 ;
     RECT  30.936 45.589 32.448 45.731 ;
     RECT  29.712 45.685 30.816 46.835 ;
     RECT  9.984 45.731 10.224 47.173 ;
     RECT  38.568 45.733 39.936 46.787 ;
     RECT  6.312 46.069 7.632 46.499 ;
     RECT  4.536 46.259 6.288 46.787 ;
     RECT  18.912 46.259 20.064 46.499 ;
     RECT  6.312 46.499 7.8 46.787 ;
     RECT  18.912 46.499 20.088 47.749 ;
     RECT  4.536 46.787 5.112 47.557 ;
     RECT  29.712 46.835 29.832 47.701 ;
     RECT  18.912 47.749 20.064 48.851 ;
     RECT  35.592 47.891 36.72 49.573 ;
     RECT  26.808 48.803 27.384 49.091 ;
     RECT  18.912 48.851 20.304 51.923 ;
     RECT  26.328 49.091 27.384 49.861 ;
     RECT  22.968 49.187 24 50.723 ;
     RECT  36.984 49.237 38.304 49.477 ;
     RECT  26.328 49.861 27.648 51.347 ;
     RECT  27.672 49.861 28.944 50.291 ;
     RECT  17.256 50.101 18.6 50.771 ;
     RECT  27.672 50.291 28.992 51.347 ;
     RECT  22.872 50.723 24 57.491 ;
     RECT  18.48 50.771 18.6 51.541 ;
     RECT  18.912 51.923 19.464 53.365 ;
     RECT  39.984 51.923 40.2 52.885 ;
     RECT  26.064 51.971 26.304 53.029 ;
     RECT  11.88 52.261 13.2 54.085 ;
     RECT  35.112 52.499 35.496 52.981 ;
     RECT  38.904 52.885 40.2 55.477 ;
     RECT  16.44 52.981 17.904 53.989 ;
     RECT  30.024 52.981 31.008 54.371 ;
     RECT  35.112 52.981 36.432 54.085 ;
     RECT  24.792 53.029 26.304 53.795 ;
     RECT  16.44 53.989 17.664 55.331 ;
     RECT  12.12 54.085 13.2 54.997 ;
     RECT  35.928 54.131 36.456 54.565 ;
     RECT  18.912 54.323 19.92 56.243 ;
     RECT  30.024 54.371 31.032 54.517 ;
     RECT  30.024 54.517 32.448 54.995 ;
     RECT  35.928 54.565 37.584 55.237 ;
     RECT  37.608 54.565 38.88 55.283 ;
     RECT  8.424 54.661 9.648 56.195 ;
     RECT  9.672 54.661 10.992 54.755 ;
     RECT  9.672 54.755 11.184 56.195 ;
     RECT  29.712 54.995 32.448 55.237 ;
     RECT  29.712 55.237 31.296 55.669 ;
     RECT  31.32 55.237 32.448 55.715 ;
     RECT  35.928 55.237 37.344 55.523 ;
     RECT  37.368 55.283 38.88 56.147 ;
     RECT  16.44 55.331 18.6 55.813 ;
     RECT  29.712 55.669 30.816 56.339 ;
     RECT  31.272 55.715 32.448 58.163 ;
     RECT  16.68 55.813 18.6 56.341 ;
     RECT  18.912 56.243 19.416 57.541 ;
     RECT  22.8 56.243 22.848 57.445 ;
     RECT  17.304 56.341 18.6 57.059 ;
     RECT  2.712 56.389 4.176 59.891 ;
     RECT  11.208 56.531 12.96 57.541 ;
     RECT  22.824 57.491 24 58.691 ;
     RECT  11.208 57.541 12.528 58.163 ;
     RECT  24.312 57.973 25.776 58.739 ;
     RECT  38.04 58.117 39.312 59.507 ;
     RECT  18.912 58.163 19.416 59.221 ;
     RECT  32.472 58.645 33.936 59.411 ;
     RECT  22.68 58.691 24 61.525 ;
     RECT  24.312 58.739 24.6 59.749 ;
     RECT  18.912 59.221 19.92 60.467 ;
     RECT  11.184 60.467 11.208 60.709 ;
     RECT  18.912 60.467 19.464 61.525 ;
     RECT  27.96 60.707 29.4 62.195 ;
     RECT  11.016 60.709 11.208 60.949 ;
     RECT  11.016 60.949 12.48 63.107 ;
     RECT  8.424 61.189 9.696 62.149 ;
     RECT  9.72 61.189 10.992 62.101 ;
     RECT  17.016 61.525 18.192 62.099 ;
     RECT  13.512 61.573 14.784 62.195 ;
     RECT  9.72 62.101 10.8 62.677 ;
     RECT  24.312 62.195 24.6 62.725 ;
     RECT  29.28 62.195 29.4 62.725 ;
     RECT  24.312 62.725 25.632 64.835 ;
     RECT  31.872 62.915 33.072 63.301 ;
     RECT  22.656 63.299 23.616 63.589 ;
     RECT  30.264 63.301 31.584 65.219 ;
     RECT  31.608 63.301 33.072 64.357 ;
     RECT  22.248 63.589 23.616 64.885 ;
     RECT  35.88 63.781 37.296 64.019 ;
     RECT  31.656 64.357 33.072 65.461 ;
     RECT  8.112 64.451 9.168 65.267 ;
     RECT  20.496 65.171 20.52 66.085 ;
     RECT  30.264 65.219 31.632 66.899 ;
     RECT  8.112 65.267 9.312 66.661 ;
     RECT  31.896 65.461 33.072 65.603 ;
     RECT  27.216 65.555 27.24 66.325 ;
     RECT  20.496 66.085 21.12 66.517 ;
     RECT  35.88 66.085 37.296 66.899 ;
     RECT  7.44 66.179 7.632 67.379 ;
     RECT  26.952 66.325 27.24 66.565 ;
     RECT  22.824 66.515 24 67.859 ;
     RECT  19.704 66.517 21.12 67.859 ;
     RECT  26.952 66.565 28.128 67.139 ;
     RECT  28.152 66.565 29.136 66.803 ;
     RECT  8.112 66.661 9.168 67.093 ;
     RECT  28.152 66.803 29.4 68.387 ;
     RECT  30.264 66.899 31.872 67.765 ;
     RECT  35.88 66.899 37.32 66.949 ;
     RECT  35.88 66.949 37.344 68.147 ;
     RECT  8.112 67.093 9.12 68.965 ;
     RECT  7.44 67.379 7.8 67.477 ;
     RECT  6.504 67.477 7.8 68.867 ;
     RECT  10.584 67.571 10.92 67.859 ;
     RECT  30.744 67.765 31.872 68.387 ;
     RECT  29.712 67.811 30.72 68.435 ;
     RECT  10.2 67.859 10.92 68.965 ;
     RECT  7.92 69.129 9.024 69.143 ;
  END
END ot_s81_markov_chunk3_native
END LIBRARY
